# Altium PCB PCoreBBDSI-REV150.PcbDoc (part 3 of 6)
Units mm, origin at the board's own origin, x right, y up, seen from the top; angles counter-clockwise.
Board outline 100 x 72 mm, 6 copper layers (Top Layer, Int1 (GND), Int2 (Sign), Int3 (Sign), Int4 (GND), Bottom Layer), stack 1.538 mm thick; 358 components, 405 nets, 1521 pads, 834 vias.
Unrouted connection lines stored in the file: 10.

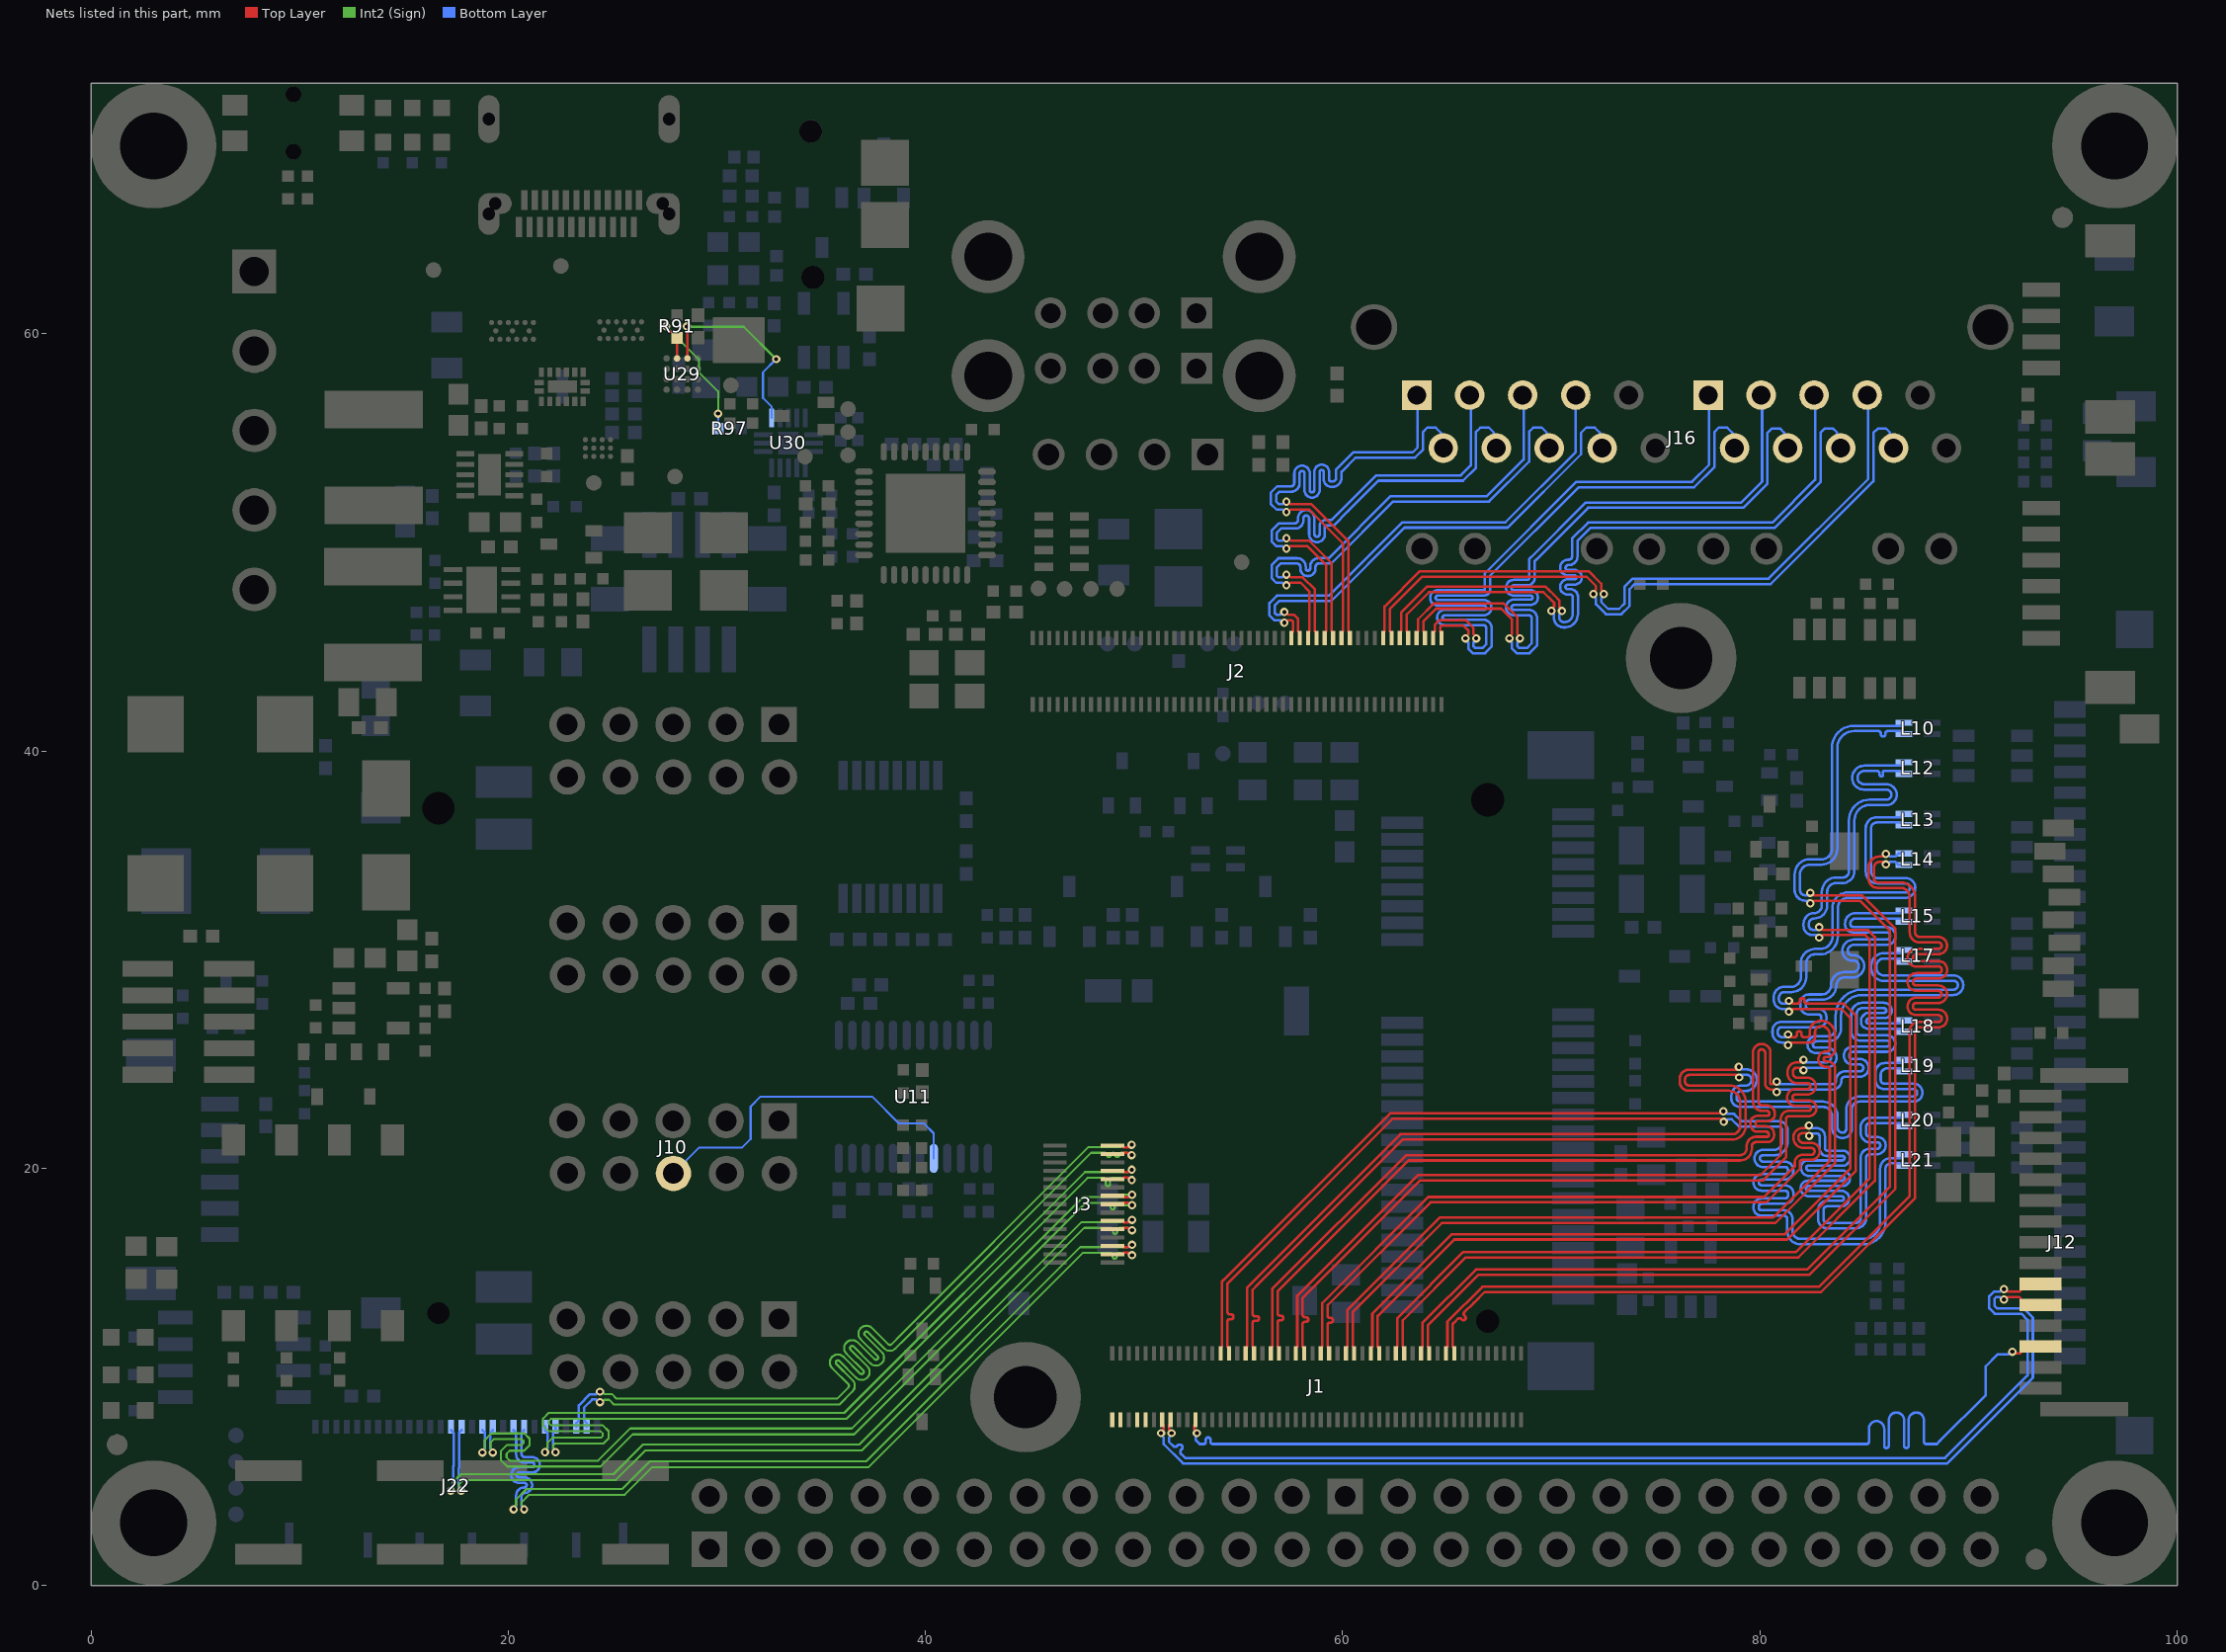
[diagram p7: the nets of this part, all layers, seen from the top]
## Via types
v1: diameter 0.4, hole 0.2, Top Layer to Bottom Layer, tented both sides, 706 vias
v2: diameter 0.5, hole 0.3, Top Layer to Bottom Layer, tented both sides, 102 vias
v3: diameter 0.4, hole 0.2, Top Layer to Bottom Layer, tented bottom, 16 vias
v4: diameter 0.9, hole 0.9, Top Layer to Bottom Layer, tented both sides, 6 vias
v5: diameter 0.5, hole 0.5, Top Layer to Bottom Layer, 2 vias
v6: diameter 3.2, hole 3.2, Top Layer to Bottom Layer, 2 vias

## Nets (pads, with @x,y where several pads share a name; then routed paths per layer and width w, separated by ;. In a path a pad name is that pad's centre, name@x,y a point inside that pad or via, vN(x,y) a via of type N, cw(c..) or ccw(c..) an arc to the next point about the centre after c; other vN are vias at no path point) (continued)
CSI_A_DATA0_P: J1.80 J12.3 | length 52.7
  Top Layer w0.12: J1.80@52.95,7.94 52.95,7.72 52.91,7.68 52.878,7.68 52.878,7.442 53.01,7.31 v1(53.01,7.3) ; v1(92.1,11.2) 92.176,11.2 92.259,11.117 92.471,11.117 92.51,11.156 92.51,11.21 92.75,11.45 J12.3@93.45,11.45
  Bottom Layer w0.12: v1(53.01,7.3) 52.965,7.255 52.965,6.959 53.07,6.853 53.146,6.777 53.33,6.777 ccw(c53.33,6.887) 53.44,6.887 53.44,6.985 cw(c53.55,6.985) 53.66,6.985 53.66,6.887 ccw(c53.77,6.887) 53.77,6.777 54.05,6.777 83.97,6.777 85.113,6.777 ccw(c85.113,6.887) 85.223,6.887 85.223,7.506 cw(c85.59,7.506) 85.59,7.873 cw(c85.59,7.506) 85.957,7.506 85.957,6.696 ccw(c86.067,6.696) 86.067,6.586 ccw(c86.067,6.696) 86.177,6.696 86.177,7.921 cw(c86.544,7.921) 86.544,8.288 cw(c86.544,7.921) 86.911,7.921 86.911,6.696 ccw(c87.021,6.696) 87.021,6.586 ccw(c87.021,6.696) 87.131,6.696 87.131,7.921 cw(c87.498,7.921) 87.498,8.288 cw(c87.498,7.921) 87.865,7.921 87.865,6.887 ccw(c87.975,6.887) 87.975,6.777 88.482,6.777 88.64,6.935 90.831,9.126 90.831,10.508 91.402,11.078 91.903,11.078 92.024,11.2 v1(92.1,11.2)
CSI_A_DATA1_N: J1.88 J12.5 | length 52.9
  Top Layer w0.12: v1(51.29,7.3) 51.307,7.3 51.422,7.415 51.422,7.68 51.39,7.68 51.35,7.72 J1.88@51.35,7.94 ; v1(91.7,13.7) 91.776,13.7 91.897,13.822 92.164,13.822 92.44,13.822 92.51,13.751 92.51,13.69 92.75,13.45 J12.5@93.45,13.45
  Bottom Layer w0.12: v1(51.29,7.3) 51.29,7.224 51.417,7.098 51.417,6.777 52.342,5.852 88.979,5.852 93.082,9.955 93.082,12.833 92.635,13.28 91.36,13.28 91.25,13.39 91.25,13.751 91.32,13.822 91.503,13.822 91.624,13.7 v1(91.7,13.7)
CSI_A_DATA1_P: J1.86 J12.6 | length 52.8
  Top Layer w0.12: J1.86@51.75,7.94 51.75,7.72 51.71,7.68 51.678,7.68 51.678,7.41 51.789,7.3 v1(51.8,7.3) ; v1(91.7,14.2) 91.776,14.2 91.897,14.078 92.27,14.078 92.44,14.078 92.51,14.149 92.51,14.21 92.75,14.45 J12.6@93.45,14.45
  Bottom Layer w0.12: v1(51.8,7.3) 51.8,7.224 51.673,7.098 51.673,7.021 51.673,6.884 51.873,6.684 ccw(c51.969,6.78) 52.064,6.684 52.09,6.71 cw(c52.186,6.615) 52.281,6.71 cw(c52.186,6.615) 52.281,6.519 52.255,6.493 ccw(c52.351,6.398) 52.255,6.302 52.449,6.109 52.528,6.109 88.873,6.109 92.825,10.061 92.825,12.727 92.529,13.023 91.254,13.023 90.993,13.284 90.993,13.858 91.214,14.078 91.503,14.078 91.624,14.2 v1(91.7,14.2)
CSI_A_DATA2_N: J1.94
CSI_A_DATA2_P: J1.92
CSI_A_DATA3_N: J1.100
CSI_A_DATA3_P: J1.98
CSI_B_CLK_N: J3.6 J22.9 | length 41.9
  Top Layer w0.12: J3.6@49.425,16.276 49.496,16.204 49.705,16.204 49.826,16.326 v1(49.897,16.326)
  Int2 (Sign) w0.1: v1(20.262,3.65) 20.262,3.731 20.372,3.842 20.372,4.116 20.882,4.625 25.464,4.625 26.79,5.951 37.158,5.951 47.422,16.216 49.705,16.216 49.816,16.326 v1(49.897,16.326)
  Bottom Layer w0.12: J22.9@20.26,7.46 20.26,7.435 20.382,7.313 20.382,6.933 ; v1(20.262,3.65) 20.262,3.708 20.381,3.827 20.381,4.006 ; 20.38,4.007 cw(c20.511,4.021) 20.38,4.021 20.38,4.305 cw(c20.768,4.305) 20.768,4.694 ccw(c20.768,4.807) 20.768,4.919 20.516,4.919 cw(c20.516,5.294) 20.516,5.669 21.135,5.669 ccw(c21.135,5.782) 21.135,5.894 20.768,5.894 cw(c20.768,6.283) 20.38,6.283 20.38,6.477 20.382,6.479 20.382,6.933
CSI_B_CLK_P: J3.4 J22.8 | length 41.9
  Top Layer w0.12: J3.4@49.425,15.876 49.496,15.948 49.705,15.948 49.826,15.826 v1(49.897,15.826)
  Int2 (Sign) w0.1: v1(20.762,3.65) 20.762,3.731 20.651,3.842 20.651,4 20.997,4.346 25.579,4.346 26.905,5.672 37.273,5.672 47.538,15.936 48.62,15.936 48.87,15.936 cw(c48.87,15.836) 48.97,15.836 48.97,15.757 ccw(c49.07,15.757) 49.17,15.757 49.17,15.836 cw(c49.27,15.836) 49.27,15.936 49.43,15.936 49.705,15.936 49.816,15.826 v1(49.897,15.826)
  Bottom Layer w0.12: 20.639,7.039 20.639,6.479 20.642,6.477 20.642,6.283 ccw(c20.768,6.283) 20.768,6.157 21.135,6.157 cw(c21.135,5.782) 21.135,5.407 20.516,5.407 ccw(c20.516,5.294) 20.516,5.181 20.768,5.181 cw(c20.768,4.807) 20.768,4.432 ccw(c20.768,4.305) 20.642,4.305 20.642,4.021 cw(c20.511,4.021) 20.641,4.007 ; 20.638,7.04 20.638,7.313 20.76,7.435 J22.8@20.76,7.46 ; 20.642,4.006 20.642,3.827 20.762,3.708 v1(20.762,3.65)
CSI_B_DATA0_N: J3.12 J22.15 | length 42
  Top Layer w0.12: J3.12@49.425,17.476 49.496,17.404 49.705,17.404 49.826,17.526 v1(49.9,17.526)
  Int2 (Sign) w0.1: v1(17.252,4.53) v1@17.252,4.602 ; v1@17.252,4.611 v1@17.252,4.602 ; v1@17.343,4.53 v1@17.343,4.693 ; v1@17.343,4.703 v1@17.343,4.693 ; v1(49.9,17.526) 49.819,17.526 49.708,17.416 47.492,17.416 36.828,6.751 26.46,6.751 25.045,5.336 19.509,5.336 17.731,5.336 17.362,4.967 17.362,4.712 v1@17.343,4.693 ; v1@17.252,4.602 v1@17.343,4.693
  Bottom Layer w0.12: J22.15@17.26,7.46 17.26,7.435 17.381,7.313 17.381,5.73 17.373,5.722 17.373,4.727 17.305,4.659 17.305,4.596 v1@17.371,4.53
CSI_B_DATA0_P: J3.10 J22.14 | length 42
  Top Layer w0.12: J3.10@49.425,17.076 49.496,17.148 49.705,17.148 49.826,17.026 v1(49.9,17.026)
  Int2 (Sign) w0.1: v1@17.66,4.53 v1@17.66,4.693 ; v1@17.66,4.703 v1@17.66,4.693 ; v1(17.752,4.53) v1@17.752,4.602 ; v1@17.752,4.611 v1@17.752,4.602 ; v1(49.9,17.026) 49.819,17.026 49.708,17.136 49.45,17.136 49.291,17.136 ccw(c49.291,17.036) 49.191,17.036 49.191,16.949 cw(c49.091,16.949) 48.991,16.949 48.991,17.036 ccw(c48.891,17.036) 48.891,17.136 48.641,17.136 47.608,17.136 36.943,6.472 26.575,6.472 25.16,5.057 17.847,5.057 17.641,4.851 17.641,4.712 v1@17.66,4.693 ; v1@17.66,4.693 v1@17.752,4.602
  Bottom Layer w0.12: v1@17.752,4.488 17.752,4.606 17.63,4.727 17.63,5.616 17.638,5.624 17.638,7.313 17.76,7.435 J22.14@17.76,7.46
CSI_B_DATA1_N: J3.18 J22.12 | length 41.9
  Top Layer w0.12: J3.18@49.425,18.676 49.496,18.604 49.705,18.604 49.826,18.726 v1(49.9,18.726)
  Int2 (Sign) w0.1: v1(18.76,6.37) 18.76,6.451 18.87,6.562 18.87,6.969 19.191,7.289 20.767,7.289 21.02,7.037 21.02,6.72 20.76,6.46 20.068,6.46 19.919,6.311 19.919,6.131 20.073,5.977 24.302,5.977 25.847,7.521 36.468,7.521 47.562,18.616 49.368,18.616 ccw(c49.368,18.671) 49.407,18.631 49.502,18.726 v1(49.9,18.726)
  Bottom Layer w0.12: v1(18.76,6.37) 18.76,6.446 18.882,6.567 18.882,7.313 18.76,7.435 J22.12@18.76,7.46
CSI_B_DATA1_P: J3.16 J22.11 | length 41.9
  Top Layer w0.12: J3.16@49.425,18.276 49.496,18.348 49.705,18.348 49.826,18.226 v1(49.9,18.226)
  Int2 (Sign) w0.1: v1(19.26,6.37) 19.26,6.451 19.15,6.562 19.15,6.853 19.307,7.01 20.652,7.01 20.741,6.921 20.741,6.836 20.644,6.739 19.952,6.739 19.64,6.427 19.64,6.016 19.958,5.698 24.418,5.698 25.962,7.242 36.583,7.242 47.678,18.336 48.523,18.336 48.773,18.336 cw(c48.773,18.236) 48.873,18.236 48.873,18.123 ccw(c48.973,18.123) 49.073,18.123 49.073,18.236 cw(c49.173,18.236) 49.173,18.336 49.368,18.336 cw(c49.368,18.281) 49.407,18.321 49.489,18.239 49.502,18.226 v1(49.9,18.226)
  Bottom Layer w0.12: v1(19.26,6.37) 19.26,6.446 19.138,6.567 19.138,7.313 19.26,7.435 J22.11@19.26,7.46
CSI_B_DATA2_N: J3.24 J22.6 | length 41.8
  Top Layer w0.12: J3.24@49.425,19.876 49.496,19.804 49.705,19.804 49.826,19.926 v1(49.89,19.926)
  Int2 (Sign) w0.1: v1(21.76,6.39) 21.76,6.462 21.87,6.572 21.88,6.572 21.88,6.836 22.123,7.079 24.439,7.079 24.53,7.17 24.53,7.28 24.42,7.39 21.93,7.39 21.67,7.65 21.67,8 21.941,8.271 36.108,8.271 47.652,19.816 48.43,19.816 49.366,19.816 49.698,19.816 49.809,19.926 v1(49.89,19.926)
  Bottom Layer w0.12: v1(21.76,6.39) 21.76,6.447 21.882,6.569 21.882,7.313 21.76,7.435 J22.6@21.76,7.61
CSI_B_DATA2_P: J3.22 J22.5 | length 41.9
  Top Layer w0.12: J3.22@49.425,19.476 49.496,19.548 49.705,19.548 49.826,19.426 v1(49.89,19.426)
  Int2 (Sign) w0.1: v1@22.209,6.512 22.26,6.462 v1(22.26,6.39) ; v1@22.214,6.517 22.168,6.563 22.159,6.563 22.159,6.72 22.239,6.8 24.555,6.8 24.809,7.054 24.809,7.396 24.536,7.669 22.046,7.669 21.949,7.766 21.949,7.885 22.057,7.992 36.223,7.992 47.768,19.536 48.295,19.536 48.545,19.536 cw(c48.545,19.436) 48.645,19.436 48.645,19.243 ccw(c48.745,19.243) 48.845,19.243 48.845,19.436 cw(c48.945,19.436) 48.945,19.536 49.25,19.536 49.698,19.536 49.809,19.426 v1(49.89,19.426)
  Bottom Layer w0.12: v1(22.26,6.39) 22.26,6.447 22.138,6.569 22.138,7.313 22.26,7.435 J22.5@22.26,7.61
CSI_B_DATA3_N: J3.30 J22.3 | length 42
  Top Layer w0.12: J3.30@49.425,21.076 49.496,21.004 49.705,21.004 49.826,21.126 v1(49.887,21.126)
  Int2 (Sign) w0.1: v1(24.4,9.288) 24.481,9.288 24.592,9.178 24.958,9.178 25.188,8.948 35.292,8.948 35.757,8.948 36.303,9.495 ccw(c36.23,9.568) 36.303,9.642 35.529,10.416 cw(c35.799,10.686) 35.528,10.956 ; v1(49.887,21.126) 49.829,21.126 ccw(c49.829,21.071) 49.79,21.11 49.712,21.031 cw(c49.673,21.071) 49.673,21.016 47.824,21.016 38.843,12.035 38.366,11.557 cw(c38.292,11.63) 38.219,11.557 37.441,12.335 ccw(c37.171,12.064) 36.9,12.335 36.899,12.334 ccw(c37.171,12.064) 36.9,11.794 37.701,10.993 cw(c37.628,10.92) 37.701,10.847 cw(c37.628,10.92) 37.555,10.847 36.754,11.647 ccw(c36.483,11.377) 36.213,11.647 36.212,11.647 ccw(c36.483,11.377) 36.213,11.106 37.014,10.306 cw(c36.941,10.232) 37.014,10.159 cw(c36.941,10.232) 36.867,10.159 36.07,10.957 ccw(c35.799,10.686) 35.529,10.957 ; 35.528,10.956 35.529,10.957
  Bottom Layer w0.12: J22.3@23.26,7.61 23.26,7.785 23.382,7.907 23.382,8.635 23.914,9.167 24.203,9.167 24.324,9.288 v1(24.4,9.288)
CSI_B_DATA3_P: J3.28 J22.2 | length 42
  Top Layer w0.12: J3.28@49.425,20.676 49.496,20.748 49.705,20.748 49.826,20.626 v1(49.887,20.626)
  Int2 (Sign) w0.1: v1(24.4,8.788) 24.481,8.788 24.592,8.899 24.842,8.899 25.072,8.669 35.571,8.669 35.757,8.669 35.872,8.669 36.501,9.297 ccw(c36.23,9.568) 36.542,9.79 36.542,9.798 36.501,9.838 35.726,10.613 cw(c35.799,10.686) 35.726,10.76 cw(c35.799,10.686) 35.872,10.76 36.67,9.962 ccw(c36.941,10.232) 37.211,9.962 ccw(c36.941,10.232) 37.211,10.503 36.41,11.304 cw(c36.483,11.377) 36.41,11.45 cw(c36.483,11.377) 36.557,11.45 37.357,10.649 ccw(c37.628,10.92) 37.898,10.648 ; v1(49.887,20.626) 49.829,20.626 cw(c49.829,20.681) 49.79,20.642 49.712,20.721 ccw(c49.673,20.681) 49.673,20.736 49.593,20.736 49.39,20.736 ccw(c49.39,20.636) 49.29,20.636 49.29,20.628 cw(c49.19,20.628) 49.09,20.628 49.09,20.636 ccw(c48.99,20.636) 48.89,20.636 48.89,20.628 cw(c48.79,20.628) 48.69,20.628 48.69,20.636 ccw(c48.59,20.636) 48.59,20.736 48.34,20.736 47.94,20.736 39.041,11.837 38.563,11.36 cw(c38.292,11.63) 38.022,11.36 37.244,12.138 ccw(c37.171,12.064) 37.098,12.138 ccw(c37.171,12.064) 37.098,11.991 37.898,11.19 cw(c37.628,10.92) 37.898,10.649 ; 37.898,10.648 37.898,10.649
  Bottom Layer w0.12: J22.2@23.76,7.61 23.76,7.785 23.638,7.907 23.638,8.528 24.02,8.91 24.203,8.91 24.324,8.788 v1(24.4,8.788)
CTS_B_RS232: J10.6 U11.17 | length 16.8
  Bottom Layer w0.1: J10.6@27.92,19.75 29.16,20.99 31.21,20.99 31.62,21.4 31.62,22.95 32.1,23.43 37.447,23.43 38.737,22.14 39.93,22.14 40.395,21.675 U11.17@40.395,20.47
DSI_A_CLK_N: J1.19 L14.4 | length 56.4
  Top Layer w0.12: J1.19@64.948,11.368 65.022,11.442 65.022,11.952 65.022,12.644 66.696,14.318 82.827,14.318 87.185,18.675 87.185,26.591 cw(c87.6,26.591) 87.6,27.007 88.557,27.007 ccw(c88.557,27.17) 88.72,27.17 ccw(c88.55,27.17) 88.55,27.34 87.483,27.34 cw(c87.483,27.75) 87.073,27.75 cw(c87.5,27.75) 87.5,28.177 88.547,28.177 ccw(c88.547,28.34) 88.71,28.34 ccw(c88.55,28.34) 88.55,28.5 87.493,28.5 cw(c87.493,28.92) 87.073,28.92 cw(c87.5,28.92) 87.5,29.347 88.557,29.347 ccw(c88.557,29.51) 88.72,29.51 ccw(c88.56,29.51) 88.56,29.67 87.493,29.67 cw(c87.493,30.09) 87.073,30.09 cw(c87.49,30.09) 87.49,30.507 88.547,30.507 ccw(c88.547,30.67) 88.71,30.67 ccw(c88.55,30.67) 88.55,30.83 87.653,30.83 cw(c87.653,31.3) 87.183,31.3 87.183,33.007 ccw(c86.75,33.007) 86.75,33.44 85.633,33.44 cw(c85.633,33.86) 85.213,33.86 85.213,34.421 cw(c85.73,34.421) 85.73,34.938 85.918,34.938 ccw(c85.918,35.06) v1(86.04,35.06)
  Bottom Layer w0.12: v1(86.04,35.06) 86.116,35.06 86.237,34.938 86.498,34.938 86.645,35.085 L14.4@86.895,35.085
DSI_A_CLK_P: J1.17 L14.1 | length 56.3
  Top Layer w0.12: J1.17@65.348,11.372 65.278,11.442 65.278,11.845 65.278,12.537 65.324,12.582 65.522,12.78 cw(c65.599,12.703) 65.677,12.78 65.713,12.744 ccw(c65.791,12.822) 65.869,12.744 ccw(c65.791,12.822) 65.869,12.9 65.833,12.936 cw(c65.911,13.014) 65.833,13.091 66.274,13.532 66.802,14.061 82.934,14.061 87.441,18.569 87.441,26.591 cw(c87.6,26.591) 87.6,26.75 88.557,26.75 ccw(c88.557,27.17) 88.977,27.17 ccw(c88.55,27.17) 88.55,27.597 87.483,27.597 cw(c87.483,27.75) 87.33,27.75 cw(c87.5,27.75) 87.5,27.92 88.547,27.92 ccw(c88.547,28.34) 88.967,28.34 ccw(c88.55,28.34) 88.55,28.757 87.493,28.757 cw(c87.493,28.92) 87.33,28.92 cw(c87.5,28.92) 87.5,29.09 88.557,29.09 ccw(c88.557,29.51) 88.977,29.51 ccw(c88.56,29.51) 88.56,29.927 87.493,29.927 cw(c87.493,30.09) 87.33,30.09 cw(c87.49,30.09) 87.49,30.25 88.547,30.25 ccw(c88.547,30.67) 88.967,30.67 ccw(c88.55,30.67) 88.55,31.087 87.653,31.087 cw(c87.653,31.3) 87.44,31.3 87.44,33.007 ccw(c86.75,33.007) 86.75,33.697 85.633,33.697 cw(c85.633,33.86) 85.47,33.86 85.47,34.421 cw(c85.73,34.421) 85.73,34.682 85.918,34.682 cw(c85.918,34.56) v1(86.04,34.56)
  Bottom Layer w0.12: v1(86.04,34.56) 86.116,34.56 86.237,34.682 86.498,34.682 86.645,34.535 L14.1@86.895,34.535
DSI_A_DATA0_N: J1.25 L10.4 | length 56.4
  Top Layer w0.12: J1.25@63.748,11.368 63.822,11.442 63.822,12.574 66.386,15.138 82.257,15.138 86.234,19.116 86.234,27.115 86.234,31.376 84.789,32.822 84.012,32.822 82.607,32.822 82.486,32.7 v1(82.41,32.7)
  Bottom Layer w0.12: v1(82.41,32.7) ccw(c82.288,32.7) 82.288,32.822 82.19,32.822 cw(c82.19,33.348) 81.663,33.348 81.663,34.08 cw(c82.39,34.08) 82.39,34.807 82.947,34.807 ccw(c82.947,35.313) 83.453,35.313 83.453,40.148 ; 83.453,40.15 cw(c84.512,40.15) 84.512,41.208 86.748,41.208 ccw(c86.748,41.355) L10.4@86.895,41.355
DSI_A_DATA0_P: J1.23 L10.1 | length 56.3
  Top Layer w0.12: J1.23@64.148,11.372 64.078,11.442 64.078,12.467 66.492,14.881 82.363,14.881 86.491,19.009 86.491,27.372 86.491,31.482 84.895,33.078 82.607,33.078 82.539,33.146 v1@82.476,33.146
  Bottom Layer w0.12: v1(82.41,33.2) cw(c82.288,33.2) 82.288,33.078 82.19,33.078 cw(c82.19,33.348) 81.92,33.348 81.92,34.08 cw(c82.39,34.08) 82.39,34.55 82.947,34.55 ccw(c82.947,35.313) 83.71,35.313 83.71,40.147 ccw(c83.582,40.148) 83.71,40.149 cw(c84.512,40.15) 84.512,40.952 85.401,40.952 85.681,40.952 cw(c85.681,40.842) 85.791,40.842 85.791,40.801 ccw(c85.901,40.801) 86.011,40.801 86.011,40.842 cw(c86.121,40.842) 86.121,40.952 86.705,40.952 86.748,40.952 cw(c86.748,40.805) L10.1@86.895,40.805
DSI_A_DATA1_N: J1.31 L12.4 | length 56.4
  Top Layer w0.12: J1.31@62.548,11.368 62.622,11.442 62.622,12.037 62.622,12.814 65.787,15.98 81.739,15.98 85.255,19.496 85.255,30.976 85.058,31.172 83.019,31.172 82.916,31.069 82.916,31.05 v1(82.84,31.05)
  Bottom Layer w0.12: v1(82.84,31.05) ccw(c82.718,31.05) 82.718,31.172 82.53,31.172 cw(c82.53,31.609) 82.093,31.609 82.093,31.72 cw(c82.6,31.72) 82.6,32.227 ccw(c82.6,32.597) 82.97,32.597 82.97,33.247 cw(c83.65,33.247) 83.65,33.927 83.957,33.927 ccw(c83.957,34.24) 84.27,34.24 84.27,36.677 cw(c85.26,36.677) 85.26,37.667 86.067,37.667 ccw(c86.067,37.9) 86.3,37.9 ccw(c86.05,37.9) 86.05,38.15 84.983,38.15 cw(c84.983,38.71) 84.423,38.71 cw(c85.01,38.71) 85.01,39.297 86.737,39.297 ccw(c86.737,39.455) L12.4@86.895,39.455
DSI_A_DATA1_P: J1.29 L12.1 | length 56.5
  Top Layer w0.12: J1.29@62.948,11.372 62.878,11.442 62.878,11.931 62.878,12.708 65.894,15.723 81.845,15.723 85.511,19.389 85.511,31.082 85.165,31.429 83.019,31.429 82.897,31.55 v1@82.72,31.55
  Bottom Layer w0.12: v1(82.84,31.55) cw(c82.718,31.55) 82.718,31.429 82.53,31.429 cw(c82.53,31.609) 82.35,31.609 82.35,31.72 cw(c82.6,31.72) 82.6,31.97 ccw(c82.6,32.597) 83.227,32.597 83.227,33.247 cw(c83.65,33.247) 83.65,33.67 83.957,33.67 ccw(c83.957,34.24) 84.527,34.24 84.527,36.677 cw(c85.26,36.677) 85.26,37.41 86.067,37.41 ccw(c86.067,37.9) 86.557,37.9 ccw(c86.05,37.9) 86.05,38.407 84.983,38.407 cw(c84.983,38.71) 84.68,38.71 cw(c85.01,38.71) 85.01,39.04 85.61,39.04 cw(c85.61,38.91) 85.74,38.91 85.74,38.86 ccw(c85.82,38.86) 85.82,38.78 ccw(c85.82,38.86) 85.9,38.86 85.9,38.98 cw(c85.96,38.98) 85.96,39.04 86.76,39.04 cw(c86.76,38.905) L12.1@86.895,38.905
DSI_A_DATA2_N: J1.37 L13.4 | length 56.3
  Top Layer w0.12: J1.37@61.348,11.368 61.422,11.442 61.422,13.024 65.237,16.839 81.197,16.839 84.341,19.983 84.341,27.198 83.907,27.632 81.569,27.632 81.437,27.5 v1(81.39,27.5)
  Bottom Layer w0.12: v1(81.39,27.5) ccw(c81.259,27.5) 81.259,27.632 81.11,27.632 cw(c81.11,28.089) 80.653,28.089 80.653,28.18 cw(c81.17,28.18) 81.17,28.697 81.507,28.697 ccw(c81.507,29.15) 81.96,29.15 81.96,29.827 cw(c82.64,29.827) 82.64,30.507 82.877,30.507 ccw(c82.877,31.11) 83.48,31.11 83.48,32.477 cw(c84.22,32.477) 84.22,33.217 86.957,33.217 ccw(c86.957,33.45) 87.19,33.45 ccw(c86.99,33.45) 86.99,33.65 85.643,33.65 cw(c85.643,34.22) 85.073,34.22 85.073,36.3 cw(c85.6,36.3) 85.6,36.827 86.737,36.827 ccw(c86.737,36.985) L13.4@86.895,36.985
DSI_A_DATA2_P: J1.35 L13.1 | length 56.3
  Top Layer w0.12: J1.35@61.748,11.372 61.678,11.442 61.678,12.917 65.343,16.582 81.303,16.582 84.598,19.877 84.598,27.304 84.014,27.889 82.526,27.889 82.246,27.889 cw(c82.246,27.999) 82.136,27.999 82.136,28.045 ccw(c82.026,28.045) 81.916,28.045 81.916,27.999 cw(c81.806,27.999) 81.806,27.889 81.569,27.889 81.437,28.02 v1(81.39,28.02)
  Bottom Layer w0.12: v1(81.39,28.02) cw(c81.259,28.02) 81.259,27.889 81.11,27.889 cw(c81.11,28.089) 80.91,28.089 80.91,28.18 cw(c81.17,28.18) 81.17,28.44 81.507,28.44 ccw(c81.507,29.15) 82.217,29.15 82.217,29.827 cw(c82.64,29.827) 82.64,30.25 82.877,30.25 ccw(c82.877,31.11) 83.737,31.11 83.737,32.477 cw(c84.22,32.477) 84.22,32.96 86.957,32.96 ccw(c86.957,33.45) 87.447,33.45 ccw(c86.99,33.45) 86.99,33.907 85.643,33.907 cw(c85.643,34.22) 85.33,34.22 85.33,36.3 cw(c85.6,36.3) 85.6,36.57 86.76,36.57 cw(c86.76,36.435) L13.1@86.895,36.435
DSI_A_DATA3_N: J1.43 L15.4 | length 56.3
  Top Layer w0.12: J1.43@60.148,11.368 60.222,11.442 60.222,13.203 64.65,17.631 80.631,17.631 83.35,20.35 83.35,23.91 83.35,24.751 ccw(c83.24,24.751) 83.24,24.861 83.169,24.861 cw(c83.169,25.228) 83.169,25.595 83.24,25.595 ccw(c83.24,25.705) 83.35,25.705 83.35,26.37 83.35,26.39 ccw(c82.93,26.39) 82.93,26.81 ccw(c82.93,26.52) 82.64,26.52 82.64,26.284 cw(c82.383,26.284) 82.383,26.027 81.477,26.027 ccw(c81.477,25.9) v1(81.35,25.9)
  Bottom Layer w0.12: v1(81.35,25.9) ccw(c81.223,25.9) 81.223,26.027 81.047,26.027 cw(c81.047,26.47) 80.603,26.47 80.603,26.59 cw(c81.03,26.59) 81.03,27.017 82.787,27.017 ccw(c82.787,27.16) 82.93,27.16 82.93,27.25 ccw(c82.81,27.25) 82.81,27.37 82.353,27.37 cw(c82.353,27.78) 81.943,27.78 81.943,27.91 cw(c82.36,27.91) 82.36,28.327 82.967,28.327 ccw(c82.967,28.77) 83.41,28.77 cw(c84.037,28.77) 84.037,29.397 84.437,29.397 ccw(c84.437,29.7) 84.74,29.7 ccw(c84.49,29.7) 84.49,29.95 84.423,29.95 cw(c84.423,30.42) 83.953,30.42 cw(c84.49,30.42) 84.49,30.957 86.067,30.957 ccw(c86.067,31.13) 86.24,31.13 ccw(c86.06,31.13) 86.06,31.31 84.46,31.31 cw(c84.46,31.687) 84.083,31.687 84.083,31.73 cw(c84.58,31.73) 84.58,32.227 86.767,32.227 ccw(c86.767,32.355) L15.4@86.895,32.355
DSI_A_DATA3_P: J1.41 L15.1 | length 56.2
  Top Layer w0.12: J1.41@60.548,11.372 60.478,11.442 60.478,13.096 64.756,17.374 80.738,17.374 83.607,20.244 83.607,23.91 83.607,24.751 ccw(c83.24,24.751) 83.24,25.118 83.169,25.118 cw(c83.169,25.228) 83.169,25.338 83.24,25.338 ccw(c83.24,25.705) 83.607,25.705 83.607,26.37 83.607,26.39 ccw(c82.93,26.39) 82.93,27.067 ccw(c82.93,26.52) 82.383,26.52 82.383,26.39 cw(c82.277,26.39) 82.383,26.387 cw(c82.277,26.39) 82.323,26.294 82.277,26.283 82.103,26.283 cw(c82.103,26.393) 81.993,26.393 81.993,26.456 ccw(c81.883,26.456) 81.773,26.456 81.773,26.393 cw(c81.663,26.393) 81.663,26.283 81.477,26.283 cw(c81.477,26.41) v1(81.35,26.41)
  Bottom Layer w0.12: v1(81.35,26.41) cw(c81.223,26.41) 81.223,26.283 81.047,26.283 cw(c81.047,26.47) 80.86,26.47 80.86,26.59 cw(c81.03,26.59) 81.03,26.76 82.787,26.76 ccw(c82.787,27.16) 83.187,27.16 83.187,27.25 ccw(c82.81,27.25) 82.81,27.627 82.353,27.627 cw(c82.353,27.78) 82.2,27.78 82.2,27.91 cw(c82.36,27.91) 82.36,28.07 82.967,28.07 ccw(c82.967,28.77) 83.667,28.77 cw(c84.037,28.77) 84.037,29.14 84.437,29.14 ccw(c84.437,29.7) 84.997,29.7 ccw(c84.49,29.7) 84.49,30.207 84.423,30.207 cw(c84.423,30.42) 84.21,30.42 cw(c84.49,30.42) 84.49,30.7 86.067,30.7 ccw(c86.067,31.13) 86.497,31.13 ccw(c86.06,31.13) 86.06,31.567 84.46,31.567 cw(c84.46,31.687) 84.34,31.687 84.34,31.73 cw(c84.58,31.73) 84.58,31.97 86.73,31.97 cw(c86.73,31.805) L15.1@86.895,31.805
DSI_B_CLK_N: J1.49 L20.4 | length 56.2
  Top Layer w0.12: J1.49@58.948,11.368 59.021,11.442 59.021,12.399 59.022,13.539 64.101,18.619 80.201,18.619 81.669,20.087 81.669,20.259 cw(c82.05,20.259) 82.05,20.64 82.46,20.64 ccw(c82.46,20.8) 82.62,20.8 82.62,20.82 ccw(c82.471,20.82) 82.471,20.969 82.1,20.969 cw(c82.1,21.47) 81.599,21.47 cw(c82.049,21.47) 82.049,21.92 82.22,21.92 ccw(c82.22,22.05) v1(82.35,22.05)
  Bottom Layer w0.12: v1(82.35,22.05) ccw(c82.472,22.05) 82.472,21.928 82.71,21.928 cw(c82.71,21.522) 83.117,21.522 83.117,20.953 ccw(c83.23,20.953) 83.23,20.84 83.967,20.84 cw(c83.967,20.49) 84.317,20.49 cw(c83.94,20.49) 83.94,20.113 82.303,20.113 ccw(c82.303,20.03) 82.22,20.03 ccw(c82.37,20.03) 82.37,19.88 83.957,19.88 cw(c83.957,19.52) 84.317,19.52 cw(c83.94,19.52) 83.94,19.143 82.313,19.143 ccw(c82.313,19.04) 82.21,19.04 ccw(c82.34,19.04) 82.34,18.91 83.917,18.91 cw(c83.917,18.55) 84.277,18.55 cw(c83.9,18.55) 83.9,18.173 83.213,18.173 ccw(c83.213,18.01) 83.05,18.01 83.05,17.55 ccw(c83.22,17.55) 83.22,17.38 84.61,17.38 ccw(c84.61,17.6) 84.83,17.6 84.83,20.507 cw(c85.25,20.507) 85.25,20.927 85.597,20.927 ccw(c85.597,21.1) 85.77,21.1 ccw(c85.63,21.1) 85.63,21.24 85.283,21.24 cw(c85.283,21.69) 84.833,21.69 84.833,21.98 cw(c85.272,21.98) 85.272,22.418 86.748,22.418 86.821,22.418 ccw(c86.821,22.484) 86.885,22.47 ccw(c86.438,22.565) 86.886,22.475 L20.4@86.895,22.565
DSI_B_CLK_P: J1.47 L20.1 | length 56.1
  Top Layer w0.12: J1.47@59.348,11.372 59.278,11.442 59.278,11.867 59.278,11.927 59.278,12.489 cw(c59.388,12.489) 59.388,12.599 59.422,12.599 ccw(c59.422,12.709) 59.422,12.819 59.388,12.819 cw(c59.388,12.929) 59.278,12.929 59.278,12.989 59.278,13.433 64.207,18.362 80.307,18.362 81.918,19.972 81.918,20.252 81.91,20.26 cw(c82.05,20.259) 82.05,20.399 82.46,20.399 ccw(c82.46,20.8) 82.861,20.8 82.861,20.82 ccw(c82.471,20.82) 82.471,21.21 82.1,21.21 cw(c82.1,21.47) 81.84,21.47 cw(c82.049,21.47) 82.049,21.679 82.22,21.679 ccw(c82.22,22.05) 82.237,21.679 cw(c82.231,21.55) v1(82.36,21.55)
  Bottom Layer w0.12: v1(82.36,21.55) cw(c82.482,21.55) 82.482,21.672 82.71,21.672 cw(c82.71,21.522) 82.86,21.522 82.86,20.953 ccw(c83.23,20.953) 83.23,20.583 83.967,20.583 cw(c83.967,20.49) 84.06,20.49 cw(c83.94,20.49) 83.94,20.37 82.303,20.37 ccw(c82.303,20.03) 81.963,20.03 ccw(c82.37,20.03) 82.37,19.623 83.957,19.623 cw(c83.957,19.52) 84.06,19.52 cw(c83.94,19.52) 83.94,19.4 82.313,19.4 ccw(c82.313,19.04) 81.953,19.04 ccw(c82.34,19.04) 82.34,18.653 83.917,18.653 cw(c83.917,18.55) 84.02,18.55 cw(c83.9,18.55) 83.9,18.43 83.213,18.43 ccw(c83.213,18.01) 82.793,18.01 82.793,17.55 ccw(c83.22,17.55) 83.22,17.123 84.61,17.123 ccw(c84.61,17.6) 85.087,17.6 85.087,20.507 cw(c85.25,20.507) 85.25,20.67 85.597,20.67 ccw(c85.597,21.1) 86.027,21.1 ccw(c85.63,21.1) 85.63,21.497 85.283,21.497 cw(c85.283,21.69) 85.09,21.69 85.09,21.98 cw(c85.272,21.98) 85.272,22.162 86.748,22.162 cw(c86.748,22.015) L20.1@86.895,22.015
DSI_B_DATA0_N: J1.55 L17.4 | length 56.5
  Top Layer w0.12: J1.55@57.75,11.12 57.75,11.37 57.822,11.442 57.822,13.885 63.614,19.677 80.047,19.677 80.99,20.62 80.99,22.337 cw(c81.4,22.337) 81.4,22.747 82.327,22.747 ccw(c82.327,22.87) 82.45,22.87 ccw(c82.33,22.87) 82.33,22.99 81.703,22.99 cw(c81.703,23.39) 81.303,23.39 cw(c81.7,23.39) 81.7,23.787 82.277,23.787 ccw(c82.277,23.93) 82.42,23.93 82.42,23.94 ccw(c82.28,23.94) 82.28,24.08 81.793,24.08 cw(c81.793,24.55) 81.323,24.55 81.323,24.62 cw(c81.78,24.62) 81.78,25.077 81.967,25.077 ccw(c81.967,25.2) v1(82.09,25.2)
  Bottom Layer w0.12: v1(82.09,25.2) ccw(c82.212,25.2) 82.212,25.079 83.179,25.079 ccw(c83.179,25.31) 83.41,25.31 ccw(c83.2,25.31) 83.2,25.52 82.683,25.52 cw(c82.683,25.92) 82.283,25.92 cw(c82.7,25.92) 82.7,26.337 83.277,26.337 ccw(c83.277,26.69) 83.63,26.69 83.63,27.297 cw(c84.89,27.297) 84.89,28.557 89.267,28.557 ccw(c89.267,28.78) 89.49,28.78 ccw(c89.29,28.78) 89.29,28.98 85.943,28.98 cw(c85.943,29.59) 85.333,29.59 85.333,29.7 cw(c85.94,29.7) 85.94,30.307 86.747,30.307 ccw(c86.747,30.455) L17.4@86.895,30.455
DSI_B_DATA0_P: J1.53 L17.1 | length 56.5
  Top Layer w0.12: J1.53@58.15,11.12 58.15,11.37 58.078,11.442 58.078,11.808 58.078,12.528 cw(c58.188,12.528) 58.188,12.638 58.241,12.638 ccw(c58.241,12.748) 58.241,12.858 58.188,12.858 cw(c58.188,12.968) 58.078,12.968 58.078,13.18 58.078,13.778 63.72,19.42 80.153,19.42 81.247,20.514 81.247,22.337 cw(c81.4,22.337) 81.4,22.49 82.327,22.49 ccw(c82.327,22.87) 82.707,22.87 ccw(c82.33,22.87) 82.33,23.247 81.703,23.247 cw(c81.703,23.39) 81.56,23.39 cw(c81.7,23.39) 81.7,23.53 82.277,23.53 ccw(c82.277,23.93) 82.677,23.93 82.677,23.94 ccw(c82.28,23.94) 82.28,24.337 81.793,24.337 cw(c81.793,24.55) 81.58,24.55 81.58,24.62 cw(c81.78,24.62) 81.78,24.82 81.97,24.82 cw(c81.97,24.7) v1(82.09,24.7)
  Bottom Layer w0.12: v1(82.09,24.7) cw(c82.212,24.7) 82.212,24.822 83.179,24.822 ccw(c83.179,25.31) 83.667,25.31 ccw(c83.2,25.31) 83.2,25.777 82.683,25.777 cw(c82.683,25.92) 82.54,25.92 cw(c82.7,25.92) 82.7,26.08 83.277,26.08 ccw(c83.277,26.69) 83.887,26.69 83.887,27.297 cw(c84.89,27.297) 84.89,28.3 89.267,28.3 ccw(c89.267,28.78) 89.747,28.78 ccw(c89.29,28.78) 89.29,29.237 85.943,29.237 cw(c85.943,29.59) 85.59,29.59 85.59,29.7 cw(c85.94,29.7) 85.94,30.05 86.75,30.05 cw(c86.75,29.905) L17.1@86.895,29.905
DSI_B_DATA1_N: J1.61 L18.4 | length 56.4
  Top Layer w0.12: J1.61@56.548,11.368 56.621,11.442 56.621,14.204 63.046,20.628 79.061,20.628 ccw(c79.061,20.92) 79.353,20.92 79.353,21.04 cw(c79.82,21.04) 79.82,21.507 80.357,21.507 ccw(c80.357,21.57) 80.42,21.57 80.42,21.63 ccw(c80.3,21.63) 80.3,21.75 79.883,21.75 cw(c79.883,22.007) 79.878,21.75 cw(c79.884,22.073) 79.655,21.845 cw(c79.884,22.073) 79.572,21.987 79.546,22.082 cw(c79.794,22.15) 79.537,22.15 cw(c79.904,22.15) 79.904,22.517 80.367,22.517 ccw(c80.367,22.61) 80.46,22.61 ccw(c80.32,22.61) 80.32,22.75 80.103,22.75 cw(c80.103,23.18) 79.948,22.779 cw(c80.103,23.18) 79.702,23.025 cw(c80.103,23.18) 79.673,23.18 79.673,25.55 cw(c80.08,25.55) 80.08,25.957 cw(c80.08,25.53) 80.507,25.53 80.507,24.073 ccw(c80.55,24.073) 80.55,24.03 80.68,24.03 ccw(c80.68,24.15) v1(80.8,24.15)
  Bottom Layer w0.12: v1(80.8,24.15) ccw(c80.922,24.15) 80.922,24.028 83.478,24.028 ccw(c83.478,24.2) 83.65,24.2 cw(c84.097,24.2) 84.097,24.647 84.807,24.647 ccw(c84.807,24.8) 84.96,24.8 ccw(c84.78,24.8) 84.78,24.98 84.433,24.98 cw(c84.433,25.39) 84.023,25.39 cw(c84.47,25.39) 84.47,25.837 86.097,25.837 ccw(c86.097,25.97) 86.23,25.97 ccw(c86.09,25.97) 86.09,26.11 84.823,26.11 cw(c84.823,26.56) 84.373,26.56 84.373,27.39 cw(c84.91,27.39) 84.91,27.927 85.94,27.927 cw(c85.94,27.55) 86.317,27.55 cw(c85.96,27.55) 85.96,27.193 85.253,27.193 ccw(c85.253,27.04) 85.1,27.04 85.1,27.03 ccw(c85.192,27.03) 85.192,26.938 86.748,26.938 ccw(c86.748,27.085) L18.4@86.895,27.085
DSI_B_DATA1_P: J1.59 L18.1 | length 56.3
  Top Layer w0.12: J1.59@56.948,11.372 56.878,11.442 56.878,12.602 cw(c56.988,12.602) 56.988,12.712 57.045,12.712 ccw(c57.045,12.822) 57.045,12.932 56.988,12.932 cw(c56.988,13.042) 56.878,13.042 56.878,13.372 56.878,14.097 63.152,20.371 79.061,20.371 ccw(c79.061,20.92) 79.61,20.92 79.61,21.04 cw(c79.82,21.04) 79.82,21.25 80.357,21.25 ccw(c80.357,21.57) 80.677,21.57 80.677,21.63 ccw(c80.3,21.63) 80.3,22.007 79.883,22.007 cw(c79.884,22.073) 79.82,22.056 79.794,22.15 cw(c79.904,22.15) 79.904,22.26 80.367,22.26 ccw(c80.367,22.61) 80.717,22.61 ccw(c80.32,22.61) 80.32,23.007 80.103,23.007 cw(c80.103,23.18) 79.93,23.18 79.93,25.55 cw(c80.08,25.55) 80.08,25.7 cw(c80.08,25.53) 80.25,25.53 80.25,24.073 ccw(c80.55,24.073) 80.55,23.773 80.677,23.773 cw(c80.677,23.65) v1(80.8,23.65)
  Bottom Layer w0.12: v1(80.8,23.65) cw(c80.922,23.65) 80.922,23.772 83.478,23.772 ccw(c83.478,24.2) 83.907,24.2 cw(c84.097,24.2) 84.097,24.39 84.807,24.39 ccw(c84.807,24.8) 85.217,24.8 ccw(c84.78,24.8) 84.78,25.237 84.433,25.237 cw(c84.433,25.39) 84.28,25.39 cw(c84.47,25.39) 84.47,25.58 86.097,25.58 ccw(c86.097,25.97) 86.487,25.97 ccw(c86.09,25.97) 86.09,26.367 84.823,26.367 cw(c84.823,26.56) 84.63,26.56 84.63,27.39 cw(c84.91,27.39) 84.91,27.67 85.94,27.67 cw(c85.94,27.55) 86.06,27.55 cw(c85.96,27.55) 85.96,27.45 85.253,27.45 ccw(c85.253,27.04) 84.843,27.04 84.843,27.03 ccw(c85.192,27.03) 85.192,26.682 86.748,26.682 cw(c86.748,26.535) L18.1@86.895,26.535
DSI_B_DATA2_N: J1.67 L19.4 | length 56.2
  Top Layer w0.12: J1.67@55.348,11.368 55.422,11.442 55.422,14.283 62.767,21.628 78.661,21.628 ccw(c78.661,22.027) 79.06,22.027 79.06,23.164 ccw(c78.513,23.164) 78.513,23.711 76.592,23.711 cw(c76.592,24.15) 76.153,24.15 76.153,24.27 cw(c76.61,24.27) 76.61,24.727 78.857,24.727 ccw(c78.857,24.86) v1(78.99,24.86)
  Bottom Layer w0.12: v1(78.99,24.86) ccw(c79.117,24.86) 79.117,24.733 79.364,24.733 cw(c79.364,24.25) 79.847,24.25 79.847,24.23 cw(c79.32,24.23) 79.32,23.703 79.113,23.703 ccw(c79.113,23.48) 78.89,23.48 78.89,23.34 ccw(c79.04,23.34) 79.04,23.19 83.027,23.19 cw(c83.027,22.5) 83.717,22.5 83.717,21.943 ccw(c83.96,21.943) 83.96,21.7 ccw(c83.96,21.88) 84.14,21.88 84.14,22.807 cw(c84.78,22.807) 84.78,23.447 87.367,23.447 ccw(c87.367,23.62) 87.54,23.62 ccw(c87.37,23.62) 87.37,23.79 85.973,23.79 cw(c85.973,24.23) 85.533,24.23 85.533,24.586 cw(c85.985,24.586) 85.985,25.038 86.748,25.038 ccw(c86.748,25.185) L19.4@86.895,25.185
DSI_B_DATA2_P: J1.65 L19.1 | length 56.2
  Top Layer w0.12: J1.65@55.748,11.372 55.678,11.442 55.678,11.856 55.678,12.576 cw(c55.788,12.576) 55.788,12.686 55.876,12.686 ccw(c55.876,12.796) 55.876,12.906 55.788,12.906 cw(c55.788,13.016) 55.678,13.016 55.678,14.176 55.936,14.433 62.873,21.371 78.661,21.371 ccw(c78.661,22.027) 79.317,22.027 79.317,23.164 ccw(c78.513,23.164) 78.513,23.968 76.592,23.968 cw(c76.592,24.15) 76.41,24.15 76.41,24.27 cw(c76.61,24.27) 76.61,24.47 78.88,24.47 cw(c78.88,24.35) v1(79,24.35)
  Bottom Layer w0.12: v1(79,24.35) cw(c79.127,24.35) 79.127,24.476 79.364,24.476 cw(c79.364,24.25) 79.59,24.25 79.59,24.23 cw(c79.32,24.23) 79.32,23.96 79.113,23.96 ccw(c79.113,23.48) 78.633,23.48 78.633,23.34 ccw(c79.04,23.34) 79.04,22.933 83.027,22.933 cw(c83.027,22.5) 83.46,22.5 83.46,21.943 ccw(c83.96,21.943) 83.96,21.443 ccw(c83.96,21.88) 84.397,21.88 84.397,22.807 cw(c84.78,22.807) 84.78,23.19 87.367,23.19 ccw(c87.367,23.62) 87.797,23.62 ccw(c87.37,23.62) 87.37,24.047 85.973,24.047 cw(c85.973,24.23) 85.79,24.23 85.79,24.48 cw(c86.092,24.48) 86.092,24.782 86.748,24.782 cw(c86.748,24.635) L19.1@86.895,24.635
DSI_B_DATA3_N: J1.73 L21.4 | length 56.2
  Top Layer w0.12: J1.73@54.15,11.12 54.15,11.37 54.221,11.442 54.221,12.2 54.222,14.574 54.291,14.643 62.277,22.629 78.073,22.629 78.174,22.73 v1(78.25,22.73)
  Bottom Layer w0.12: v1(78.25,22.73) 78.326,22.73 78.452,22.603 78.756,22.603 79.102,22.258 80.878,22.258 cw(c80.878,21.815) 81.321,21.815 81.321,21.25 cw(c80.694,21.25) 80.694,20.623 80.153,20.623 ccw(c80.153,20.47) 80,20.47 ccw(c80.16,20.47) 80.16,20.31 81.207,20.31 cw(c81.207,19.92) 81.597,19.92 81.597,19.86 cw(c81.19,19.86) 81.19,19.453 80.09,19.453 ccw(c80.09,19.31) 79.947,19.31 ccw(c80.077,19.31) 80.077,19.18 81.207,19.18 cw(c81.207,18.78) 81.607,18.78 81.607,18.7 cw(c81.2,18.7) 81.2,18.293 80.09,18.293 ccw(c80.09,18.15) 79.947,18.15 79.947,18.1 ccw(c80.067,18.1) 80.067,17.98 81.147,17.98 cw(c81.147,17.56) 81.567,17.56 81.567,16.983 ccw(c81.94,16.983) 81.94,16.61 84.97,16.61 ccw(c84.97,17.4) 85.76,17.4 85.76,19.967 cw(c86.28,19.967) 86.28,20.487 86.717,20.487 ccw(c86.717,20.665) L21.4@86.895,20.665
DSI_B_DATA3_P: J1.71 L21.1 | length 56.1
  Top Layer w0.12: J1.71@54.55,11.12 54.55,11.37 54.478,11.442 54.478,11.936 54.478,12.656 cw(c54.588,12.656) 54.588,12.766 54.656,12.766 ccw(c54.656,12.876) 54.656,12.986 54.588,12.986 cw(c54.588,13.096) 54.478,13.096 54.478,13.361 54.478,13.421 54.478,14.467 54.548,14.537 62.383,22.372 78.08,22.372 78.231,22.22 v1(78.26,22.22)
  Bottom Layer w0.12: v1(78.26,22.22) 78.336,22.22 78.462,22.346 78.65,22.346 78.995,22.001 80.878,22.001 cw(c80.878,21.815) 81.064,21.815 81.064,21.25 cw(c80.694,21.25) 80.694,20.88 80.153,20.88 ccw(c80.153,20.47) 79.743,20.47 ccw(c80.16,20.47) 80.16,20.053 81.207,20.053 cw(c81.207,19.92) 81.34,19.92 81.34,19.86 cw(c81.19,19.86) 81.19,19.71 80.09,19.71 ccw(c80.09,19.31) 79.69,19.31 ccw(c80.077,19.31) 80.077,18.923 81.207,18.923 cw(c81.207,18.78) 81.35,18.78 81.35,18.7 cw(c81.2,18.7) 81.2,18.55 80.09,18.55 ccw(c80.09,18.15) 79.69,18.15 79.69,18.1 ccw(c80.067,18.1) 80.067,17.723 81.147,17.723 cw(c81.147,17.56) 81.31,17.56 81.31,16.983 ccw(c81.94,16.983) 81.94,16.353 84.97,16.353 ccw(c84.97,17.4) 86.017,17.4 86.017,19.967 cw(c86.28,19.967) 86.28,20.23 86.78,20.23 cw(c86.78,20.115) L21.1@86.895,20.115
EN_SRC: R91.2 R97.2 U29.B4 | length 7.9
  Top Layer w0.1: v1(27.56,60.35) 27.56,60.33 R91.2@28.09,59.8 U29.B4@28.09,58.82
  Int2 (Sign) w0.1: v1(27.56,60.35) 29.14,58.77 29.14,58.15 30.06,57.23 30.06,56.4 v1(30.06,56.17)
  Bottom Layer w0.1: R97.2@30.06,55.45 v1(30.06,56.17) ; v1(30.06,56.17) 30.06,56.27 v1(30.06,56.17)
ETH_A_D1_N: J2.3 J16.L1 | length 32.9
  Top Layer w0.12: J2.3@64.338,45.658 64.412,45.732 64.412,46.046 64.632,46.267 65.893,46.267 66.273,45.886 66.273,45.602 66.4,45.476 v1(66.4,45.4)
  Bottom Layer w0.12: 64.794,47.707 64.56,47.707 ccw(c64.56,47.34) 64.193,47.34 ccw(c64.553,47.34) 64.553,46.98 66.76,46.98 cw(c66.76,46.87) 66.87,46.87 cw(c66.757,46.87) 66.757,46.757 64.89,46.757 ccw(c64.89,46.39) 64.523,46.39 ccw(c64.873,46.39) 64.873,46.04 66.73,46.04 cw(c66.73,45.89) 66.88,45.89 66.88,45.11 66.717,44.947 66.344,44.947 66.273,45.017 66.273,45.198 66.4,45.324 v1(66.4,45.4) ; 64.9,47.707 66.767,47.707 ccw(c66.767,47.75) 66.81,47.75 66.81,48.503 71.209,52.903 76.743,52.903 77.565,53.725 77.565,56.995 J16.L1@77.52,57.04
ETH_A_D1_P: J2.1 J16.L2 | length 33.1
  Top Layer w0.12: J2.1@64.738,45.662 64.668,45.732 64.668,45.94 64.739,46.01 65.786,46.01 66.016,45.78 66.016,45.602 65.89,45.476 v1(65.89,45.4)
  Bottom Layer w0.12: v1(65.89,45.4) 65.89,45.324 66.016,45.198 66.016,44.911 66.237,44.69 66.823,44.69 67.137,45.004 67.137,45.89 ccw(c66.73,45.89) 66.73,46.297 64.873,46.297 cw(c64.873,46.39) 64.78,46.39 cw(c64.89,46.39) 64.89,46.5 66.757,46.5 ccw(c66.757,46.87) 67.127,46.87 ccw(c66.76,46.87) 66.76,47.237 64.553,47.237 cw(c64.553,47.34) 64.45,47.34 cw(c64.56,47.34) 64.56,47.45 66.767,47.45 ccw(c66.767,47.75) 67.067,47.75 67.067,48.397 71.316,52.646 76.849,52.646 77.822,53.619 77.822,55.292 78.03,55.5 78.43,55.5 78.667,55.263 78.667,54.643 J16.L2@78.79,54.52
ETH_A_D2_N: J2.7 J16.L3 | length 33.3
  Top Layer w0.12: J2.7@63.538,45.658 63.612,45.732 63.612,46.313 64.377,47.078 67.703,47.078 68.373,46.408 68.373,45.602 68.5,45.476 v1(68.5,45.4)
  Bottom Layer w0.12: v1(68.5,45.4) 68.5,45.324 68.373,45.198 68.373,45.017 68.444,44.947 68.847,44.947 69.06,45.16 69.06,46.36 ccw(c68.92,46.36) 68.92,46.5 68.213,46.5 cw(c68.213,46.88) 67.833,46.88 cw(c68.21,46.88) 68.21,47.257 69.007,47.257 ccw(c69.007,47.35) 69.1,47.35 ccw(c69,47.35) 69,47.45 68.193,47.45 cw(c68.193,47.82) 67.823,47.82 cw(c68.2,47.82) 68.2,48.197 68.837,48.197 ccw(c68.837,48.31) 68.95,48.31 68.95,49.209 69.021,49.28 ; 69.035,49.294 71.653,51.912 79.102,51.912 80.105,52.915 80.105,56.995 J16.L3@80.06,57.04
ETH_A_D2_P: J2.5 J16.L4 | length 33.2
  Top Layer w0.12: J2.5@63.938,45.662 63.868,45.732 63.868,46.207 64.483,46.821 67.597,46.821 68.117,46.302 68.117,45.602 67.99,45.476 v1(67.99,45.4)
  Bottom Layer w0.12: v1(67.99,45.4) 67.99,45.324 68.117,45.198 68.117,44.911 68.337,44.69 68.953,44.69 69.317,45.054 69.317,46.36 ccw(c68.92,46.36) 68.92,46.757 68.213,46.757 cw(c68.213,46.88) 68.09,46.88 cw(c68.21,46.88) 68.21,47 69.007,47 ccw(c69.007,47.35) 69.357,47.35 ccw(c69,47.35) 69,47.707 68.193,47.707 cw(c68.193,47.82) 68.08,47.82 cw(c68.2,47.82) 68.2,47.94 68.837,47.94 ccw(c68.837,48.31) 69.207,48.31 69.207,49.102 69.278,49.174 71.76,51.655 79.209,51.655 80.362,52.809 80.362,55.242 80.583,55.463 80.957,55.463 81.157,55.263 81.157,54.693 J16.L4@81.33,54.52
ETH_A_D3_N: J2.11 J16.L5 | length 33.7
  Top Layer w0.12: J2.11@62.738,45.658 62.811,45.732 62.811,46.65 64.034,47.872 69.727,47.872 69.878,47.722 70.123,47.477 70.393,47.206 70.393,46.902 70.51,46.786 v1(70.51,46.71)
  Bottom Layer w0.12: v1(70.51,46.71) 70.51,46.658 70.383,46.531 70.383,46.391 ccw(c70.595,46.391) 70.595,46.18 70.64,46.18 ccw(c70.64,46.56) 71.02,46.56 71.02,47.39 ccw(c70.91,47.39) 70.91,47.5 70.783,47.5 cw(c70.783,47.86) 70.423,47.86 cw(c70.79,47.86) 70.79,48.227 71.11,48.227 ccw(c71.11,48.32) 71.203,48.32 ccw(c71.103,48.32) 71.103,48.42 70.783,48.42 cw(c70.783,48.78) 70.423,48.78 cw(c70.81,48.78) 70.81,49.167 70.84,49.167 ccw(c70.84,49.321) 70.995,49.321 70.995,50.178 71.761,50.945 80.595,50.945 82.645,52.995 82.645,56.995 J16.L5@82.6,57.04
ETH_A_D3_P: J2.9 J16.L6 | length 33.6
  Top Layer w0.12: J2.9@63.138,45.662 63.068,45.732 63.068,46.544 64.14,47.615 69.621,47.615 70.016,47.22 70.136,47.1 70.136,46.922 70.01,46.796 v1(70.01,46.72)
  Bottom Layer w0.12: v1(70.01,46.72) 70.01,46.658 70.126,46.541 70.126,46.391 ccw(c70.595,46.391) 70.595,45.923 70.64,45.923 ccw(c70.64,46.56) 71.277,46.56 71.277,47.39 ccw(c70.91,47.39) 70.91,47.757 70.783,47.757 cw(c70.783,47.86) 70.68,47.86 cw(c70.79,47.86) 70.79,47.97 71.11,47.97 ccw(c71.11,48.32) 71.46,48.32 ccw(c71.103,48.32) 71.103,48.677 70.783,48.677 cw(c70.783,48.78) 70.68,48.78 cw(c70.81,48.78) 70.81,48.91 70.84,48.91 ccw(c70.84,49.321) 71.251,49.321 71.251,50.072 71.867,50.688 80.701,50.688 82.902,52.889 82.902,55.242 83.123,55.463 83.497,55.463 83.697,55.263 83.697,54.693 J16.L6@83.87,54.52
ETH_A_D4_N: J2.15 J16.L7 | length 33.6
  Top Layer w0.12: J2.15@61.938,45.658 62.012,45.732 62.012,46.92 63.704,48.612 71.793,48.612 72.398,48.007 72.398,47.717 72.52,47.596 v1(72.52,47.52)
  Bottom Layer w0.12: v1(72.52,47.52) 72.52,47.444 72.398,47.323 72.398,47.133 72.721,46.81 73.251,46.81 73.5,47.059 73.5,47.863 73.899,48.262 80.414,48.262 85.185,53.034 85.185,56.995 J16.L7@85.14,57.04
ETH_A_D4_P: J2.13 J16.L8 | length 33.6
  Top Layer w0.12: J2.13@62.338,45.662 62.268,45.732 62.268,46.814 63.81,48.355 71.686,48.355 72.141,47.9 72.141,47.717 72.02,47.596 v1(72.02,47.52)
  Bottom Layer w0.12: v1(72.02,47.52) 72.02,47.444 72.141,47.323 72.141,47.026 72.615,46.553 73.357,46.553 73.757,46.953 73.757,47.757 74.005,48.005 80.52,48.005 85.442,52.928 85.442,55.242 85.663,55.463 86.037,55.463 86.237,55.263 86.237,54.693 J16.L8@86.41,54.52
ETH_B_D1_N: J2.25 J16.R1 | length 23.4
  Top Layer w0.12: v1(57.3,51.45) 57.376,51.45 57.497,51.572 58.397,51.572 60.012,49.957 60.012,45.732 J2.25@59.938,45.658
  Bottom Layer w0.12: v1(57.3,51.45) 57.243,51.45 57.121,51.572 56.834,51.572 56.553,51.852 56.553,52.376 56.864,52.687 57.527,52.687 ccw(c57.527,52.84) 57.68,52.84 57.68,53.307 cw(c58.05,53.307) 58.05,53.677 cw(c58.05,53.3) 58.427,53.3 58.427,52.503 ccw(c58.53,52.503) 58.53,52.4 ccw(c58.53,52.51) 58.64,52.51 58.64,53.377 cw(c58.99,53.377) 58.99,53.727 cw(c58.99,53.37) 59.347,53.37 59.347,53.023 ccw(c59.45,53.023) 59.45,52.92 59.51,52.92 ccw(c59.51,53.1) 59.69,53.1 59.69,53.496 60.506,54.313 60.829,54.313 63.353,54.313 63.595,54.555 63.595,56.995 J16.R1@63.55,57.04
ETH_B_D1_P: J2.23 J16.R2 | length 23.4
  Top Layer w0.12: v1(57.3,51.95) 57.376,51.95 57.497,51.829 58.503,51.829 60.268,50.063 60.268,45.732 J2.23@60.338,45.662
  Bottom Layer w0.12: v1(57.3,51.95) 57.243,51.95 57.121,51.829 56.94,51.829 56.81,51.959 56.81,52.27 56.97,52.43 57.527,52.43 ccw(c57.527,52.84) 57.937,52.84 57.937,53.307 cw(c58.05,53.307) 58.05,53.42 cw(c58.05,53.3) 58.17,53.3 58.17,52.503 ccw(c58.53,52.503) 58.53,52.143 ccw(c58.53,52.51) 58.897,52.51 58.897,53.377 cw(c58.99,53.377) 58.99,53.47 cw(c58.99,53.37) 59.09,53.37 59.09,53.023 ccw(c59.45,53.023) 59.45,52.663 59.51,52.663 ccw(c59.51,53.1) 59.947,53.1 59.947,53.39 60.613,54.056 63.459,54.056 63.852,54.449 63.852,55.292 64.06,55.5 64.46,55.5 64.697,55.263 64.697,54.643 J16.R2@64.82,54.52
ETH_B_D2_N: J2.29 J16.R3 | length 23.2
  Top Layer w0.12: v1(57.3,49.7) 57.376,49.7 57.497,49.821 58.287,49.821 59.211,48.897 59.211,46.613 59.212,45.732 J2.29@59.138,45.658
  Bottom Layer w0.12: v1(57.3,49.7) 57.224,49.7 57.103,49.821 56.814,49.821 56.593,50.042 56.593,50.568 56.941,50.917 57.717,50.917 ccw(c57.717,51.06) 57.86,51.06 57.86,51.157 cw(c58.25,51.157) 58.25,51.547 cw(c58.25,51.15) 58.647,51.15 58.647,50.393 ccw(c58.77,50.393) 58.77,50.27 ccw(c58.77,50.39) 58.89,50.39 58.89,50.767 cw(c59.19,50.767) 59.19,51.067 59.462,51.067 60.005,51.61 61.608,53.212 65.66,53.212 66.135,53.688 66.135,56.995 J16.R3@66.09,57.04
ETH_B_D2_P: J2.27 J16.R4 | length 23.3
  Top Layer w0.12: v1(57.3,50.2) 57.376,50.2 57.497,50.078 58.393,50.078 59.468,49.003 59.468,46.719 59.468,45.732 J2.27@59.538,45.662
  Bottom Layer w0.12: v1(57.3,50.2) 57.224,50.2 57.103,50.078 56.92,50.078 56.85,50.149 56.85,50.462 57.048,50.66 57.717,50.66 ccw(c57.717,51.06) 58.117,51.06 58.117,51.157 cw(c58.25,51.157) 58.25,51.29 cw(c58.25,51.15) 58.39,51.15 58.39,50.393 ccw(c58.77,50.393) 58.77,50.013 ccw(c58.77,50.39) 59.147,50.39 59.147,50.767 cw(c59.19,50.767) 59.19,50.81 59.569,50.81 60.262,51.503 61.714,52.955 65.766,52.955 66.392,53.581 66.392,55.292 66.6,55.5 67,55.5 67.237,55.263 67.237,54.643 J16.R4@67.36,54.52
ETH_B_D3_N: J2.33 J16.R5 | length 22.8
  Top Layer w0.12: v1(57.3,47.94) 57.376,47.94 57.502,48.067 57.982,48.067 58.412,47.637 58.412,45.732 J2.33@58.338,45.658
  Bottom Layer w0.12: v1(57.3,47.94) 57.224,47.94 57.098,48.067 56.814,48.067 56.593,48.287 56.593,48.916 56.914,49.237 57.82,49.237 cw(c57.82,48.83) 58.227,48.83 58.227,48.743 ccw(c58.33,48.743) 58.33,48.64 ccw(c58.33,48.75) 58.44,48.75 58.44,48.83 cw(c58.852,48.83) 58.852,49.242 59.338,49.242 62.308,52.212 66.913,52.212 68.675,53.974 68.675,56.995 J16.R5@68.63,57.04
ETH_B_D3_P: J2.31 J16.R6 | length 22.9
  Top Layer w0.12: v1(57.3,48.45) 57.376,48.45 57.502,48.323 58.088,48.323 58.668,47.743 58.668,45.732 J2.31@58.738,45.662
  Bottom Layer w0.12: v1(57.3,48.45) 57.224,48.45 57.098,48.323 56.92,48.323 56.85,48.394 56.85,48.81 57.02,48.98 57.82,48.98 cw(c57.82,48.83) 57.97,48.83 57.97,48.743 ccw(c58.33,48.743) 58.33,48.383 ccw(c58.33,48.75) 58.697,48.75 58.697,48.83 cw(c58.852,48.83) 58.852,48.985 59.444,48.985 62.414,51.955 67.02,51.955 68.932,53.868 68.932,55.292 69.14,55.5 69.54,55.5 69.777,55.263 69.777,54.643 J16.R6@69.9,54.52
ETH_B_D4_N: J2.37 J16.R7 | length 23.1
  Top Layer w0.12: v1(57.2,46.15) 57.252,46.15 57.379,46.277 57.543,46.277 57.612,46.209 57.612,45.732 57.54,45.66 J2.37@57.54,45.41
  Bottom Layer w0.12: v1(57.2,46.15) 57.124,46.15 56.998,46.277 56.714,46.277 56.493,46.497 56.493,47.086 56.643,47.237 56.698,47.292 56.849,47.442 59.338,47.442 62.858,50.962 67.802,50.962 71.17,54.33 J16.R7@71.17,57.04
ETH_B_D4_P: J2.35 J16.R8 | length 23.2
  Top Layer w0.12: v1(57.2,46.66) 57.252,46.66 57.379,46.534 57.65,46.534 57.868,46.315 57.868,45.732 57.94,45.66 J2.35@57.94,45.41
  Bottom Layer w0.12: v1@57.2,46.65 57.114,46.65 56.998,46.534 56.82,46.534 56.75,46.604 56.75,46.98 56.955,47.185 59.444,47.185 62.964,50.705 67.909,50.705 71.427,54.224 71.427,55.247 71.68,55.5 72.08,55.5 72.317,55.263 72.317,54.643 J16.R8@72.44,54.52
FRS_EN1: U29.C4 U30.1 | length 9.7
  Top Layer w0.1: v1(28.566,60.35) 28.59,60.35 U29.C4@28.59,58.82
  Int2 (Sign) w0.1: v1(28.566,60.35) 28.586,60.33 31.29,60.33 v1(32.84,58.78)
  Bottom Layer w0.1: U30.1@32.63,55.96 32.63,56.5 32.21,56.92 32.21,58.15 v1(32.84,58.78)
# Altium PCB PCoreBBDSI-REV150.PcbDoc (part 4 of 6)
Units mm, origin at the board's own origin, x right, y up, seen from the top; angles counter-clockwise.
Board outline 100 x 72 mm, 6 copper layers (Top Layer, Int1 (GND), Int2 (Sign), Int3 (Sign), Int4 (GND), Bottom Layer), stack 1.538 mm thick; 358 components, 405 nets, 1521 pads, 834 vias.
Unrouted connection lines stored in the file: 10.

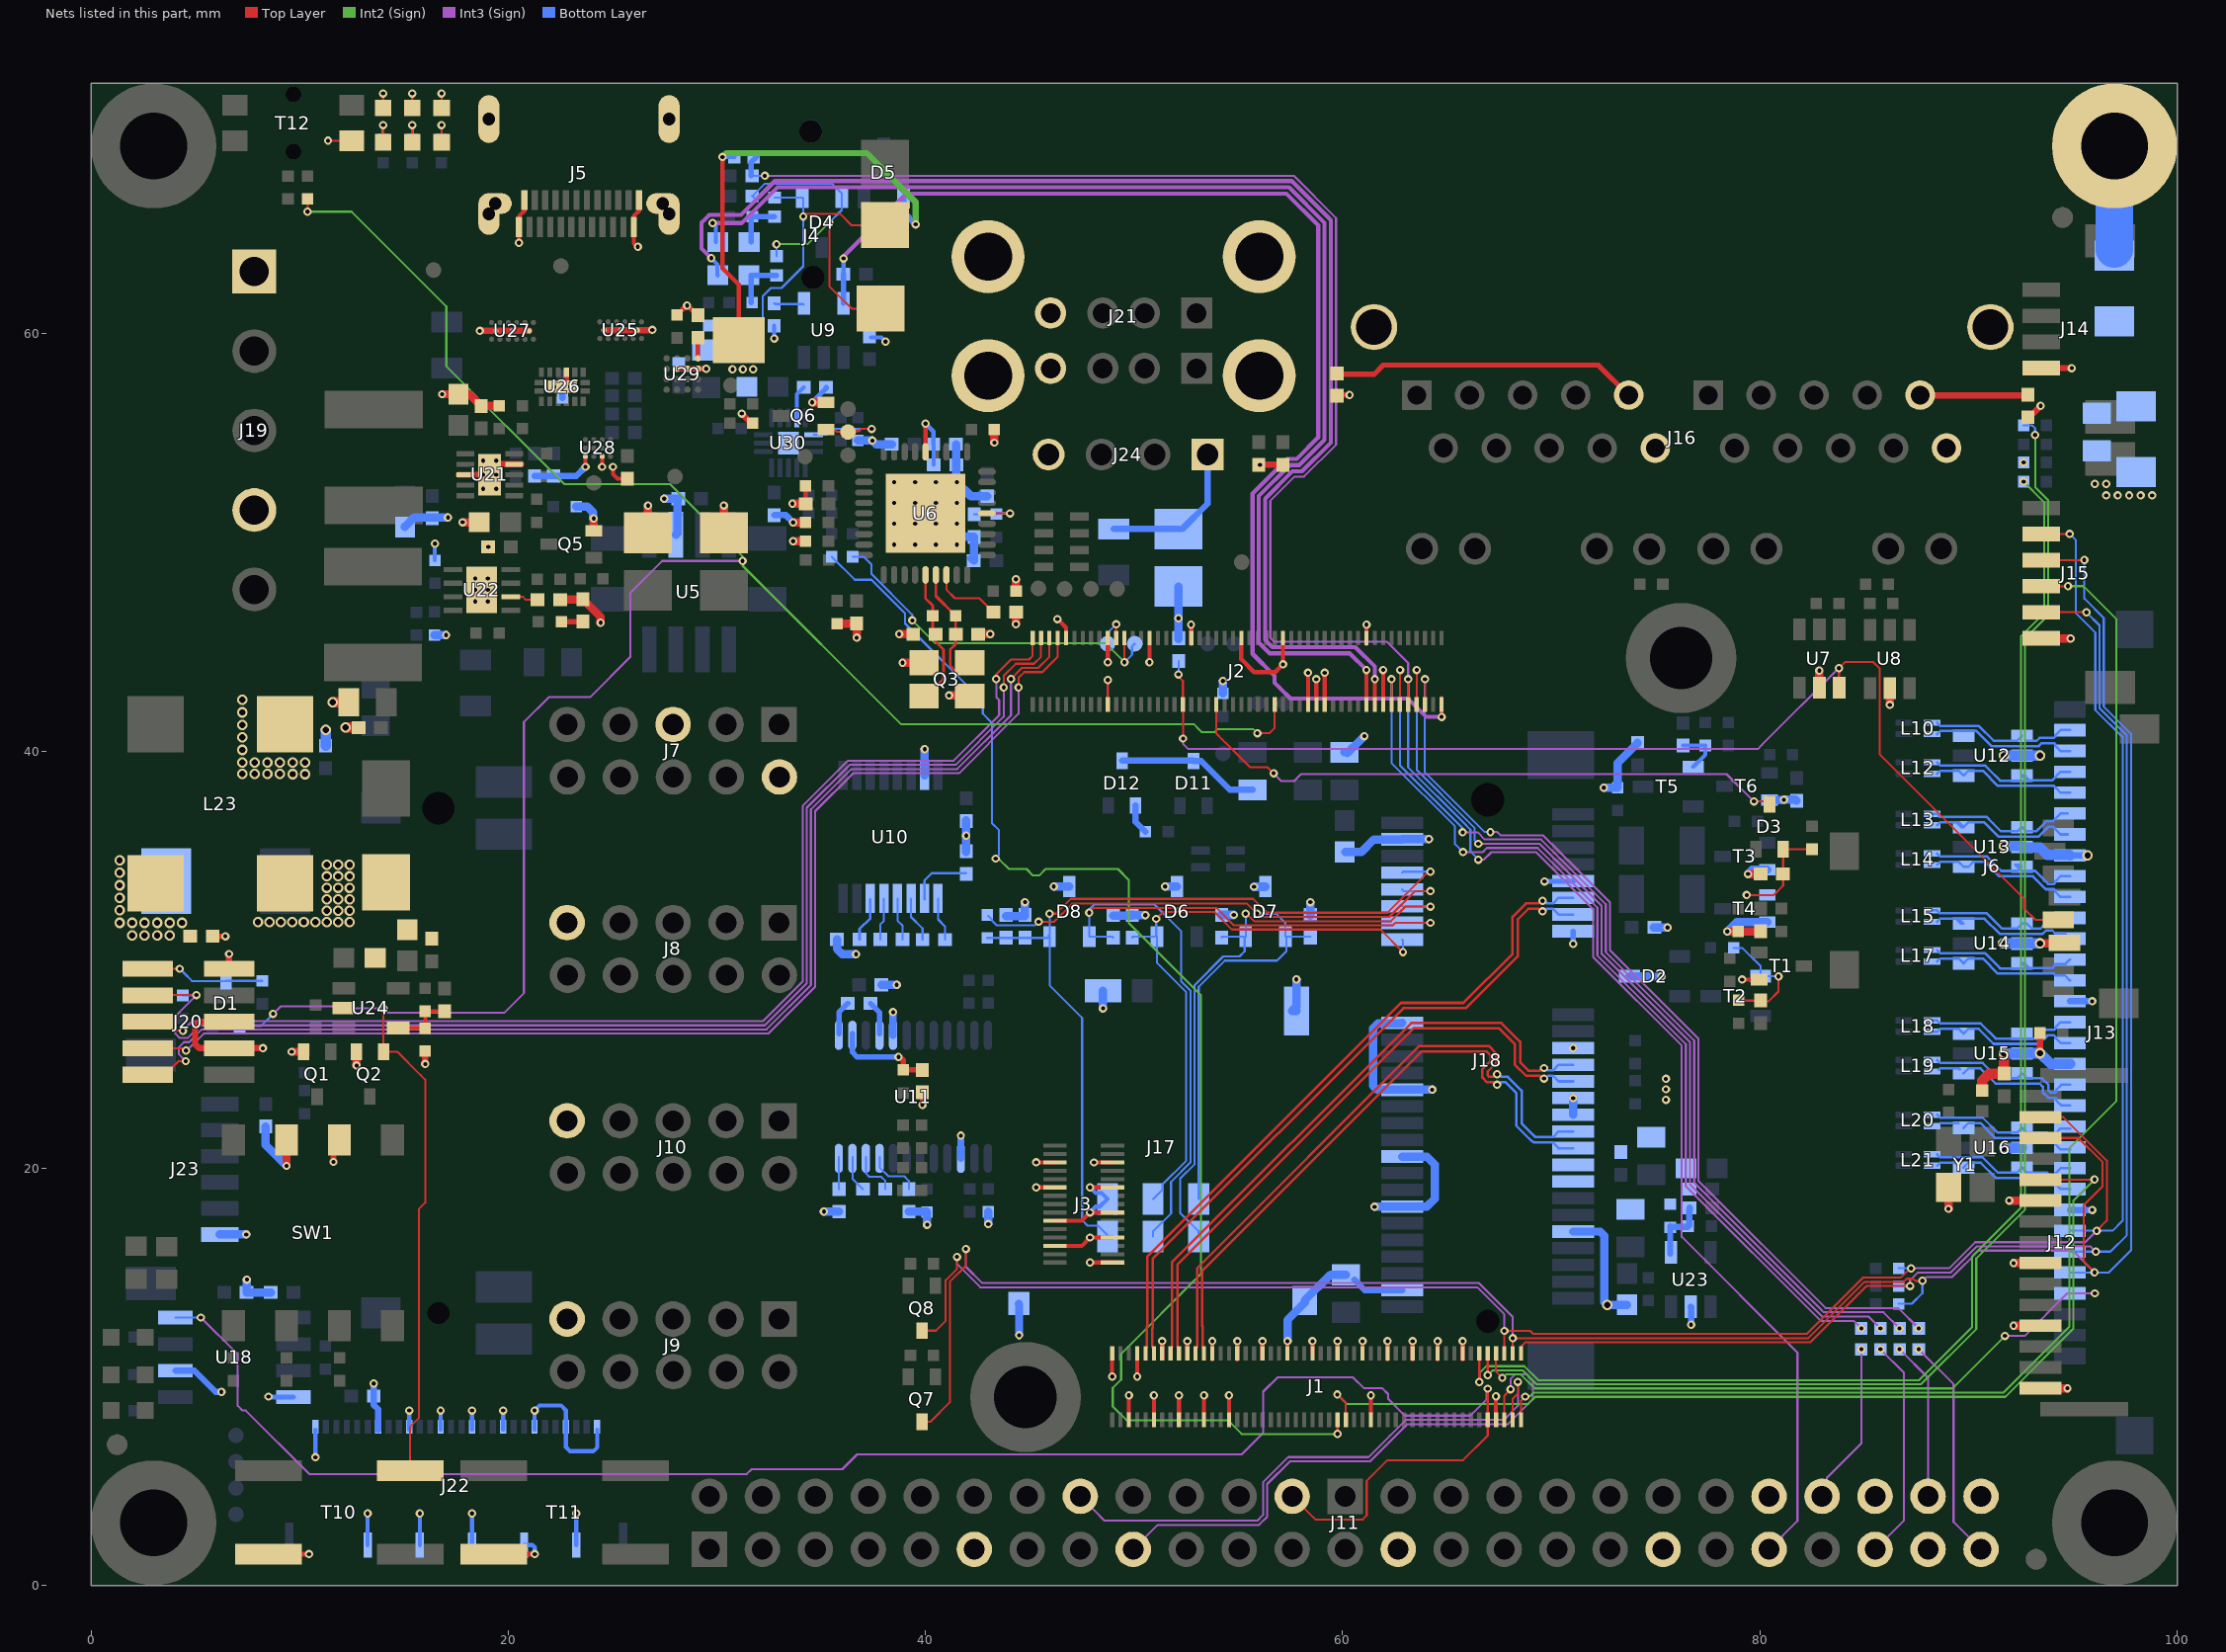
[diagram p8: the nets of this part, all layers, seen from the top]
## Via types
v1: diameter 0.4, hole 0.2, Top Layer to Bottom Layer, tented both sides, 706 vias
v2: diameter 0.5, hole 0.3, Top Layer to Bottom Layer, tented both sides, 102 vias
v3: diameter 0.4, hole 0.2, Top Layer to Bottom Layer, tented bottom, 16 vias
v4: diameter 0.9, hole 0.9, Top Layer to Bottom Layer, tented both sides, 6 vias
v5: diameter 0.5, hole 0.5, Top Layer to Bottom Layer, 2 vias
v6: diameter 3.2, hole 3.2, Top Layer to Bottom Layer, 2 vias

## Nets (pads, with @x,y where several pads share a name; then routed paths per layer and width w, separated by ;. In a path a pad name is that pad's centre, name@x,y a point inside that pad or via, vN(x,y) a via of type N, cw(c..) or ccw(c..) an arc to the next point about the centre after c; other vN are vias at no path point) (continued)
GND: C2.2 C3.1 C4.2 C5.2 C6.1 C7.1 C8.2 C9.1 C10.1 C11.1 C12.1 C13.1 C14.1 C15.1 C16.1 C17.1 C18.1 C19.1 C20.1 C22.1 C23.1 C25.1 C31.1 C32.1 C34.2 C35.2 C37.2 C39.2 C41.2 C42.2 C43.2 C45.1 C46.1 C47.1 C49.1 C50.2 C53.1 C54.1 C55.1 C56.1 C57.1 C58.1 C59.1 C60.1 C61.1 C62.1 C63.1 C64.1 C65.1 C66.1 C68.1 C69.2 C70.1 C71.1 C72.2 C75.1 C76.1 C77.1 C78.1 C79.1 C80.1 C81.1 C82.1 C83.1 C84.1 C86.1 C87.1 C88.1 C90.1 C91.1 C92.1 C97.1 C98.1 C99.1 C100.1 C101.1 C102.2 C103.1 C104.1 C105.1 C106.1 D2.3 D6.3 D7.3 D8.3 D13.1 D14.1 D15.1 J1.8 J1.15 J1.21 J1.27 J1.33 J1.38 J1.39 J1.45 J1.51 J1.57 J1.63 J1.69 J1.72 J1.75 J1.78 J1.81 J1.84 J1.87 J1.90 J1.93 J1.96 J1.99 J2.16 J2.19 J2.30 J2.32 J2.34 J2.39 J2.49 J2.61 J2.71 J2.81 J2.82 J2.91 J3.2 J3.5 J3.8 J3.11 J3.14 J3.19 J3.20 J3.25 J3.26 J5.A1 J5.A12 J5.B1 J5.B12 J6.6 J7.2 J7.5 J8.9 J9.9 J10.9 J11.11 J11.27 J11.37 J11.42 J11.46 J11.47 J11.50 J12.1 J12.4 J12.7 J12.10 J13.7 J13.14 J13.17 J13.24 J14.4 J15.6 J16.L10 J16.R10 J17.C5 J17.HD1 J17.HD2DSW1 J17.HD3 J17.HD4 J18.4 J18.9 J18.15 J18.18 J18.21 J18.26 J18.27 J18.29 J18.34 J18.35 J18.37 J18.40 J18.43 J18.50 J20.3 J20.5 J20.9 J21.A4 J21.B4 J22.1 J22.4 J22.7 J22.10 J22.13 J22.16 J22.19 J22.22 J22.28 J22.29 J22.30 J22.31 J22.32 J22.33 J23.6 J24.4 L23.3 Q1.2 Q2.2 Q3.2 Q3.4 Q5.2 Q6.2 R1.2 R13.1 R14.1 R15.1 R16.1 R17.1 R18.1 R19.1 R22.2 R25.1 R32.1 R36.1 R38.1 R49.1 R60.1 R67.1 R74.1 R77.1 R85.1 R88.1 R90.1 R91.1 R94.2 R96.1 R101.1 SW1.6 SW1.7 T1.2 T3.2 T4.2 T6.2 T10.3 T11.3 T12.3 U5.6 U6.37 U7.2 U8.2 U10.15 U11.5 U11.15 U12.2 U13.2 U14.2 U15.2 U16.2 U18.2 U18.8 U21.3 U21.9 U21.11 U22.9 U23.2 U24.2 U25.B1 U25.B2 U25.B3 U26.11 U26.17 U27.B1 U27.B2 U27.B3 U28.B3 U28.D3 U29.B3 U29.C3 U29.D3 U30.17 Y1.2 | length 264.1
  Top Layer w0.1: v1(11.36,69.25) T12.3@12.5,69.25 ; D15.1@14,70.75 D15.1@14,70.825 v1@14,71.45 ; D13.1@15.4,70.75 D13.1@15.4,70.825 v1@15.4,71.45 ; D14.1@16.8,70.75 D14.1@16.8,70.825 v1@16.8,71.45 ; J2.82@48.738,42.519 v1@48.738,43.398
  Top Layer w0.2: v1(20.51,64.36) 20.52,64.37 J5.A12@20.52,65.115 20.52,65.64 20.77,65.89 J5.B1@20.77,66.415 ; v1@23.7,53.732 U28.D3@23.7,54.12 ; v1@24.5,53.726 U28.B3@24.5,54.12 ; v1(25.02,53.62) 25.02,53.27 25.24,53.05 C101.1@25.71,53.05 ; v1(26.21,64.17) 26.184,64.17 26.02,64.334 J5.A1@26.02,65.115 26.02,65.64 26.27,65.89 J5.B12@26.27,66.415 ; R17.1@34.25,50.05 R17.1@34.3,50.05 ; R15.1@34.25,52.7 34.26,52.69 C13.1@34.26,51.85 ; R18.1@35.76,46.1 R18.1@35.77,46.11 ; v1(45.31,19.08) 45.314,19.076 J3.19@46.209,19.076 ; v1(45.31,20.28) 45.314,20.276 J3.25@46.209,20.276 ; J3.5@46.209,16.276 47.49,16.276 v1(47.89,16.676) J3.8@48.959,16.676 ; J3.11@46.209,17.476 47.486,17.476 v1(47.89,17.88) 47.894,17.876 J3.14@48.959,17.876 ; v1(46.33,46.32) 46.74,45.91 J2.91@46.74,45.41 ; v1(47.89,19.076) J3.20@48.959,19.076 ; v1@48.074,15.476 J3.2@48.959,15.476 ; v1(48.074,20.276) J3.26@48.959,20.276 ; v1@48.738,43.398 v1(48.74,43.4) ; v1(48.74,44.25) J2.81@48.74,45.19 ; J1.99@48.948,10.839 48.948,9.962 48.95,9.964 v1(48.95,10.01) ; J1.96@49.748,8.229 49.748,9.108 v1(49.75,9.11) ; J1.93@50.148,10.839 50.148,9.962 50.15,9.964 v1(50.15,10.01) ; J2.71@50.738,45.129 50.738,44.252 v1(50.74,44.25) ; J1.90@50.948,8.229 50.948,9.108 v1(50.95,9.11) ; J1.87@51.35,10.9 J1.87@51.35,11.12 v1@51.35,11.71 ; J1.84@52.148,8.229 52.148,9.108 v1(52.15,9.11) ; J1.81@52.55,10.9 J1.81@52.55,11.12 v1(52.55,11.71) ; J2.61@52.738,45.129 v1@52.738,46.05 ; J1.78@53.348,8.229 53.35,8.231 v1(53.35,9.11) ; J1.75@53.748,10.839 53.748,11.712 v1(53.75,11.71) ; J1.72@54.548,8.229 54.55,8.231 v1(54.55,9.11) ; J1.69@54.948,10.839 54.948,11.712 v1(54.95,11.71) ; J2.49@55.138,45.129 55.138,44.392 55.75,43.78 56.768,43.78 56.96,43.972 v1(57.138,44.15) J2.39@57.138,45.129 ; J1.63@56.15,10.9 J1.63@56.15,11.12 v1(56.15,11.71) ; J1.57@57.35,10.9 J1.57@57.35,11.12 v1(57.35,11.71) ; J2.34@58.338,42.519 58.338,42.791 ; 58.34,42.791 v1(58.34,43.75) ; J1.51@58.55,11.12 v1(58.55,11.71) ; J2.32@58.738,42.519 v1(58.738,43.44) ; J2.30@59.138,42.519 v1(59.138,43.75) ; J1.45@59.75,10.9 J1.45@59.75,11.12 v1(59.75,11.71) ; J1.39@60.95,10.9 v1(60.95,11.71) ; J2.19@61.138,45.129 61.138,46.048 v1(61.14,46.05) ; J1.38@61.348,8.229 61.348,9.108 v1(61.35,9.11) ; v1(61.938,43.88) 61.938,43.608 61.94,43.606 61.94,43.274 61.938,43.272 61.938,42.971 61.94,42.97 61.94,42.791 J2.16@61.94,42.23 ; J1.33@62.148,10.839 62.148,11.712 v1(62.15,11.71) ; J1.27@63.348,10.839 63.348,11.712 v1(63.35,11.71) ; J1.21@64.548,10.839 64.548,11.712 v1(64.55,11.71) ; J1.15@65.748,10.839 65.748,11.712 v1(65.75,11.71) ; J1.8@67.348,8.229 v1(67.348,9.063) v1@67.348,9.1 ; v1(79.15,29.04) T1.2@79.955,29.04
  Top Layer w0.25: U26.11@22.79,58.16 22.79,57.66 22.98,57.47 v1(22.98,57.46) ; U29.B3@28.09,58.32 U29.C3@28.59,58.32 U29.D3@29.09,58.32 v1(29.49,58.32)
  Top Layer w0.254: C70.1@5.83,31.12 5.84,31.11 v1@6.44,31.11 ; T10.3@8.5,1.5 v1(10.45,1.5) ; T11.3@19.3,1.5 v1(21.27,1.5) ; R91.1@28.09,60.9 28.545,61.355 v1(28.57,61.355) ; v1@28.57,61.35 28.6,61.35 29.06,60.89 C102.2@29.09,60.89 ; v1(39.85,23.04) C41.2@39.85,23.63 ; Q3.4@42.121,42.634 Q3.4@42.125,42.63 ; C54.1@59.73,57.06 v1(60.33,57.06)
  Top Layer w0.3: R25.1@93.42,26.48 93.425,26.475 93.425,25.515 v2(93.43,25.51)
  Top Layer w0.305: J20.5@6.62,27.02 5.17,27.02 4.99,26.84 4.99,25.95 5.19,25.75 J20.3@6.62,25.75 v1(8.24,25.75) ; J20.9@6.62,29.56 v1(6.62,30.27) ; v1(11.62,20.3) 11.62,21.06 SW1.6@11.91,21.35 ; v1(16.02,24.99) R88.1@16.02,25.61 ; U21.3@17.615,53.24 U21.3@17.94,53.24 v1(18.8,53.24) U21.11@19.11,53.24 19.61,53.74 U21.9@20.28,53.74 U21.9@20.605,53.74 ; v1(18.632,60.137) U27.B1@19.402,60.137 U27.B2@20.202,60.137 U27.B3@21.002,60.137 ; U25.B1@24.59,60.17 U25.B2@25.39,60.17 U25.B3@26.19,60.17 26.9,60.17 v1(26.91,60.18) ; v1(31.19,56.17) 31.645,55.715 R90.1@31.72,55.715 ; v1(56.032,53.72) C7.1@57.13,53.72 ; U7.2@82.85,43.03 U7.2@82.865,43.045 ; C53.1@92.85,56 92.85,56.02 93.008,56.177 93.098,56.177 v1(93.46,56.54) ; J14.4@93.59,58.355 94.945,58.355 v1(94.95,58.35) ; v1@94.885,45.395 v1(94.89,45.39)
  Top Layer w0.35: C83.1@12.36,42.33 C83.1@12.59,42.33
  Top Layer w0.4: v1(9.37,20.11) SW1.7@9.37,21.35 ; v1(9.62,25.58) 10.06,25.58 10.19,25.45 Q1.2@10.19,25.575 ; Q2.2@12.72,25.46 Q2.2@12.72,25.585 12.72,24.98 12.73,24.97 v1(12.73,24.92) ; v1(16.83,57.1) C75.1@17.614,57.1 18.144,57.1 C76.1@18.704,56.54 R67.1@19.574,56.54 ; v1(17.81,50.96) C79.1@18.61,50.96 ; C81.1@22.48,47.24 22.5,47.26 23.55,47.26 C84.1@23.57,47.28 ; C84.1@23.57,47.26 23.68,47.15 23.7,47.15 24.43,46.42 v1(24.43,46.15) ; Q5.2@24.095,50.56 v1@24.095,51.115 ; C5.2@26.7,50.455 v1(26.7,51.76) ; C4.2@30.33,50.455 v1(30.33,51.77) ; v1(33.62,51.85) C13.1@34.26,51.85 ; v1(33.66,50.05) R17.1@34.25,50.05 ; v1(33.66,50.95) R16.1@34.25,50.95 ; v1(34.57,56.71) Q6.2@35.225,56.71 ; R18.1@35.77,46.11 C10.1@36.7,46.11 v1(36.7,45.43) ; v1(38.74,45.6) C18.1@39.41,45.6 ; v1(38.901,44.234) Q3.2@39.921,44.234 ; v1(41.13,42.66) 42.095,42.66 Q3.4@42.121,42.634 ; C17.1@42.55,45.58 C17.1@42.53,45.6 v1(43.1,45.6) ; v1(43.3,54.78) R14.1@43.3,55.41 ; C16.1@44.266,46.576 C16.1@44.34,46.65 ; v1@44.34,46.11 C16.1@44.34,46.65 ; v1(44.34,48.23) 44.34,47.68 R13.1@44.35,47.67 ; C16.1@44.35,46.64 C16.1@44.34,46.65 ; v1(78.44,31.35) R19.1@78.96,31.35 80.02,31.35 C19.1@80.03,31.36 ; v1(79.43,34.1) C25.1@80.03,34.1 ; U7.2@82.85,43.03 v1(82.85,43.85) ; v1(86.231,42.209) U8.2@86.23,43.01 ; v1(89.04,18.05) 89.05,18.06 Y1.2@89.05,19.07 ; v1(91.95,18.45) J12.10@93.45,18.45 ; v1(92.16,12.45) J12.4@93.45,12.45 ; v1(92.16,15.45) J12.7@93.45,15.45 ; v2@93.43,30.78 94.58,30.78 J6.6@94.6,30.8 ; J12.1@93.45,9.45 v1(94.74,9.45) ; J15.6@93.59,45.395 v1@94.885,45.395
  Top Layer w0.406: U6.37@40,51.39 U6.37@40,51.4
  Top Layer w0.5: v2(11.59,42.33) C83.1@12.36,42.33 ; v2(12.2,41.12) C82.1@12.82,41.12 ; C68.1@90.65,23.72 90.65,24.2 90.98,24.53 C46.1@91.7,24.53 91.69,24.54 v2(91.69,25.5)
  Int3 (Sign) w0.1: v1(61.35,9.11) v1@61.45,9.01
  Bottom Layer w0.2: v1(10.76,6.14) J22.28@10.76,7.46 ; v1@13.25,3.45 13.26,3.44 J22.33@13.26,1.935 ; J22.19@15.26,7.46 J22.19@15.26,7.61 v1(15.26,8.385) ; J22.32@15.76,1.935 v1@15.76,3.44 ; R74.1@16.48,49.14 16.48,49.93 v1(16.49,49.94) ; J22.16@16.76,7.46 J22.16@16.76,7.61 v1(16.76,8.385) ; J22.31@18.26,1.935 v1@18.26,3.44 ; J22.13@18.26,7.46 J22.13@18.26,7.61 v1(18.26,8.385) ; J22.10@19.76,7.46 v1(19.76,8.385) ; J22.30@20.76,1.935 21.155,1.935 21.27,1.82 v1(21.27,1.5) ; J22.7@21.26,7.46 v1@21.26,8.33 ; v1(21.26,8.385) 21.495,8.62 22.53,8.62 22.76,8.39 J22.4@22.76,7.61 22.76,6.63 22.96,6.43 24.07,6.43 24.26,6.62 J22.1@24.26,7.46 ; J22.29@23.26,1.935 v1@23.26,3.44 ; v1(32.75,59.77) C32.1@32.75,60.38 ; C31.1@37.4,59.82 37.88,59.82 v1(38.08,59.62) ; v1(47.89,17.88) 48.164,18.154 48.354,18.154 J17.C5@48.72,18.52 48.438,18.802 48.164,18.802 v1(47.89,19.076) ; v1@57.113,44.125 v1(57.138,44.15) ; C64.1@60.225,39.805 60.51,40.09 60.51,40.185 C64.1@60.51,40.31
  Bottom Layer w0.25: v1(34.57,56.71) 35.24,57.38 C103.1@35.24,57.43
  Bottom Layer w0.254: v1(8.51,9.052) 8.537,9.025 U18.8@9.695,9.025 ; v1(69.676,33.746) 69.683,33.753 71.043,33.753 J18.9@71.05,33.76 ; v1(71.05,30.75) J18.15@71.05,31.36
  Bottom Layer w0.3: v1(13.55,9.68) C106.1@13.55,9.07 13.55,8.65 13.76,8.44 J22.22@13.76,7.61 J22.22@13.76,7.46
  Bottom Layer w0.305: U18.2@4.045,10.295 4.955,10.295 5.97,9.28 v1(6.25,9.28) ; C98.1@21.26,53.18 C97.1@22.17,53.18 23.26,53.18 v1(23.7,53.62) ; v1(22.2,57.46) 22.48,57.46 22.59,57.35 R96.1@22.59,56.92 ; C105.1@32.75,51.3 33.31,51.3 v1(33.66,50.95) ; C63.1@60.552,14.66 61.052,14.16 J18.50@62.85,14.16 ; U23.2@76.68,13.36 76.7,13.34 v1(76.7,12.5) ; J13.24@94.86,18 v1(95.93,18) ; J13.14@94.86,28 v1(95.93,28) ; J13.7@94.86,35 v2(95.71,35)
  Bottom Layer w0.35: U11.5@38.445,26.37 v1(38.445,27.48) ; U11.15@41.695,20.47 v1(41.695,21.56)
  Bottom Layer w0.4: J23.6@6.17,16.825 7.435,16.825 v1(7.44,16.82) ; v1(7.47,14.66) 7.46,14.65 C50.2@7.46,14.04 C49.1@8.62,14.04 ; C47.1@8.37,22 8.37,21.11 v1(9.37,20.11) ; C77.1@15.05,50.73 15.05,50.755 15.485,51.19 v1(17.11,51.19) ; R77.1@16.47,45.56 v1(17.02,45.56) ; R60.1@23.26,51.71 23.79,51.71 24.07,51.43 24.07,51.165 v1(24.095,51.14) ; v1(27.47,52.09) C3.1@28.15,52.09 28.15,52.04 28.118,52.008 28.118,51.333 U5.6@28.15,51.3 ; U5.6@28.035,50.36 28.118,50.443 U5.6@28.118,51.3 ; v1(35.13,17.92) C42.2@35.86,17.92 ; C37.2@35.76,30.97 35.76,30.51 36.01,30.26 v1(36.67,30.26) ; R94.2@36.75,54.88 v1(37.45,54.88) 37.63,54.7 C12.1@38.39,54.7 ; C39.2@37.89,28.79 v1(38.62,28.79) ; C43.2@39.2,17.92 40.06,17.92 R38.1@40.08,17.9 v1(40.08,17.29) ; U10.15@39.955,38.83 39.96,38.835 v1(39.96,40.09) ; C14.1@41.46,54.7 41.465,54.695 C15.1@41.465,53.729 ; C15.1@41.473,53.721 41.465,53.713 41.465,52.925 v3(41.5,52.89) 42.18,52.21 C11.1@42.96,52.21 ; v3(41.5,50.89) 41.5,50.65 41.89,50.26 C8.2@42.33,50.26 42.33,49.13 C9.1@42.32,49.12 C9.1@42.21,49.23 ; C35.2@41.95,35.15 C35.2@41.95,35.19 v1(41.95,35.94) C34.2@41.95,36.64 C34.2@41.95,36.68 ; v1(43.01,17.32) R36.1@43.01,17.91 ; J17.HD4@44.48,13.5 44.49,13.49 v1(44.49,11.99) ; C69.2@52.13,47.885 v1(52.13,46.36) C20.1@52.13,45.4 52.13,45.375 C20.1@52.137,45.367 ; R22.2@54.26,42.76 v1(54.26,43.35) ; v1(57.35,11.71) 57.35,12.72 58.18,13.55 J17.HD1@58.18,13.66 59.41,14.89 C63.1@60.16,14.89 ; C64.1@60.09,39.94 60.265,39.94 60.51,40.185 60.565,40.24 v1@61.035,40.71 ; C65.1@60.12,35.16 60.9,35.16 61.5,35.76 J18.4@62.85,35.76 62.86,35.77 v1(64.13,35.77) ; v1(61.53,18.15) 61.536,18.156 62.847,18.156 J18.40@62.85,18.16 64.04,18.16 64.41,18.53 64.41,20.18 64.034,20.556 62.854,20.556 J18.34@62.85,20.56 ; J18.18@62.85,26.96 62.84,26.95 61.7,26.95 61.45,26.7 61.45,23.95 61.64,23.76 J18.26@62.85,23.76 v1(64.29,23.76) ; J18.43@71.05,16.96 72.34,16.96 72.55,16.75 72.55,13.58 v2(72.68,13.45) C88.1@73.63,13.45 ; J18.29@71.05,22.56 v1(71.05,23.36) ; v1(72.52,38.24) R49.1@73.17,38.24 73.17,39.414 74.016,40.26 74.02,40.26 74.13,40.37 C23.1@74.13,40.39 ; D2.3@73.75,29.2 v1(75.28,29.2) ; C45.1@74.9,31.54 C45.1@74.94,31.54 v1(75.57,31.54) ; v1(78.44,31.35) 78.88,31.79 T4.2@80.355,31.79 ; v1(79.43,34.1) 79.63,34.3 T3.2@80.355,34.3 ; T6.2@80.455,37.65 81.14,37.65 v1(81.15,37.66) 81.71,37.66 C22.1@81.76,37.61
  Bottom Layer w0.406: C60.1@43.86,32.09 44.77,32.09 C59.1@44.77,32.13 v1(44.77,32.75) ; v1(46.15,33.5) D8.3@46.9,33.5 ; v1(48.51,27.66) J17.HD3@48.51,28.51 ; C56.1@49,32.1 49.92,32.1 C55.1@49.92,32.14 49.93,32.13 v1(50.54,32.13) ; v1(51.49,33.5) D6.3@52.05,33.5 ; C57.1@54.2,32.1 C57.1@54.2,32.14 v1(54.78,32.14) ; v1(55.75,33.49) 56.29,33.49 D7.3@56.3,33.5 ; J17.HD2DSW1@57.78,27.535 57.569,27.535 57.78,27.746 v1(57.78,29.05) ; C58.1@58.45,32.1 C58.1@58.45,32.14 v1(58.45,32.75)
  Bottom Layer w0.5: C71.1@11.25,40.25 v2(11.25,41.002) ; v2(91.658,30.77) U14.2@92.56,30.77 v2(93.43,30.77) ; v2(91.69,20.98) U16.2@92.56,20.98 ; v2(91.69,25.5) U15.2@92.56,25.5 92.57,25.51 v2(93.43,25.51) 93.94,25 J13.17@94.86,25 ; v2(91.69,35.452) 91.692,35.45 92.51,35.45 U13.2@92.56,35.4 92.583,35.377 93.423,35.377 93.775,35.025 94.835,35.025 J13.7@94.86,35 ; v2(91.69,39.77) U12.2@92.56,39.77 92.563,39.773 v2(93.433,39.773)
  other v1: 13.26,3.45 15.76,3.45 18.26,3.45 23.26,3.45 51.35,11.71 47.89,15.476 75.49,23.28 75.49,23.78 75.49,24.28 71.05,25.76 6.44,31.12 61.04,40.71 52.73,46.05 44.34,46.08 18.42,47.17 19.02,47.17 18.42,47.72 19.02,47.72 18.42,48.27 19.02,48.27 19.04,49.78 96.6,52.25 97.15,52.25 97.7,52.25 98.25,52.25 98.8,52.25 18.8,52.56 19.42,52.56 96.05,52.8 96.6,52.8 19.42,53.24 24.5,53.62 92.64,53.83 18.8,53.92 19.42,53.92 33.43,54.76 30.75,58.3 31.25,58.3 31.74,58.3 14,71.52 15.4,71.52 16.8,71.52
  other v2: 8,31.79 8.55,31.79 9.099,31.79 9.649,31.79 10.199,31.79 10.75,31.79 11.3,31.79 11.85,31.79 12.4,31.79 11.3,32.34 11.85,32.34 12.4,32.34 11.3,32.89 11.85,32.89 12.4,32.89 11.3,33.44 11.85,33.44 12.4,33.44 11.3,33.99 11.85,33.99 12.4,33.99 11.3,34.54 11.85,34.54 12.4,34.54
  other v3: 38.5,49.89 39.5,49.89 40.5,49.89 41.5,49.89 38.5,50.89 39.5,50.89 40.5,50.89 38.5,51.89 39.5,51.89 40.5,51.89 41.5,51.89 38.5,52.89 39.5,52.89 40.5,52.89
GND_SHIELD: C1.1 C2.1 J5.SH1 J5.SH2 J5.SH3 J5.SH4 J16.L15 J16.R15 J21.9 J21.10 J21.11 J21.12 R1.1
GNDIN: J19.1 J19.4 L23.4
  other v2: 9.665,38.89 10.265,38.89 7.25,38.9 7.85,38.9 8.45,38.9 9.05,38.9 7.25,39.45 7.85,39.45 8.45,39.45 9.05,39.45 9.665,39.44 10.265,39.44 7.25,40.05 7.25,40.65 7.25,41.25 7.25,41.85 7.25,42.45
GPIO_J1_44: J1.44 J12.11 | length 48.5
  Top Layer w0.1: v1(59.74,9.15) 60.15,8.74 60.15,8.501 60.15,8.231 J1.44@60.15,7.94 ; J12.11@93.45,19.45 96.03,19.45 v1(96.04,19.46)
  Int2 (Sign) w0.1: v1(59.74,9.15) 60.19,8.7 68.895,8.7 69.235,9.04 91.763,9.04 95.027,12.305 95.027,18.447 v1(96.04,19.46)
GPIO_J1_46: J1.46 R103.2 | length 65.8
  Top Layer w0.1: v1(59.75,7.26) J1.46@59.75,7.94
  Int2 (Sign) w0.1: v1(43.36,34.84) 43.417,34.783 43.557,34.783 44,34.34 44.845,34.34 45.155,34.03 45.445,34.03 45.755,34.34 49.224,34.34 49.75,33.814 49.75,31.752 53.2,28.301 53.2,14.924 49.38,11.104 49.38,9.866 48.977,9.463 48.977,8.58 49.637,7.92 54.49,7.92 55.15,7.26 v1(59.75,7.26)
  Bottom Layer w0.1: R103.2@35.51,49.31 36.61,48.21 37.408,48.21 39.02,46.598 39.02,46.11 42.75,42.38 42.75,41.785 43.19,41.345 43.19,36.541 43.51,36.221 43.51,35.012 43.36,34.862 v1(43.36,34.84)
I2C_B_SCL: J1.3 J12.13 J13.27 J15.3 Q7.3 R8.2 | length 119.9
  Top Layer w0.1: Q7.3@39.83,7.845 40.235,7.845 41.17,8.78 41.17,14.55 41.934,15.314 v1(41.934,16.13) ; J1.3@68.15,11.12 68.15,11.73 68.27,11.85 82.317,11.85 85.017,14.55 86.89,14.55 87.04,14.7 87.345,14.7 87.445,14.6 v1(87.79,14.6) ; J12.13@93.45,21.45 95.26,21.45 96.43,20.28 96.43,19.14 95.53,18.24 95.53,15.52 v1(96.04,15.01) ; J15.3@93.595,49.15 v1(95.55,49.15)
  Int3 (Sign) w0.1: v1(41.934,16.13) 41.934,15.276 42.72,14.49 66.537,14.49 68.15,12.877 v1(68.15,11.85) ; v1(87.79,14.6) 87.98,14.79 89.223,14.79 90.483,16.05 95,16.05 v1(96.04,15.01)
  Bottom Layer w0.1: R8.2@86.65,13.5 87.28,13.5 87.79,14.01 v1(87.79,14.6) ; J13.27@94.86,15 96.73,15 97.79,16.06 97.79,40.82 96.48,42.13 96.48,46.37 95.55,47.3 v1(95.55,49.15)
I2C_B_SDA: J1.5 J12.14 J13.25 J15.2 Q8.3 R9.2 | length 111
  Top Layer w0.1: Q8.3@39.83,12.215 40.505,12.215 40.97,12.68 40.97,14.633 41.51,15.173 v1(41.51,15.75) ; J1.5@67.75,10.841 v1(67.75,12.2) 68.005,12.2 68.295,12.2 68.99,12.2 69.14,12.05 82.234,12.05 84.934,14.75 86.75,14.75 87.2,15.2 v1(87.25,15.2) ; J12.14@93.45,22.45 94.543,22.45 96.63,20.363 96.63,17.49 v1(96.14,17) ; J15.2@93.59,50.395 93.595,50.4 v1(94.85,50.4)
  Int3 (Sign) w0.1: v1(41.51,15.75) 41.51,15.41 42.63,14.29 66.454,14.29 67.75,12.994 v1(67.75,12.2) ; v1(87.25,15.2) 89.067,15.2 90.317,16.45 95.59,16.45 v1(96.14,17)
  Bottom Layer w0.1: R9.2@86.65,15.2 v1(87.25,15.2) ; v1(94.85,50.4) 95.15,50.1 95.15,46.6 96.08,45.67 96.08,41.964 97.39,40.654 97.39,17.49 96.9,17 J13.25@94.86,17
I2S_B_RXC: J2.79 TP28.1 | length 1.8
  Top Layer w0.1: J2.79@49.14,45.41 v1(49.14,46.07)
  Bottom Layer w0.1: TP28.1@48.73,45.14 48.738,45.148 48.738,45.668 v1(49.14,46.07)
I2S_B_RXFS: J2.77 R102.2 TP27.1 | length 17.8
  Top Layer w0.1: v1@49.54,44.24 v1(49.54,44.25) J2.77@49.54,45.41
  Int2 (Sign) w0.1: v1(39.37,46.26) 40.46,45.17 48.62,45.17 v1(49.54,44.25)
  Bottom Layer w0.1: R102.2@36.51,49.31 37.05,49.31 37.41,48.95 37.41,48.491 39.37,46.531 v1(39.37,46.26) ; v1(49.54,44.25) 49.902,44.612 49.902,45.012 TP27.1@50.03,45.14
I\2\C\_\B\_\I\R\Q\: J1.1 J13.26 J15.5 R5.2 | length 66.7
  Top Layer w0.1: J1.1@68.55,10.841 68.55,11.45 68.75,11.65 82.4,11.65 85.1,14.35 v1(87.2,14.35) ; J15.5@93.595,46.65 v1(95.65,46.65)
  Int3 (Sign) w0.1: v1(87.2,14.35) 87.2,14.626 87.574,15 89.15,15 90.4,16.25 95.848,16.25 96.098,16 v1(96.1,16)
  Bottom Layer w0.1: R5.2@86.65,14.35 v1(87.2,14.35) ; J13.26@94.86,16 v1(96.1,16) 96.8,16 97.59,16.79 97.59,40.737 96.28,42.047 96.28,46.02 v1(95.65,46.65)
ILIM_5V_VBUS: Q6.1 TP8.1 U30.6 | length 5.2
  Top Layer w0.1: Q6.1@35.225,55.41 35.633,55.41 35.74,55.303 36.277,55.303 TP8.1@36.29,55.29 36.338,55.338 36.818,55.338 36.92,55.44 v1(37.42,55.44)
  Bottom Layer w0.1: U30.6@34.63,55.16 35.23,55.16 35.52,55.45 37.41,55.45 v1(37.42,55.44)
JTAG_TCK: J2.93 J20.4 | length 58
  Top Layer w0.1: J20.4@2.72,25.75 4.368,25.75 4.478,25.64 v1(4.55,25.64) ; v1(44.46,43.05) 44.46,43.51 44.73,43.78 45.6,43.78 46.338,44.518 46.338,44.849 J2.93@46.338,45.129
  Int3 (Sign) w0.1: v1(4.55,25.64) 4.59,25.64 5.4,26.45 32.463,26.45 34.71,28.697 34.71,37.111 36.531,38.932 41.606,38.932 44.46,41.786 v1(44.46,43.05)
JTAG_TDI: J2.97 J20.8 R7.1 | length 61.1
  Top Layer w0.1: J20.8@2.72,28.29 2.73,28.3 v1(5.05,28.3) ; v1(43.75,43.05) 43.75,43.305 43.75,43.6 44.33,44.18 44.53,44.18 ; 44.53,44.18 45.2,44.18 45.538,44.518 45.538,44.849 J2.97@45.538,45.129
  Int3 (Sign) w0.1: v1(5.05,28.3) 4.05,27.3 4.05,26.445 4.255,26.24 4.624,26.24 5.234,26.85 32.297,26.85 34.31,28.863 34.31,37.277 36.365,39.332 41.44,39.332 43.75,41.642 v1(43.75,43.05)
  Bottom Layer w0.1: R7.1@4.4,28.28 5.03,28.28 v1(5.05,28.3)
JTAG_TDO: J2.99 J20.6 | length 56.9
  Top Layer w0.1: J20.6@2.72,27.02 3.05,26.69 3.89,26.69 3.99,26.59 v1(4.4,26.59) ; v1@43.39,43.44 43.39,43.67 44.1,44.38 44.481,44.38 44.96,44.38 45.138,44.558 45.138,44.849 J2.99@45.138,45.129
  Int3 (Sign) w0.1: v1(4.4,26.59) 4.86,27.05 32.214,27.05 34.11,28.945 34.11,37.36 36.282,39.532 41.357,39.532 43.53,41.705 43.53,42.443 43.4,42.573 43.4,43.45 v1@43.39,43.44
  other v1: 43.39,43.45
JTAG_TMS: J2.95 J20.2 | length 58.9
  Top Layer w0.1: J20.2@2.72,24.48 3.54,24.48 4.19,25.13 v1(4.54,25.13) ; v1(44.1,43.45) 44.58,43.93 44.63,43.98 45.4,43.98 45.938,44.518 45.938,44.849 J2.95@45.938,45.129
  Int3 (Sign) w0.1: v1(4.54,25.13) 4.2,25.47 4.2,25.785 4.455,26.04 4.707,26.04 5.317,26.65 32.38,26.65 34.51,28.78 34.51,37.194 36.448,39.132 41.523,39.132 44.1,41.709 v1(44.1,43.45)
LACLK_N: J13.8 L14.3 U13.3 | length 8.2
  Bottom Layer w0.12: L14.3@88.495,35.085 88.642,34.938 88.947,34.938 88.949,34.94 90.883,34.94 91.576,34.247 92.357,34.247 U13.3@92.56,34.45 ; J13.8@94.86,34 94.41,34 94.17,33.76 94.17,33.699 94.1,33.629 93.811,33.629 93.192,34.247 92.538,34.247 92.448,34.338 U13.3@92.335,34.45 ; U13.3@92.335,34.45 U13.3@92.56,34.45 ; U13.3@92.335,34.45 92.25,34.535 92.475,34.535 U13.3@92.56,34.45
LACLK_P: J13.9 L14.2 U13.4 | length 7.3
  Bottom Layer w0.12: L14.2@88.495,34.535 88.642,34.682 89.053,34.682 89.055,34.683 89.527,34.683 U13.4@89.76,34.45 89.999,34.45 90.225,34.676 90.784,34.676 91.47,33.99 93.086,33.99 93.704,33.372 94.1,33.372 94.17,33.301 94.17,33.24 94.41,33 J13.9@94.86,33
LADATA0_N: J13.1 L10.3 U12.1 | length 6.8
  Bottom Layer w0.12: L10.3@88.495,41.355 88.642,41.208 90.485,41.208 91.206,40.487 92.327,40.487 U12.1@92.56,40.72 ; U12.1@92.793,40.487 93.265,40.487 93.407,40.629 94.1,40.629 94.17,40.699 94.17,40.76 94.41,41 J13.1@94.86,41
LADATA0_P: J13.2 L10.2 U12.6 | length 7
  Bottom Layer w0.12: L10.2@88.495,40.805 88.642,40.952 89.76,40.952 90.378,40.952 91.1,40.23 93.371,40.23 93.513,40.372 94.1,40.372 94.17,40.301 94.17,40.24 94.41,40 J13.2@94.86,40
LADATA1_N: J13.3 L12.3 U12.3 | length 7.7
  Bottom Layer w0.12: L12.3@88.495,39.455 88.585,39.365 88.64,39.31 90.788,39.31 90.939,39.159 91.518,38.58 92.79,38.58 92.912,38.58 92.672,38.82 U12.3@92.56,38.82 U12.3@92.79,38.59 ; U12.3@92.912,38.59 94,38.59 94.41,39 J13.3@94.86,39
LADATA1_P: J13.4 L12.2 U12.4 | length 7.1
  Bottom Layer w0.12: L12.2@88.495,38.905 88.643,39.053 89.527,39.053 U12.4@89.76,38.82 89.993,39.053 90.682,39.053 91.412,38.323 94.087,38.323 94.17,38.24 94.41,38 J13.4@94.86,38
LADATA2_N: J13.5 L13.3 U13.1 | length 7.4
  Bottom Layer w0.12: L13.3@88.245,36.985 88.495,36.985 88.585,36.895 88.585,36.886 88.624,36.847 90.855,36.847 91.171,36.532 91.555,36.147 92.357,36.147 U13.1@92.56,36.35 92.763,36.147 93.247,36.147 93.339,36.239 93.652,36.552 93.727,36.627 94.037,36.627 94.41,37 J13.5@94.76,37
LADATA2_P: J13.6 L13.2 U13.6 | length 7.6
  Bottom Layer w0.12: L13.2@88.495,36.435 88.643,36.583 U13.6@89.411,36.583 ; U13.6@89.527,36.583 U13.6@89.76,36.35 ; U13.6@89.527,36.59 89.411,36.59 89.651,36.35 U13.6@89.76,36.35 ; J13.6@94.76,36 94.41,36 94.04,36.37 93.833,36.37 93.353,35.89 92.657,35.89 91.449,35.89 90.749,36.59 90,36.59 U13.6@89.76,36.35
LADATA3_N: J13.10 L15.3 U14.1 | length 7.3
  Bottom Layer w0.12: L15.3@88.245,32.355 88.495,32.355 88.585,32.265 88.585,32.256 88.624,32.217 90.876,32.217 91.606,31.487 92.327,31.487 U14.1@92.56,31.72 92.796,31.72 93.025,31.491 93.095,31.491 ; 93.095,31.49 93.45,31.49 93.61,31.65 94.06,31.65 94.31,31.9 J13.10@94.86,31.9
LADATA3_P: J13.11 L15.2 U14.6 | length 7.7
  Bottom Layer w0.12: L15.2@88.495,31.805 88.643,31.953 U14.6@89.411,31.953 ; U14.6@89.527,31.953 U14.6@89.76,31.72 89.651,31.72 89.411,31.96 89.527,31.96 90.769,31.96 91.499,31.23 93.553,31.23 93.716,31.393 94.017,31.393 94.17,31.24 94.62,31.24 J13.11@94.86,31
LBCLK_N: J13.20 L20.3 U16.1 | length 7.2
  Bottom Layer w0.12: L20.3@88.495,22.565 88.642,22.418 88.947,22.418 88.949,22.42 90.68,22.42 91.4,21.7 92.33,21.7 U16.1@92.56,21.93 92.79,21.7 93.75,21.7 93.921,21.529 94.1,21.529 94.17,21.599 94.17,21.66 94.41,21.9 J13.20@94.86,21.9
LBCLK_P: J13.21 L20.2 U16.6 | length 6.6
  Bottom Layer w0.12: L20.2@88.642,22.162 89.053,22.162 ; 89.055,22.163 U16.6@89.527,22.163 ; U16.6@89.76,21.93 89.993,22.163 90.574,22.163 91.294,21.443 93.644,21.443 93.815,21.272 94.1,21.272 94.17,21.201 94.17,21.14 94.41,20.9 J13.21@94.86,20.9
LBDATA0_N: J13.12 L17.3 U14.3 | length 7.7
  Bottom Layer w0.12: L17.3@88.495,30.455 88.64,30.31 90.788,30.31 91.518,29.58 U14.3@92.79,29.58 ; U14.3@92.912,29.58 92.672,29.82 U14.3@92.56,29.82 92.79,29.59 92.912,29.59 94,29.59 94.17,29.76 94.203,29.793 94.653,29.793 J13.12@94.86,30
LBDATA0_P: J13.13 L17.2 U14.4 | length 7.1
  Bottom Layer w0.12: L17.2@88.495,29.905 88.643,30.053 89.527,30.053 U14.4@89.76,29.82 89.993,30.053 90.682,30.053 91.412,29.323 94.077,29.323 94.16,29.24 94.62,29.24 J13.13@94.86,29
LBDATA1_N: J13.15 L18.3 U15.1 | length 7.3
  Bottom Layer w0.12: L18.3@88.245,27.085 88.495,27.085 88.642,26.938 90.585,26.938 91.306,26.217 93.265,26.217 93.677,26.629 94.1,26.629 94.17,26.699 94.17,26.76 94.41,27 J13.15@94.86,27
LBDATA1_P: J13.16 L18.2 U15.6 | length 7.5
  Bottom Layer w0.12: L18.2@88.245,26.535 88.495,26.535 88.642,26.682 89.531,26.682 U15.6@89.626,26.586 ; U15.6@89.625,26.585 U15.6@89.76,26.45 89.992,26.682 90.478,26.682 91.2,25.96 93.371,25.96 93.783,26.372 94.1,26.372 94.17,26.301 94.17,26.24 94.41,26 J13.16@94.86,26
LBDATA2_N: J13.18 L19.3 U15.3 | length 7.6
  Bottom Layer w0.12: L19.3@88.495,25.185 88.642,25.038 88.947,25.038 88.949,25.04 90.68,25.04 91.41,24.31 92.32,24.31 U15.3@92.56,24.55 92.8,24.31 92.886,24.31 93.52,24.31 93.822,24.008 93.822,23.742 93.935,23.629 94.17,23.629 94.208,23.667 94.208,23.76 94.448,24 J13.18@94.86,24
LBDATA2_P: J13.19 L19.2 U15.4 | length 7.2
  Bottom Layer w0.12: L19.2@88.574,24.714 88.642,24.782 89.052,24.782 89.053,24.78 89.355,24.78 89.53,24.78 U15.4@89.58,24.73 ; U15.4@89.76,24.55 89.993,24.783 90.574,24.783 91.304,24.053 91.537,24.053 92.78,24.053 93.414,24.053 93.565,23.902 93.565,23.635 93.828,23.372 94.17,23.372 94.208,23.333 94.208,23.24 94.448,23 J13.19@94.86,23
LBDATA3_N: J13.22 L21.3 U16.3 | length 7.2
  Bottom Layer w0.12: L21.3@88.495,20.665 88.642,20.518 88.947,20.518 88.949,20.52 90.68,20.52 91.41,19.79 92.056,19.79 92.32,19.79 U16.3@92.56,20.03 92.8,19.79 93.206,19.79 93.76,19.79 93.921,19.629 94.1,19.629 94.17,19.699 94.17,19.76 94.41,20 J13.22@94.86,20
LBDATA3_P: J13.23 L21.2 U16.4 | length 6.8
  Bottom Layer w0.12: L21.2@88.495,20.115 88.642,20.262 89.053,20.262 89.055,20.263 U16.4@89.527,20.263 ; U16.4@89.76,20.03 89.993,20.263 90.574,20.263 91.304,19.533 91.537,19.533 93.654,19.533 93.815,19.372 94.1,19.372 94.17,19.301 94.17,19.24 94.41,19 J13.23@94.86,19
MPCIE_CLK_N: J1.91 J18.11 | length 33.1
  Top Layer w0.12: J1.91@50.548,11.368 50.622,11.442 50.622,12.429 50.627,12.435 50.627,15.755 62.798,27.925 65.789,27.925 68.141,30.277 68.141,32.045 68.292,32.195 68.634,32.538 68.785,32.688 69.383,32.688 69.504,32.81 v1(69.58,32.81)
  Bottom Layer w0.12: v1(69.58,32.81) 69.656,32.81 69.777,32.688 70.079,32.688 70.35,32.96 J18.11@71.05,32.96
MPCIE_CLK_P: J1.89 J18.13 | length 32.7
  Top Layer w0.12: J1.89@50.948,11.372 50.878,11.442 50.878,12.323 50.884,12.329 50.884,15.648 62.904,27.668 65.895,27.668 68.398,30.171 68.398,31.938 68.891,32.431 69.383,32.431 69.504,32.31 v1(69.58,32.31)
  Bottom Layer w0.12: v1(69.58,32.31) 69.656,32.31 69.777,32.431 70.079,32.431 70.35,32.16 J18.13@71.05,32.16
MPCIE_CRX_N: J1.85 J18.23 | length 29.9
  Top Layer w0.12: J1.85@51.748,11.368 51.822,11.442 51.822,12.323 51.817,12.327 51.817,15.485 63.288,26.955 67.607,26.955 68.506,26.057 68.506,25.076 68.903,24.678 69.453,24.678 69.574,24.8 v1(69.65,24.8)
  Bottom Layer w0.12: v1(69.65,24.8) 69.726,24.8 69.837,24.688 70.079,24.688 70.35,24.96 J18.23@71.05,24.96
MPCIE_CRX_P: J1.83 J18.25 | length 29.4
  Top Layer w0.12: J1.83@52.148,11.372 52.078,11.442 52.078,12.429 52.074,12.433 52.074,15.378 63.394,26.698 67.501,26.698 68.249,25.95 68.249,24.97 68.797,24.421 69.453,24.421 69.574,24.3 v1(69.65,24.3)
  Bottom Layer w0.12: v1(69.65,24.3) 69.726,24.3 69.857,24.431 70.079,24.431 70.35,24.16 J18.25@71.05,24.16
MPCIE_CTX_N: J1.79 J18.31 | length 30.4
  Top Layer w0.12: J1.79@52.948,11.368 53.022,11.442 53.022,12.323 53.016,12.329 53.016,15.196 63.674,25.854 67.001,25.854 67.36,25.495 67.36,25.049 66.95,24.638 66.95,24.449 67.02,24.379 67.203,24.379 67.324,24.5 v1(67.4,24.5)
  Bottom Layer w0.12: v1(67.4,24.5) 67.476,24.5 67.597,24.379 67.917,24.379 68.578,23.717 68.578,22.148 69.143,21.583 69.218,21.508 ccw(c69.265,21.554) 69.265,21.488 70.079,21.488 70.35,21.76 J18.31@71.05,21.76
MPCIE_CTX_P: J1.77 J18.33 | length 30
  Top Layer w0.12: J1.77@53.348,11.372 53.278,11.442 53.278,12.429 53.273,12.435 53.273,15.089 63.781,25.597 66.894,25.597 67.103,25.389 67.103,25.155 66.693,24.745 66.693,24.342 66.913,24.122 67.203,24.122 67.324,24 v1(67.4,24)
  Bottom Layer w0.12: v1(67.4,24) 67.476,24 67.597,24.122 67.811,24.122 68.321,23.611 68.321,22.041 68.961,21.401 69.037,21.326 ccw(c69.265,21.554) 69.265,21.231 70.079,21.231 70.35,20.96 J18.33@71.05,20.96
NetC1_2: C1.2 U4.1 | length 4.9
  Bottom Layer w1.778: C1.2@96.99,64.06 96.99,68.99 U4.1@97,69
NetC8_1: C8.1 R11.2 U6.5 | length 3
  Top Layer w0.1: U6.5@42.95,51.39 43.84,51.39 ; v1(44.05,51.39) 43.84,51.39 ; 43.84,51.39 43.78,51.39 43.84,51.39
  Bottom Layer w0.1: C8.1@42.33,51.34 43.14,51.34 43.39,51.34 43.44,51.39 v1(44.05,51.39)
NetC14_2: C14.2 C15.2 U6.14 | length 3.4
  Top Layer w0.2: U6.14@40,54.39 v1(40,55.69)
  Bottom Layer w0.2: v1(40,55.69) 40.38,55.31 C14.2@40.38,54.7 40.393,54.687 C15.2@40.393,53.721
NetC16_2: C16.2 U6.34 | length 3.4
  Top Layer w0.1: U6.34@41,48.39 41,47.73 41.41,47.32 42.59,47.32 C16.2@43.26,46.65
NetC17_2: C17.2 Q3.1 R12.1 U6.33 | length 6.1
  Top Layer w0.127: U6.33@40.5,48.44 40.5,47.426 R12.1@41.444,46.482 41.45,46.476 C17.2@41.45,45.6 41.45,45.13 41.18,44.86 41.18,44.09 41.421,43.849 41.806,44.234 Q3.1@42.121,44.234
NetC18_2: C18.2 Q3.3 R12.2 U6.32 | length 6.6
  Top Layer w0.127: Q3.3@39.921,42.634 40.034,42.634 40.87,43.47 40.87,44.85 40.48,45.24 40.48,45.59 C18.2@40.49,45.6 40.344,45.746 R12.2@40.344,46.482 40.344,46.976 40,47.32 U6.32@40,48.44
NetC20_2: C20.2 J2.64 J6.5 U7.3 | length 56.9
  Top Layer w0.1: v1(52.13,43.67) 52.13,43.587 52.121,43.579 52.34,43.36 52.34,42.791 52.34,42.521 J2.64@52.338,42.519 ; J2.64@52.34,42.23 52.35,42.24 52.35,42.507 v1(52.348,40.594) v1(52.348,40.594) ; U7.3@83.8,43.03 83.79,43.04 v1(83.79,43.97) 84.08,44.26 85.435,44.26 85.75,43.945 85.75,39.833 92.67,32.913 92.67,32.44 93.21,31.9 J6.5@94.3,31.9
  Top Layer w0.161: J2.64@52.338,42.519 J2.64@52.35,42.507
  Int3 (Sign) w0.1: v1(52.348,40.594) 52.348,40.342 52.6,40.09 56.734,40.09 ; 56.734,40.091 79.899,40.091 80.099,40.291 83.778,43.97 v1(83.79,43.97)
  Bottom Layer w0.1: v1@52.12,43.67 52.13,43.68 C20.2@52.13,44.32
NetC21_1: C21.1 R26.1 R28.2 T2.1 | length 5.8
  Top Layer w0.1: R26.1@79.02,28.03 80.01,28.03 80.04,28 80.42,28 80.89,28.47 v1(80.89,29.19)
  Bottom Layer w0.1: R28.2@78.74,30.56 79.15,30.56 79.69,30.02 79.7,30.02 80.04,29.68 T2.1@80.04,29.2 80.88,29.2 v1(80.89,29.19)
NetC24_1: C24.1 D4.2 J4.2 L5.1 | length 16.6
  Top Layer w0.1: v1(35.39,65.33) 35.39,62.27 36.46,61.2 J4.2@37.85,61.2
  Int2 (Sign) w0.1: v1(32.86,64.29) 34.35,64.29 v1(35.39,65.33)
  Bottom Layer w0.1: L5.1@32.86,63.715 v1(32.86,64.29) ; v1(35.39,65.33) 35.99,65.93 35.99,66.73 35.54,67.18 32.29,67.18 C24.1@31.71,66.6 ; C24.1@31.69,66.6 C24.1@31.71,66.6 ; C24.1@31.69,66.6 31.95,66.34 31.97,66.34 C24.1@31.71,66.6 ; C24.1@31.69,66.6 C24.1@31.71,66.6
NetC25_2: C25.2 D3.2 R29.1 T4.1 | length 6
  Top Layer w0.1: v1(79.37,33.09) 80.66,33.09 81.113,33.543 81.113,34.1 C25.2@81.11,34.1 D3.2@81.11,35.12 ; D3.2@81.11,35.295 82.495,35.295 R29.1@82.5,35.29 82.5,35.3 R29.1@82.45,35.35
  Bottom Layer w0.1: v1(79.37,33.09) T4.1@80.355,33.09
NetC26_1: C26.1 J2.18 | length 63.9
  Top Layer w0.2: J2.18@61.54,42.23 v1(61.54,43.44)
  Int3 (Sign) w0.2: v1(29.73,63.62) 29.26,64.09 29.26,65.326 29.634,65.7 31.16,65.7 32.78,67.32 44.604,67.32 57.556,67.32 59.43,65.446 59.43,54.784 58.046,53.4 57.586,53.4 56.28,52.094 56.28,45.324 56.624,44.98 60.604,44.98 61.538,44.046 61.538,43.442 v1(61.54,43.44)
  Bottom Layer w0.2: v1(29.73,63.62) 30.019,63.331 30.019,62.82 C26.1@30.04,62.8
NetC26_2: C26.2 L5.2 R30.1 | length 2.5
  Bottom Layer w0.254: R30.1@31.64,61.49 31.64,62.8 32.855,62.8 L5.2@32.86,62.805
NetC27_1: C27.1 J2.20 | length 60.6
  Top Layer w0.2: v1@61.138,43.74 61.138,42.541 61.14,42.539 J2.20@61.14,42.23
  Int3 (Sign) w0.2: v1(29.8,65.3) 31.184,65.3 32.904,67.02 44.728,67.02 57.432,67.02 59.13,65.322 59.13,54.908 57.922,53.7 57.462,53.7 55.98,52.218 55.98,45.2 56.5,44.68 60.338,44.68 v1(61.138,43.88)
  Bottom Layer w0.2: v1(29.8,65.3) 29.95,65.15 C27.1@29.95,64.4
NetC27_2: C27.2 L6.2 R31.2 | length 2.3
  Bottom Layer w0.254: C27.2@31.65,64.4 31.65,65.62 32.763,65.62 32.768,65.615 L6.2@32.77,65.615
NetC28_2: C28.2 D4.1 J4.3 L6.1 | length 13.1
  Top Layer w0.1: v1(34.14,65.62) 34.27,65.75 35.9,65.75 36.45,65.2 J4.3@38.05,65.2
  Bottom Layer w0.1: C28.2@31.64,60.48 32.03,60.48 32.2,60.65 32.2,61.8 32.59,62.19 33.1,62.19 34.14,63.23 v1(34.14,65.62) 34.14,66.48 D4.1@34.09,66.53 34.085,66.525 L6.1@32.77,66.525
NetC29_2: C29.2 J2.10 J11.41 L7.2 | length 112.5
  Top Layer w0.1: J2.10@63.13,42.511 63.138,42.519 63.14,42.517 v1(63.14,43.44)
  Int3 (Sign) w0.1: v1(32.3,67.57) 57.66,67.57 59.68,65.55 59.68,54.68 58.15,53.15 57.69,53.15 56.53,51.99 56.53,45.428 56.728,45.23 62.13,45.23 63.14,44.22 v1(63.14,43.44) ; v1(66.5,34.79) 66.77,34.79 67.13,35.15 69.267,35.15 72.01,32.407 72.01,30.11 76.25,25.87 76.25,16.747 76.25,16.708 81.8,11.158 81.8,3.09 J11.41@80.44,1.73
  Bottom Layer w0.1: C29.2@31.65,67.57 v1(32.3,67.57) ; v1(63.14,43.44) 63.14,39.216 63.138,39.214 65.8,36.552 ; 65.8,36.551 66.12,36.231 66.12,35.295 66.12,35.18 66.5,34.8 v1(66.5,34.79)
  Bottom Layer w0.254: C29.2@31.65,67.57 31.65,68.22 31.827,68.397 L7.2@31.9,68.47
NetC30_2: C30.2 J2.2 U9.5 | length 60.4
  Top Layer w0.2: J2.2@64.738,42.519 64.74,42.517 v1(64.74,41.63)
  Int3 (Sign) w0.2: v1(36.07,63.61) 36.07,63.71 38.93,66.57 38.954,66.57 39.104,66.72 57.304,66.72 58.83,65.194 58.83,64.95 58.83,55.032 57.798,54 57.338,54 55.68,52.342 55.68,44.654 56.738,43.596 56.738,43.274 56.972,43.04 57.503,42.51 63.124,42.51 64.004,41.63 v1(64.74,41.63)
  Bottom Layer w0.1: C30.2@36.06,62.85 C30.2@36.07,62.85
  Bottom Layer w0.2: C30.2@36.07,62.85 v1(36.07,63.61)
  Bottom Layer w0.254: C30.2@36.07,62.85 36.07,62.61 36.07,61.48 36.075,61.475 U9.5@36.075,61.46
NetC32_2: C32.2 U9.4 | length 1.5
  Bottom Layer w0.1: C32.2@32.75,61.46 32.79,61.42 34.13,61.42 U9.4@34.17,61.38
NetC33_1: C33.1 U10.3 | length 2.2
  Bottom Layer w0.1: U10.3@39.305,32.93 39.305,32.045 39.86,31.49 C33.1@39.86,30.96
NetC33_2: C33.2 U10.1 | length 2.1
  Bottom Layer w0.1: U10.1@40.605,32.93 40.605,31.925 40.94,31.59 C33.2@40.94,30.96
NetC35_1: C35.1 U10.2 | length 3.1
  Bottom Layer w0.1: U10.2@39.955,32.88 39.955,33.795 40.3,34.14 41.94,34.14 C35.1@41.95,34.15
NetC36_1: C36.1 U10.5 | length 2
  Bottom Layer w0.1: C36.1@37.83,30.97 37.83,31.68 38.005,31.855 U10.5@38.005,32.93
NetC36_2: C36.2 U10.4 | length 2.1
  Bottom Layer w0.1: U10.4@38.655,32.93 38.655,31.875 38.91,31.62 C36.2@38.91,30.97
NetC37_1: C37.1 U10.6 | length 2.1
  Bottom Layer w0.127: C37.1@36.84,30.97 36.84,31.47 37.355,31.985 U10.6@37.355,32.88
NetC38_1: C38.1 U11.4 | length 1.6
  Bottom Layer w0.254: C38.1@37.36,27.9 37.805,27.455 U11.4@37.805,26.44
NetC38_2: C38.2 U11.1 | length 1.6
  Bottom Layer w0.254: U11.1@35.855,26.44 35.855,27.475 C38.2@36.28,27.9
NetC40_1: C40.1 U11.22 | length 2.3
  Bottom Layer w0.1: U11.22@37.155,20.54 37.155,19.745 37.31,19.59 37.87,19.59 38.08,19.38 C40.1@38.08,19
NetC40_2: C40.2 U11.23 | length 1.7
  Bottom Layer w0.1: U11.23@36.505,20.54 36.505,19.495 C40.2@37,19
NetC41_1: C41.1 R33.2 U11.2 | length 4.8
  Top Layer w0.254: v1(38.71,25.33) 38.78,25.33 38.94,25.17 R33.2@38.94,24.71 C41.1@39.85,24.71
  Bottom Layer w0.254: U11.2@36.505,26.44 36.505,25.555 36.73,25.33 v1(38.71,25.33)
NetC42_1: C42.1 U11.24 | length 1.5
  Bottom Layer w0.1: U11.24@35.855,20.54 35.855,19.005 C42.1@35.86,19
NetC43_1: C43.1 U11.21 | length 2.6
  Bottom Layer w0.1: U11.21@37.805,20.54 37.805,20.025 38.22,19.61 38.98,19.61 39.2,19.39 C43.1@39.2,19
NetC44_1: C44.1 R47.2 T5.1 | length 2.3
  Bottom Layer w0.2: C44.1@76.32,40.26 R47.2@77.38,40.26 77.38,39.82 T5.1@76.8,39.24
NetC48_1: C48.1 J11.44 | length 7.8
  Int3 (Sign) w0.1: J11.44@82.98,4.27 83.208,4.498 83.208,5.148 84.86,6.8 v1(84.86,11.32)
NetC48_2: C48.2 J2.14 | length 44.7
  Top Layer w0.1: J2.14@62.338,42.519 J2.14@62.34,42.517 ; v1(62.34,43.44) J2.14@62.34,42.517 ; J2.14@62.34,42.517 62.35,42.507 J2.14@62.34,42.517
  Int3 (Sign) w0.1: v1(65.77,35.15) 66.71,35.15 66.91,35.35 69.35,35.35 72.21,32.49 72.21,30.193 76.45,25.953 76.45,19.141 82.911,12.68 84.5,12.68 v1(84.86,12.32)
  Bottom Layer w0.1: v1(62.34,43.44) 62.34,39.43 65.38,36.39 65.38,35.54 v1(65.77,35.15)
NetC51_1: C51.1 J2.8 | length 45.2
  Top Layer w0.1: J2.8@63.538,42.519 63.55,42.531 63.55,43.44 v1(63.55,43.88)
  Int3 (Sign) w0.1: v1(66.5,35.55) 69.433,35.55 72.41,32.573 72.41,30.276 76.65,26.036 76.65,19.224 82.984,12.89 85.207,12.89 v1(85.777,12.32)
  Bottom Layer w0.1: v1(63.55,43.88) 63.55,43.44 63.55,39.085 66,36.635 66.32,36.314 66.32,35.73 v1(66.5,35.55)
NetC51_2: C51.2 J11.45 | length 10.6
  Int3 (Sign) w0.1: J11.45@85.52,1.73 86.91,3.12 86.91,10.187 v1(85.777,11.32)
NetC52_1: C52.1 J11.48 | length 7.6
  Int3 (Sign) w0.1: v1(86.693,11.32) 88.06,9.953 J11.48@88.06,4.27
NetC52_2: C52.2 J2.12 | length 46.5
  Top Layer w0.1: J2.12@62.738,42.519 62.75,42.531 v1(62.75,43.88)
  Int3 (Sign) w0.1: v1(65.75,36.1) 66.47,36.1 66.81,35.76 69.506,35.76 72.61,32.656 72.61,30.359 76.85,26.119 76.85,19.307 82.937,13.22 83.061,13.096 85.918,13.096 v1(86.693,12.32)
  Bottom Layer w0.1: v1(62.75,43.88) 62.75,39.31 65.75,36.31 v1(65.75,36.1)
NetC53_2: C53.2 J16.L9 | length 5.2
  Top Layer w0.305: J16.L9@87.68,57.04 C53.2@92.85,57.04
NetC54_2: C54.2 J16.R9 | length 14.8
  Top Layer w0.254: C54.2@59.73,58.06 61.51,58.06 61.95,58.5 72.25,58.5 J16.R9@73.71,57.04
NetC55_2: C55.2 D6.2 J17.C6 J18.16 | length 29.3
  Top Layer w0.1: v1(51.06,31.95) 51.39,32.28 53.85,32.28 54.69,31.44 61.81,31.44 v1(62.89,30.36)
  Bottom Layer w0.1: C55.2@49.92,31.06 49.92,31.1 D6.2@51.05,31.1 ; J17.C6@50.91,18.52 51.36,18.97 51.36,19.22 52.5,20.36 52.5,28.437 51.1,29.837 D6.2@51.1,31.1 51.09,31.11 51.06,31.11 v1(51.06,31.95) ; J18.16@62.85,30.96 62.89,30.92 v1(62.89,30.36)
NetC56_2: C56.2 D8.1 J17.C2 J18.14 | length 41.3
  Top Layer w0.1: v1(47.85,32.25) 48.08,32.48 50.685,32.48 ; 50.685,32.48 53.945,32.48 54.785,31.64 62.403,31.64 62.523,31.76 v1(64.2,31.76)
  Bottom Layer w0.1: C56.2@49,31.06 48.96,31.1 D8.1@47.85,31.1 v1(47.85,32.25) 47.85,32.4 48.09,32.64 50.977,32.64 52.25,31.367 52.25,28.97 52.7,28.52 52.7,20.277 51.77,19.347 51.77,17.83 50.91,16.97 J17.C2@50.91,16.72 ; J18.14@62.85,31.76 v1(64.2,31.76)
NetC57_2: C57.2 D7.2 J17.C3 J18.12 | length 29.4
  Top Layer w0.1: v1@55.35,32.175 55.42,32.175 55.755,31.84 62.31,31.84 63.01,32.54 v1(64.2,32.54)
  Bottom Layer w0.1: J17.C3@53.1,16.72 53.1,16.97 52.65,17.42 52.633,17.42 52.243,17.81 52.202,17.852 52.202,19.496 52.9,20.194 52.9,28.78 54.27,30.15 55.05,30.15 55.3,30.4 55.3,31.1 54.2,31.1 C57.2@54.2,31.06 ; D7.2@55.35,31.1 v1(55.35,32.2) ; J18.12@62.85,32.56 62.87,32.54 v1(64.2,32.54)
NetC58_2: C58.2 D7.1 J17.C7 J18.10 R54.2 | length 43.1
  Top Layer w0.1: v1(45.42,31.81) 46.16,31.81 47.03,32.68 50.768,32.68 55.41,32.68 v1(55.89,32.2) 55.934,32.2 56.089,32.045 62.228,32.045 63.463,33.28 v1(64.2,33.28)
  Bottom Layer w0.1: R54.2@43.01,32.09 43.185,31.915 43.185,31.865 43.4,31.65 45.26,31.65 v1(45.42,31.81) ; J17.C7@53.1,18.52 53.1,28.697 54.353,29.95 56.85,29.95 57.3,30.4 57.3,31.1 C58.2@58.45,31.1 ; v1(55.89,32.2) 56.81,32.2 57.25,31.76 D7.1@57.25,31.1 ; J18.10@62.85,33.36 62.93,33.28 v1(64.2,33.28)
NetC59_2: C59.2 C60.2 D8.2 J17.C1 J18.8 R54.1 | length 41
  Top Layer w0.1: v1(45.95,32.2) 46.26,32.2 46.97,32.91 55.71,32.91 56.375,32.245 62.145,32.245 64.06,34.16 64.15,34.16 v1(64.2,34.21)
  Bottom Layer w0.1: R54.1@42.96,31.04 43.86,31.04 44.77,31.04 45.89,31.04 D8.2@45.95,31.1 ; v1(45.95,32.2) 45.95,31.2 45.9,31.15 D8.2@45.95,31.1 ; J17.C1@48.72,16.72 48.72,16.798 48.27,17.248 47.772,17.248 47.51,17.51 47.51,23.279 47.51,27.2 45.95,28.76 D8.2@45.95,31.1 ; J18.8@62.85,34.16 62.9,34.21 v1(64.2,34.21)
NetC67_1: C67.1 J2.6 | length 45.4
  Top Layer w0.1: 63.94,42.791 63.95,42.801 v1@63.95,43.44 ; J2.6@63.95,42.507 63.95,42.791
  Int3 (Sign) w0.1: v1(67.08,36.11) 67.41,36.11 67.56,35.96 69.589,35.96 72.81,32.739 72.81,30.442 77.05,26.202 77.05,19.39 83.144,13.296 86.634,13.296 v1(87.61,12.32)
  Bottom Layer w0.1: v1(63.94,43.44) 63.94,38.978 66.2,36.718 66.807,36.11 v1(67.08,36.11)
NetC67_2: C67.2 J11.49 | length 10.8
  Int3 (Sign) w0.1: v1(87.61,11.32) 89.28,9.65 89.28,3.05 J11.49@90.6,1.73
NetC69_1: C69.1 F3.2 J24.1 | length 7.4
  Bottom Layer w0.3: F3.2@49.03,50.64 52.125,50.64 C69.1@52.13,50.635 52.305,50.635 53.52,51.85 J24.1@53.52,54.21
NetC70_2: C70.2 D9.2 L23.2
  other v2: 1.97,31.16 2.57,31.16 3.17,31.16 3.77,31.16 1.37,31.76 1.97,31.76 2.57,31.76 3.17,31.76 3.77,31.76 4.37,31.76 1.37,32.36 1.37,32.96 1.37,33.56 1.37,34.16 1.37,34.76
NetC81_2: C81.2 U22.2 | length 1.3
  Top Layer w0.1: U22.2@20.12,47.39 20.125,47.385 20.5,47.385 20.705,47.385 20.85,47.24 C81.2@21.4,47.24
NetC84_2: C84.2 R75.1 | length 1
  Top Layer w0.254: R75.1@22.54,46.2 C84.2@23.57,46.2
NetC85_1: C85.1 R84.1 R85.2 U23.4 | length 3.1
  Bottom Layer w0.305: U23.4@75.7,15.9 75.7,17.22 75.725,17.195 76.545,17.195 76.615,17.265 76.615,17.983 76.63,17.998 C85.1@76.63,18.1
NetC89_1: C89.1 R87.1 R88.2 U24.4 | length 3
  Top Layer w0.2: U24.4@14.72,26.72 16.01,26.72 R88.2@16.02,26.71 R87.1@16.02,27.52 16.94,27.52 C89.1@16.95,27.53
NetC102_1: C102.1 U29.D4 | length 1
  Top Layer w0.2: U29.D4@29.09,58.82 C102.1@29.09,59.81
NetC103_2: C103.2 U30.4 | length 1.6
  Bottom Layer w0.2: U30.4@33.83,55.96 33.83,57.1 C103.2@34.16,57.43
NetD1_1: D1.1 J2.42 Q2.1 R69.2 T10.2 | length 127.7
  Top Layer w0.1: v1(10.38,65.85) R69.2@10.38,66.46 ; v1(14.03,27.66) 14.02,27.65 14.02,26.358 Q2.1@14.02,25.585 14.675,25.585 15.8,24.46 16.02,24.24 16.02,18.345 15.71,18.035 15.71,8.02 15.3,7.61 T10.2@15.3,5.5 ; v1(55.91,40.85) 56.485,40.85 56.555,40.92 56.56,40.92 56.738,41.098 J2.42@56.738,42.519
  Int2 (Sign) w0.1: v1@10.27,65.85 12.487,65.85 17.03,61.307 17.03,59.415 17.03,59.125 17.03,58.444 22.684,52.79 27.762,52.79 31.214,49.338 31.214,49.126 v1(31.23,49.11) 31.23,48.881 38.821,41.29 52.86,41.29 53.15,41 53.241,40.909 53.862,40.909 53.993,41.04 55.72,41.04 v1(55.91,40.85)
  Int3 (Sign) w0.1: v1(8.73,27.4) 9.09,27.76 11.854,27.76 11.954,27.66 v1(14.03,27.66) 14.23,27.46 19.82,27.46 20.75,28.39 20.75,41.387 21.943,42.58 23.917,42.58 25.85,44.513 25.85,47.58 27.38,49.11 v1(31.23,49.11)
  Bottom Layer w0.1: D1.1@7.12,26.825 8.155,26.825 v1(8.73,27.4)
NetD1_3: D1.3 J20.10 R6.1 | length 5.7
  Top Layer w0.1: J20.10@2.72,29.56 v1(4.25,29.56)
  Bottom Layer w0.1: v1(4.25,29.56) 4.466,29.344 4.835,28.975 D1.3@6.47,28.975 6.475,28.98 R6.1@8.21,28.98
NetD3_3: D3.3 J2.56 | length 29.8
  Top Layer w0.1: J2.56@53.938,42.519 53.938,40.84 54.24,40.538 54.445,40.333 55.555,39.222 56.398,39.222 v1(56.69,38.93) ; v1(79.713,37.583) 80.447,37.583 D3.3@80.46,37.57
  Int3 (Sign) w0.1: v1(56.69,38.93) 57.06,38.56 57.667,38.56 57.997,38.89 78.4,38.89 79.707,37.583 v1(79.713,37.583)
NetD5_1: D5.1 J4.1 L7.1 | length 22.6
  Top Layer w0.2: v1(30.27,68.47) 30.27,63.14 31.05,62.36 J4.1@31.05,59.7
  Int2 (Sign) w0.3: v1(30.27,68.47) 30.46,68.66 37.18,68.66 39.53,66.31 v1(39.53,65.24)
  Bottom Layer w0.2: v1(30.27,68.47) L7.1@30.845,68.47
  Bottom Layer w0.3: D5.1@38.95,66.51 38.95,65.82 v1(39.53,65.24)
NetD11_3: D11.3 D12.3 R76.1 | length 6.8
  Bottom Layer w0.305: D12.3@49.42,39.535 52.83,39.535 D11.3@52.85,39.515 53.215,39.515 54.59,38.14 R76.1@55.69,38.14
NetD12_1: D12.1 R78.1 | length 1.4
  Bottom Layer w0.305: D12.1@50.07,37.385 50.07,36.6 R78.1@50.54,36.13
NetD13_2: D13.2 R80.1 | length 1.5
  Top Layer w0.1: D13.2@15.4,69.25 v1(15.4,70)
  Bottom Layer w0.1: R80.1@15.4,69.25 v1(15.4,70)
NetD14_2: D14.2 R81.1 | length 1.5
  Top Layer w0.1: D14.2@16.8,69.25 v1(16.8,70)
  Bottom Layer w0.1: R81.1@16.8,69.25 v1(16.8,70)
NetD15_2: D15.2 R82.1 | length 1.5
  Top Layer w0.1: D15.2@14,69.25 v1(14,70)
  Bottom Layer w0.1: R82.1@14,69.25 v1(14,70)
NetJ1_2: J1.2 J15.4 | length 67.5
  Top Layer w0.1: J1.2@68.55,8.19 68.55,8.501 68.55,8.85 v1(68.75,9.05) ; J15.4@93.49,47.895 94.765,47.895 v1(94.77,47.9)
  Int2 (Sign) w0.1: v1(68.75,9.05) 68.766,9.066 68.978,9.066 69.152,9.24 91.68,9.24 94.827,12.387 94.827,20.957 97.09,23.22 97.09,46.32 95.51,47.9 v1(94.77,47.9)
NetJ1_4: J1.4 J11.16 | length 27.4
  Top Layer w0.1: J1.4@68.15,8.231 68.15,8.501 68.15,8.945 68.401,9.196 68.401,9.756 v1(68.399,9.758)
  Int3 (Sign) w0.1: J11.16@47.42,4.27 48.07,3.62 48.58,3.11 55.917,3.11 56.18,3.373 56.18,4.94 57.39,6.15 61.239,6.15 62.26,7.171 63.019,7.93 67.72,7.93 68.399,8.609 v1(68.399,9.758)
NetJ1_6: J1.6 J11.17 | length 27
  Top Layer w0.1: J1.6@67.748,8.229 67.748,9.098 68.046,9.396 v1(68.046,9.404)
  Int3 (Sign) w0.1: J11.17@49.96,1.73 51.13,2.9 55.99,2.9 56.38,3.29 56.38,4.857 57.473,5.95 61.321,5.95 63.101,7.73 67.925,7.73 68.895,8.7 69.11,8.915 69.11,9.81 68.812,10.108 68.254,10.108 68.046,9.899 v1(68.046,9.404)
NetJ1_7: J1.7 J13.28 | length 32.9
  Top Layer w0.1: J1.7@67.348,10.839 67.348,10.252 v1(67.65,9.95)
  Int2 (Sign) w0.1: v1(67.65,9.95) 67.656,9.95 67.814,10.108 68.544,10.108 69.212,9.44 89.23,9.44 v1(91.75,11.96)
  Int3 (Sign) w0.1: v1(91.75,11.96) 92.69,11.96 94.73,14 v1(96.06,14)
  Bottom Layer w0.1: J13.28@94.86,14 v1(96.06,14)
NetJ1_9: J1.9 R68.1 | length 71.2
  Top Layer w0.1: J1.9@66.948,10.839 66.95,10.837 66.95,10.04 v1(66.95,10.08)
  Int2 (Sign) w0.1: v1@66.95,10.071 67.187,10.308 68.627,10.308 69.295,9.64 87.72,9.64 90.37,12.29 90.37,15.674 92.71,18.014 92.71,42.268 92.71,45.4 93.82,46.51 93.82,52.013 93.2,52.633 93.2,55.14 v1(93.19,55.15)
  Bottom Layer w0.1: R68.1@92.64,55.61 93.05,55.61 93.19,55.47 v1(93.19,55.15)
NetJ1_10: J1.10 J11.24 U18.4 | length 86.9
  Top Layer w0.1: J11.24@57.58,4.27 58.69,3.16 60.96,3.16 61.15,3.35 61.15,5.01 62.14,6 65.77,6 66.95,7.18 J1.10@66.95,7.94 v1@66.95,9.42
  Int3 (Sign) w0.1: v1(5.26,12.84) 7.03,11.07 7.03,8.611 7.26,8.38 7.42,8.38 10.46,5.34 31.433,5.34 31.663,5.57 36.013,5.57 36.723,6.28 40.74,6.28 55.155,6.28 56.19,7.315 56.19,9.285 56.883,9.978 60.494,9.978 61.012,9.46 61.495,9.46 61.89,9.46 62.18,9.17 62.18,8.936 62.976,8.14 66.122,8.14 66.9,8.918 66.9,9.22 66.901,9.221 66.901,9.381 v1(66.95,9.43)
  Bottom Layer w0.1: U18.4@4.045,12.835 4.05,12.84 v1(5.26,12.84)
NetJ1_11: J1.11 R104.1 | length 69
  Top Layer w0.1: J1.11@66.548,10.839 66.55,10.837 66.55,9.72 v1(66.55,9.75)
  Int2 (Sign) w0.1: v1(66.55,9.75) 66.55,10.175 66.883,10.508 68.71,10.508 69.378,9.84 87.637,9.84 90.17,12.373 90.17,15.757 92.51,18.097 92.51,42.185 ; 92.51,42.185 92.51,45.483 93.62,46.593 93.62,51.93 v1(92.64,52.91)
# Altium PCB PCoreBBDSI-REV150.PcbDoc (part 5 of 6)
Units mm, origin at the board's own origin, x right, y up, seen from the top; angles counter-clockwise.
Board outline 100 x 72 mm, 6 copper layers (Top Layer, Int1 (GND), Int2 (Sign), Int3 (Sign), Int4 (GND), Bottom Layer), stack 1.538 mm thick; 358 components, 405 nets, 1521 pads, 834 vias.
Unrouted connection lines stored in the file: 10.

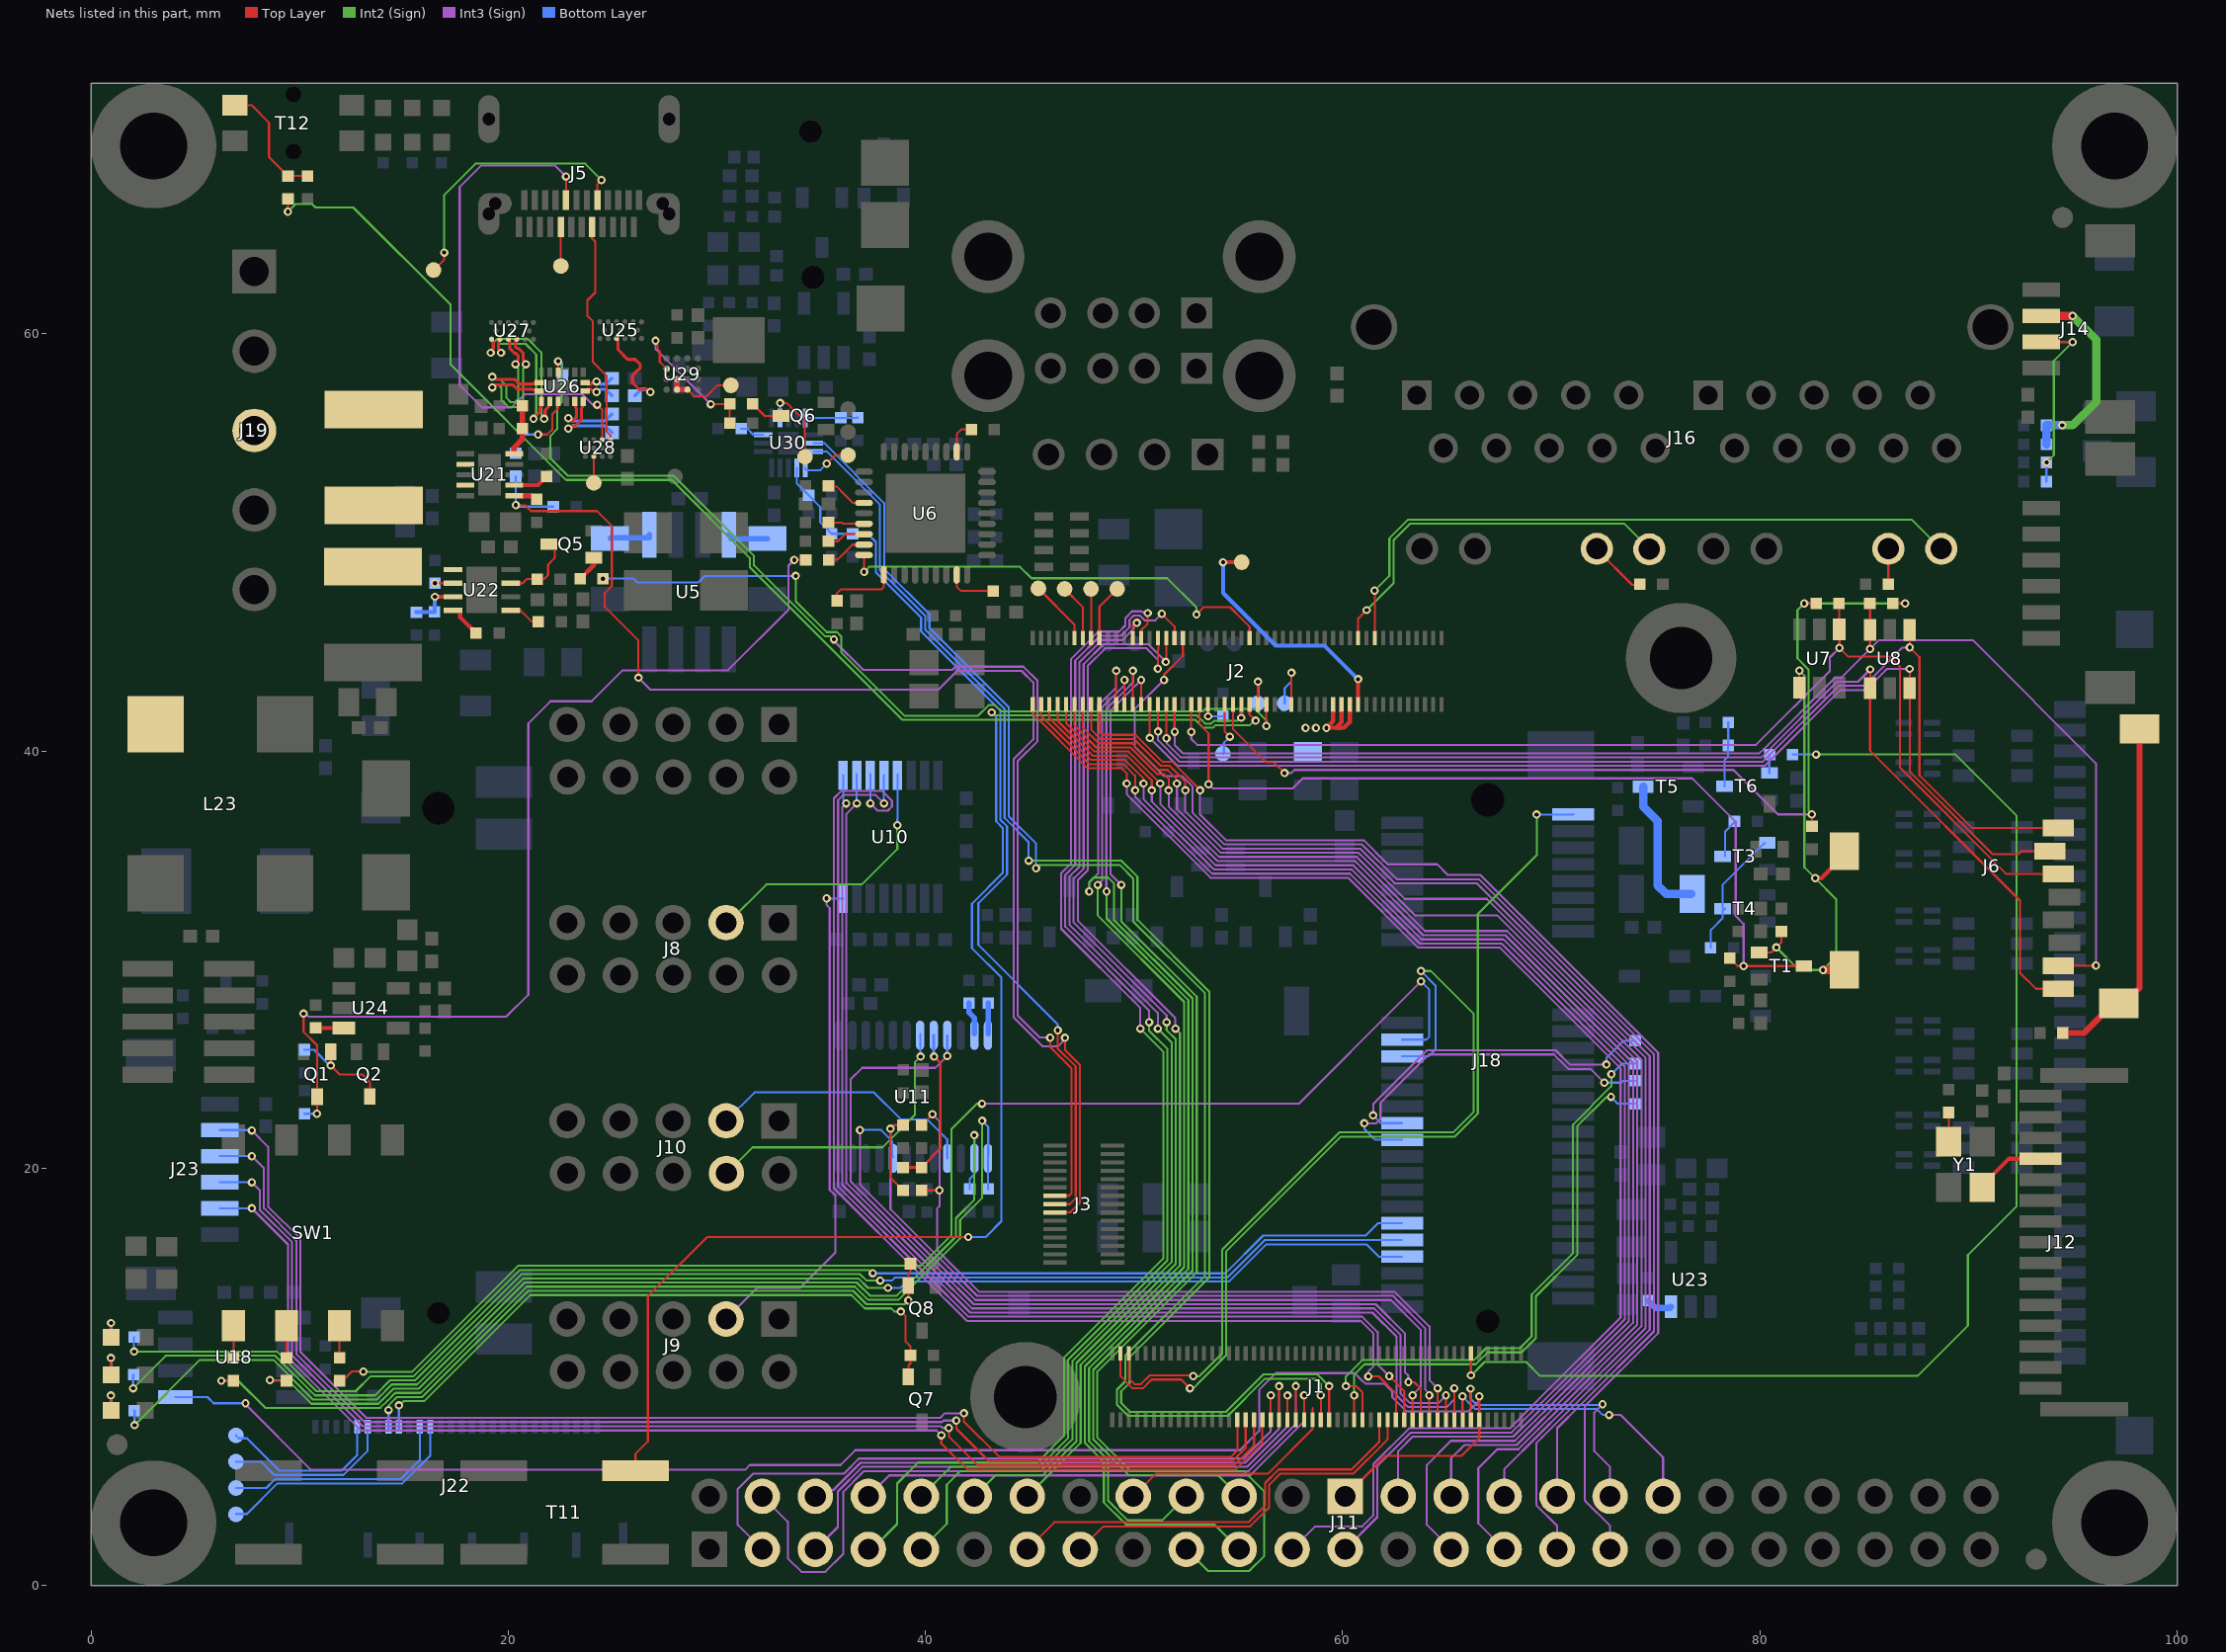
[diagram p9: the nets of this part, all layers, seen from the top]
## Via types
v1: diameter 0.4, hole 0.2, Top Layer to Bottom Layer, tented both sides, 706 vias
v2: diameter 0.5, hole 0.3, Top Layer to Bottom Layer, tented both sides, 102 vias
v3: diameter 0.4, hole 0.2, Top Layer to Bottom Layer, tented bottom, 16 vias
v4: diameter 0.9, hole 0.9, Top Layer to Bottom Layer, tented both sides, 6 vias
v5: diameter 0.5, hole 0.5, Top Layer to Bottom Layer, 2 vias
v6: diameter 3.2, hole 3.2, Top Layer to Bottom Layer, 2 vias

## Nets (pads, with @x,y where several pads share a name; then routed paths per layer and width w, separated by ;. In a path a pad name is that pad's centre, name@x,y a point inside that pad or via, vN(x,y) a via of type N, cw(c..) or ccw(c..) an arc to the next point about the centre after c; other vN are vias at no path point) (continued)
NetJ1_12: J1.12 J11.26 U18.1 | length 78
  Top Layer w0.1: J11.26@60.12,4.27 62.062,6.211 65.699,6.211 66.55,7.063 J1.12@66.55,7.94 v1(66.55,9.063) v1@66.55,9.1
  Int2 (Sign) w0.1: v1@66.55,9.1 v1@66.56,9.09
  Int3 (Sign) w0.1: v1(7.405,8.73) 7.405,8.678 10.543,5.54 31.35,5.54 31.58,5.77 35.93,5.77 36.64,6.48 55.072,6.48 55.99,7.398 55.99,9.368 56.8,10.178 60.577,10.178 60.88,9.875 61.095,9.66 61.578,9.66 62,9.66 62.38,9.28 62.38,9.019 63.05,8.349 66.029,8.349 66.518,8.838 66.518,9.031 v1(66.55,9.063)
  Bottom Layer w0.1: U18.1@4.045,9.025 5.585,9.025 5.88,8.73 v1(7.405,8.73)
NetJ1_13: J1.13 R48.1 | length 63.5
  Top Layer w0.127: J1.13@66.148,10.839 66.15,10.837 v1(66.15,10.07)
  Int2 (Sign) w0.1: v1(66.15,10.07) 66.162,10.07 66.8,10.708 68.793,10.708 69.461,10.04 87.554,10.04 89.97,12.456 89.97,15.84 92.31,18.18 92.31,33.71 92.31,36.89 89.37,39.83 v1(82.69,39.83)
  Bottom Layer w0.1: R48.1@81.57,39.83 v1(82.69,39.83)
NetJ1_14: J1.14 J11.36 | length 13.4
  Top Layer w0.1: v1(66.13,9.43) 66.14,9.42 66.14,8.17 J1.14@66.15,8.16
  Int3 (Sign) w0.1: v1(72.458,8.68) 72.06,8.282 72.06,6.43 72.82,5.67 J11.36@72.82,4.27 J11.36@72.62,4.47
  Bottom Layer w0.1: v1(66.13,9.43) 66.13,8.956 66.436,8.65 72.428,8.65 v1(72.458,8.68)
NetJ1_16: J1.16 J11.38 | length 13.6
  Top Layer w0.1: v1(65.74,9.063) 65.745,9.058 65.745,8.165 J1.16@65.75,8.16
  Int3 (Sign) w0.1: v1(72.77,8.17) 73.33,8.17 75.36,6.14 J11.38@75.36,4.27
  Bottom Layer w0.1: v1(65.74,9.063) 66.253,8.55 66.353,8.45 72.193,8.45 72.473,8.17 v1@72.768,8.17
NetJ1_18: J1.18 U10.9 | length 57.2
  Top Layer w0.1: J1.18@65.348,8.229 65.35,8.231 v1(65.35,9.45)
  Int3 (Sign) w0.1: 36.01,37.24 36.01,33.241 36.01,32.619 36.01,19.212 40.31,14.913 42.143,13.08 61.42,13.08 62.58,11.92 62.58,9.102 63.132,8.55 64.98,8.55 65.35,8.92 v1(65.35,9.45) ; 36.01,37.24 36.01,37.3 v1(36.2,37.49)
  Bottom Layer w0.1: U10.9@36.055,38.83 36.055,38.42 36.055,37.462 36.172,37.462 v1(36.2,37.49)
NetJ1_20: J1.20 U10.10 | length 55.6
  Top Layer w0.1: J1.20@64.948,8.229 64.95,8.231 v1(64.95,9.11)
  Int3 (Sign) w0.1: v1(36.71,37.49) 36.21,36.99 36.21,33.324 36.21,32.536 36.21,19.295 40.51,14.996 42.225,13.28 61.457,13.28 61.503,13.28 62.78,12.003 62.78,11.957 62.78,11.858 62.78,9.185 63.215,8.75 64.6,8.75 64.95,9.1 v1(64.95,9.11)
  Bottom Layer w0.1: U10.10@36.705,38.88 36.705,37.635 36.71,37.63 v1(36.71,37.49)
NetJ1_22: J1.22 R39.1 R41.1 | length 37.8
  Top Layer w0.1: R41.1@39.815,18.936 v1(40.67,18.936) ; R39.1@39.815,22.064 39.815,22.075 v1(40.33,22.59) ; J1.22@64.548,8.229 64.55,8.231 v1(64.55,9.45)
  Int3 (Sign) w0.1: v1(40.33,22.59) 40.67,22.25 v1(40.67,18.936) 40.67,18.175 40.55,18.055 40.55,16.087 42.557,14.08 62.48,14.08 64.16,12.4 64.16,9.84 v1(64.55,9.45)
NetJ1_24: J1.24 R40.1 R42.1 | length 39.9
  Top Layer w0.1: R40.1@38.925,18.936 38.32,19.541 v1(38.32,21.89) 38.494,22.064 R42.1@38.925,22.064 ; J1.24@64.148,8.229 64.15,8.231 v1(64.15,9.11)
  Int3 (Sign) w0.1: v1(38.32,21.89) 38.32,18.034 41.11,15.244 42.474,13.88 62.397,13.88 63.95,12.327 63.95,9.391 64.15,9.191 v1(64.15,9.11)
NetJ1_26: J1.26 U11.9 | length 44.9
  Top Layer w0.1: v1(63.15,9.75) 63.162,9.738 63.433,9.738 63.75,9.421 J1.26@63.75,8.231
  Int3 (Sign) w0.1: v1(41.04,25.38) 40.469,24.809 36.964,24.809 36.41,24.255 36.41,19.378 40.71,15.079 42.308,13.48 61.54,13.48 61.586,13.48 62.98,12.086 62.98,12.04 62.98,10.224 63.15,10.055 v1(63.15,9.75)
  Bottom Layer w0.1: v1(41.04,25.38) 41.045,25.385 U11.9@41.045,26.37
NetJ1_28: J1.28 U11.20 | length 39.1
  Top Layer w0.1: J1.28@63.348,8.229 63.35,8.231 v1(63.35,9.11)
  Int3 (Sign) w0.1: v1(36.86,21.83) 36.855,21.825 36.855,19.216 40.91,15.161 42.391,13.68 62.314,13.68 63.75,12.244 63.75,9.54 63.35,9.14 v1(63.35,9.11)
  Bottom Layer w0.1: v1(36.86,21.83) 37.87,21.83 38.41,21.29 38.41,20.585 U11.20@38.455,20.54
NetJ1_30: J1.30 U10.12 | length 55.6
  Top Layer w0.1: v1(62.23,10.03) 62.95,9.31 62.95,8.501 J1.30@62.95,8.16
  Int3 (Sign) w0.1: v1(38.01,37.49) 37.61,37.89 36.054,37.89 35.81,37.645 35.81,37.323 35.81,33.158 35.81,32.702 35.81,19.129 40.109,14.83 42.06,12.88 60.941,12.88 61.674,12.147 61.674,10.586 61.93,10.33 v1(62.23,10.03)
  Bottom Layer w0.1: U10.12@38.005,38.83 U10.12@38.005,38.83 38.006,37.684 38.01,37.68 v1(38.01,37.49)
NetJ1_32: J1.32 U10.11 | length 58.3
  Top Layer w0.1: v1(61.23,10.02) 61.73,10.02 62.55,9.2 J1.32@62.55,8.16
  Int3 (Sign) w0.1: v1(37.36,37.49) 37.71,37.14 37.865,37.14 38.155,37.14 38.19,37.14 38.39,37.34 38.39,37.61 37.91,38.09 35.971,38.09 35.61,37.728 35.61,33.075 35.61,32.785 35.61,19.046 39.909,14.747 41.977,12.68 60.858,12.68 61.474,12.064 61.474,10.514 61.23,10.27 v1(61.23,10.02)
  Bottom Layer w0.1: U10.11@37.355,38.88 37.355,37.635 37.36,37.63 v1(37.36,37.49)
NetJ1_34: J1.34 J11.15 | length 18.5
  Top Layer w0.1: J11.15@47.42,1.73 48.52,2.83 55.563,2.83 56.48,3.747 56.48,4.827 57.013,5.36 60.513,5.36 61.95,6.797 62.15,6.997 J1.34@62.15,7.94 ; J1.34@62.148,8.229 J1.34@62.15,8.231
NetJ1_36: J1.36 J11.13 | length 20.7
  Top Layer w0.1: J11.13@44.88,1.73 46.18,3.03 55.48,3.03 56.28,3.83 56.28,4.91 56.93,5.56 60.43,5.56 61.75,6.88 J1.36@61.75,7.94 ; J1.36@61.748,8.229 J1.36@61.75,8.231
NetJ1_40: J1.40 R55.2 | length 27.9
  Top Layer w0.1: v1(60.15,9.55) 60.65,9.55 60.95,9.25 J1.40@60.95,8.231 ; J1.40@60.948,8.229 J1.40@60.95,8.231 ; J1.40@60.95,7.94 J1.40@60.95,8.231
  Int2 (Sign) w0.1: v1(60.15,9.55) 60.15,10.01 60.94,10.8 66.296,10.8 66.866,11.37 68.493,11.37 69.06,11.938 69.06,13.943 71.04,15.923 71.04,22.095 72.855,23.91 72.887,23.942 72.887,23.952 72.89,23.955 72.89,24.245 72.88,24.255 v1(72.88,24.5)
  Bottom Layer w0.1: v1(72.88,24.5) 73.39,25.01 R55.2@74.02,25.01
NetJ1_42: J1.42 R56.2 | length 25.8
  Top Layer w0.1: J1.42@60.548,8.229 60.55,8.231 v1(60.55,9.11)
  Int2 (Sign) w0.1: v1(60.55,9.11) 60.55,10.11 61.04,10.6 66.379,10.6 66.949,11.17 68.413,11.17 68.575,11.17 69.26,11.855 69.26,13.86 71.24,15.84 71.24,22.012 72.632,23.404 72.844,23.404 v1(72.86,23.42)
  Bottom Layer w0.1: v1(72.86,23.42) 73.19,23.09 R56.2@74.02,23.09
NetJ1_48: J1.48 U30.8 | length 70.6
  Top Layer w0.1: J1.48@59.35,8.231 59.348,8.229 59.348,9.548 v1(59.35,9.55)
  Int2 (Sign) w0.1: v1(44.95,34.74) 49.39,34.74 50.16,33.97 50.16,31.908 53.6,28.467 53.6,14.759 49.78,10.938 49.78,9.7 49.377,9.297 49.377,8.746 49.803,8.32 54.4,8.32 56.19,10.11 58.79,10.11 v1(59.35,9.55)
  Bottom Layer w0.1: U30.8@34.63,54.36 35.264,54.36 37.82,51.804 37.82,51.52 37.82,50.973 37.82,48.647 39.99,46.477 39.99,45.818 43.79,42.018 43.79,36.79 44.934,35.646 44.934,34.756 v1(44.95,34.74)
NetJ1_50: J1.50 U30.7 | length 70.8
  Top Layer w0.1: J1.50@58.948,8.229 58.95,8.231 v1(58.95,9.11)
  Int2 (Sign) w0.1: v1(45.3,34.38) 45.302,34.38 45.462,34.54 49.307,34.54 49.96,33.887 49.96,31.825 53.4,28.384 53.4,14.841 49.58,11.021 49.58,9.783 49.177,9.38 49.177,8.663 49.72,8.12 54.483,8.12 56.273,9.91 58.707,9.91 58.95,9.667 v1(58.95,9.11)
  Bottom Layer w0.1: U30.7@34.63,54.76 35.147,54.76 38.02,51.886 38.02,48.73 40.19,46.56 40.19,45.901 43.99,42.101 43.99,36.873 45.3,35.563 v1(45.3,34.38)
NetJ1_52: J1.52 J11.18 | length 10.9
  Top Layer w0.1: J11.18@49.96,4.27 51.04,5.35 56.41,5.35 58.55,7.49 58.55,7.628 J1.52@58.55,7.94 ; J1.52@58.548,7.94 58.548,8.501
NetJ1_54: J1.54 J11.8 | length 24.8
  Top Layer w0.1: J1.54@58.148,8.229 58.148,8.75 ; v1@58.148,9.048 58.148,8.75 ; v1(58.15,9.11) 58.15,8.752 58.148,8.75
  Int3 (Sign) w0.1: J11.8@37.26,4.27 38.262,5.272 39.05,5.272 ; 39.05,5.272 55.562,5.272 58.15,7.86 v1(58.15,9.11)
  Bottom Layer w0.1: J11.8@37.25,4.28 J11.8@37.26,4.27
NetJ1_56: J1.56 J11.4 | length 35.9
  Top Layer w0.1: J1.56@57.748,8.229 57.748,9.548 v1(57.75,9.55)
  Int3 (Sign) w0.1: J11.4@32.18,4.27 33.4,3.05 33.4,1.3 34.05,0.65 35.2,0.65 36.05,1.5 36.05,4.474 37.056,5.48 40.409,5.48 55.487,5.48 57.75,7.743 v1(57.75,9.55)
NetJ1_58: J1.58 J11.5 | length 28.4
  Top Layer w0.1: J1.58@57.348,8.229 57.348,9.098 v1(57.35,9.1)
  Int3 (Sign) w0.1: J11.5@34.72,1.73 34.73,1.73 35.8,2.8 35.8,4.507 36.973,5.68 40.492,5.68 55.404,5.68 57.35,7.626 v1(57.35,9.1)
NetJ1_60: J1.60 J11.6 | length 26.9
  Top Layer w0.1: J1.60@56.948,8.229 56.95,8.231 v1(56.95,9.55)
  Int3 (Sign) w0.1: J11.6@34.72,4.27 35.026,4.576 35.586,4.576 36.89,5.88 40.575,5.88 55.321,5.88 56.95,7.509 v1(56.95,9.55)
NetJ1_62: J1.62 J11.3 | length 36.8
  Top Layer w0.1: 56.548,8.752 56.548,8.229 56.55,8.231 v1(56.55,9.11) ; 56.55,8.752 v1(56.55,9.11) ; 56.55,8.752 v1(56.55,9.11) ; 56.55,8.752 v1(56.55,9.11) ; 56.55,8.752 v1(56.55,9.11) ; 56.55,8.752 v1(56.55,9.11) ; 56.55,8.752 v1(56.55,9.11) ; 56.55,8.752 v1(56.55,9.11) ; 56.55,8.752 v1(56.55,9.11) ; 56.55,8.752 v1(56.55,9.11) ; 56.55,8.752 v1(56.55,9.11)
  Int3 (Sign) w0.1: J11.3@32.18,1.73 32.17,1.73 31,2.9 31,4.62 31.74,5.36 36.087,5.36 36.807,6.08 40.657,6.08 55.238,6.08 56.55,7.392 v1(56.55,9.11)
NetJ1_64: J1.64 J23.5 | length 60.3
  Top Layer w0.1: v1(40.76,7.2) 40.76,6.8 42.01,5.55 54.877,5.55 56.148,6.821 J1.64@56.148,8.229
  Int3 (Sign) w0.1: v1(7.71,18.075) 9.44,16.345 9.44,10.936 10.05,10.326 10.05,10.323 12.943,7.43 40.53,7.43 v1(40.76,7.2)
  Bottom Layer w0.1: J23.5@6.17,18.075 7.47,18.075
NetJ1_66: J1.66 J23.4 | length 60.9
  Top Layer w0.1: v1(41.12,7.55) 41.12,7.15 42.52,5.75 54.794,5.75 55.748,6.704 J1.66@55.748,8.229
  Int3 (Sign) w0.1: v1(7.71,19.325) 8.09,18.945 8.09,17.994 9.64,16.444 9.64,11.019 13.029,7.63 40.74,7.63 40.82,7.55 v1(41.12,7.55)
  Bottom Layer w0.1: J23.4@6.17,19.325 7.47,19.325
NetJ1_68: J1.68 J23.3 | length 61.5
  Top Layer w0.1: v1(41.48,7.9) 41.48,7.515 43.045,5.95 54.711,5.95 55.348,6.587 J1.68@55.348,8.229
  Int3 (Sign) w0.1: v1(7.71,20.575) 8.29,19.995 8.29,18.077 9.84,16.527 9.84,11.102 13.112,7.83 40.793,7.83 40.863,7.9 v1(41.48,7.9)
  Bottom Layer w0.1: J23.3@6.17,20.575 7.47,20.575
NetJ1_70: J1.70 J23.2 | length 62.4
  Top Layer w0.1: v1(41.84,8.25) 41.84,7.862 43.552,6.15 54.628,6.15 54.948,6.47 J1.70@54.948,8.229
  Int3 (Sign) w0.1: v1(7.71,21.81) 8.49,21.03 8.49,18.16 10.04,16.61 10.04,11.185 13.195,8.03 40.71,8.03 40.93,8.25 v1(41.84,8.25)
  Bottom Layer w0.1: J23.2@6.17,21.825 7.695,21.825 v1(7.71,21.81)
NetJ1_95: J1.95 J18.22 | length 40.1
  Top Layer w0.1: J1.95@49.75,11.12 49.75,9.915 50.015,9.65 50.335,9.65 50.755,10.07 52.83,10.07 52.84,10.08 52.84,10.032 v1(52.838,10.03)
  Int2 (Sign) w0.1: v1(52.838,10.03) 53.13,10.03 54.22,11.12 54.22,16.1 59.835,21.715 65.295,21.715 66.28,22.7 66.28,27.39 64.22,29.45 v1(63.75,29.45)
  Bottom Layer w0.1: J18.22@62.85,25.36 64.11,25.36 64.45,25.7 64.45,28.749 v1(63.75,29.45)
NetJ1_97: J1.97 J18.1 | length 44.4
  Top Layer w0.1: J1.97@49.35,11.12 49.35,10.032 49.932,9.45 50.418,9.45 50.838,9.87 52.26,9.87 v1(52.68,9.45)
  Int2 (Sign) w0.1: v1(52.68,9.45) 52.833,9.45 53.213,9.83 54.42,11.037 54.42,16.017 59.918,21.515 65.378,21.515 66.48,22.617 66.48,32.186 69.3,35.006 v1(69.3,36.95)
  Bottom Layer w0.1: v1(69.3,36.95) 71.04,36.95 J18.1@71.05,36.96
NetJ2_17: J2.17 J16.L14 | length 32.8
  Top Layer w0.1: v1(61.53,47.69) 61.538,47.682 J2.17@61.538,45.129
  Int2 (Sign) w0.1: v1(61.53,47.69) 61.53,47.68 62.24,48.39 62.24,50.193 63.137,51.09 87.275,51.09 J16.L14@88.695,49.67
NetJ2_21: J2.21 J16.R14 | length 18.8
  Top Layer w0.1: J2.21@60.738,45.129 60.738,46.338 v1(61.15,46.75)
  Int2 (Sign) w0.1: v1(61.15,46.75) 62.44,48.04 62.44,50.11 63.22,50.89 73.505,50.89 J16.R14@74.725,49.67
NetJ2_22: J2.22 TP1.1 | length 11.5
  Top Layer w0.2: v1(54.265,49.045) 54.27,49.05 TP1.1@55.16,49.05 ; J2.22@60.738,42.519 v1(60.738,43.44)
  Bottom Layer w0.2: v1(54.265,49.045) 54.27,49.04 54.27,47.57 56.79,45.05 59.128,45.05 v1(60.738,43.44)
NetJ2_24: J2.24 J2.26 J2.28 R2.1 | length 5.3
  Top Layer w0.2: J2.28@59.54,42.45 59.54,41.42 v1(59.22,41.1) 59.23,41.11 59.67,41.11 ; J2.26@59.94,42.45 59.94,41.38 59.66,41.1 59.914,41.1 59.924,41.11 60.06,41.11 60.34,41.39 J2.24@60.34,42.45
  other v1: 58.22,41.1 58.72,41.1
NetJ2_38: J2.38 TP29.1 | length 3.1
  Top Layer w0.1: J2.38@57.54,42.23 v1@57.54,43.76
  Bottom Layer w0.1: TP29.1@57.22,42.29 57.22,43.01 57.54,43.33 v1@57.54,43.76
  other v1: 57.54,43.75
NetJ2_44: J2.44 R79.1 | length 38.2
  Top Layer w0.1: R79.1@24.54,48.25 v1(24.54,48.26) ; J2.44@56.338,42.519 56.338,41.2 v1(56.34,41.2)
  Int2 (Sign) w0.1: v1(33.782,48.387) 33.782,47.178 35.26,45.7 35.755,45.7 35.96,45.495 35.96,44.72 38.99,41.69 42.525,41.69 43.035,42.2 43.34,42.2 43.64,41.9 53.297,41.9 53.406,42.01 55.8,42.01 56.11,41.7 56.34,41.47 v1(56.34,41.2)
  Bottom Layer w0.1: v1(24.54,48.26) 25.825,48.26 26,48.26 26.19,48.07 29.1,48.07 29.417,48.387 v1(33.782,48.387)
NetJ2_46: J2.46 TP23.1 | length 2.1
  Top Layer w0.1: J2.46@55.94,42.23 v1(55.94,43.32)
  Bottom Layer w0.1: TP23.1@55.92,42.29 55.94,42.31 v1(55.94,43.32)
NetJ2_47: J2.47 U6.27 | length 21.9
  Top Layer w0.1: U6.27@37,49.39 37.084,49.306 37.06,49.282 v1(37.06,48.59) ; v1(52.99,46.54) 53.34,46.89 54.6,46.89 55.2,46.29 55.538,45.952 J2.47@55.538,45.129
  Int2 (Sign) w0.1: v1(37.06,48.59) 37.3,48.83 44.53,48.83 45.08,48.28 51.59,48.28 52.99,46.88 v1(52.99,46.54)
NetJ2_48: J2.48 R70.2 | length 60.8
  Top Layer w0.1: v1(9.44,65.85) R70.2@9.44,66.46 ; J2.48@55.54,42.517 55.538,42.519 55.538,41.742 v1(55.83,41.45)
  Int2 (Sign) w0.1: v1(9.44,65.85) 9.8,66.21 10.605,66.21 10.765,66.05 11.223,66.05 12.038,66.05 12.57,66.05 17.23,61.39 17.23,59.498 17.23,59.042 17.23,58.526 22.766,52.99 26.925,52.99 27.215,52.99 27.845,52.99 31.58,49.255 31.58,48.814 38.904,41.49 52.943,41.49 53.128,41.305 53.324,41.109 53.779,41.109 53.91,41.24 55.557,41.24 55.767,41.45 v1(55.83,41.45)
NetJ2_50: J2.50 T11.2 | length 66.1
  Top Layer w0.1: T11.2@26.1,5.5 26.1,6.31 26.695,6.905 26.695,13.865 29.53,16.7 v1(42.05,16.7) ; v1(55.13,41.59) 55.13,41.57 v1@55.14,41.56
  Top Layer w0.2: v1@55.14,41.56 J2.50@55.14,42.23 J2.50@55.14,42.45
  Int2 (Sign) w0.1: v1(43.18,41.85) 43.222,41.85 43.372,41.7 43.557,41.7 53.016,41.7 53.406,41.309 53.696,41.309 53.827,41.44 54.958,41.44 55.108,41.59 v1(55.13,41.59)
  Bottom Layer w0.1: v1(42.05,16.7) 42.885,16.7 43.64,17.455 43.64,26.377 43.64,29.14 42.23,30.55 42.23,32.68 43.71,34.16 43.71,36.304 43.39,36.624 43.39,41.638 v1(43.18,41.85) v1(43.18,41.85)
NetJ2_52: J2.52 R23.2 R24.2 R29.2 | length 48.2
  Top Layer w0.1: J2.52@54.738,42.519 54.738,41.062 56.35,39.45 56.7,39.45 v1(57.21,38.94) ; v1(82.12,47.07) 82.68,47.07 R24.2@82.69,47.08 ; v1(82.49,36.96) 82.49,36.35 R29.2@82.5,36.34 ; R23.2@86.37,47.08 86.95,47.08 v1(86.96,47.07)
  Int2 (Sign) w0.1: v1(82.49,36.96) 82.49,36.962 82.33,37.122 82.33,43.905 81.8,44.435 81.8,46.75 v1(82.12,47.07) v1(86.96,47.07)
  Int3 (Sign) w0.1: v1(57.21,38.94) 57.54,38.94 57.69,39.09 78.733,39.09 80.864,36.96 v1@82.458,36.96
NetJ2_58: J2.58 R22.1 | length 1.6
  Top Layer w0.1: J2.58@53.538,42.519 53.546,42.511 53.546,41.665 v1(53.551,41.659)
  Bottom Layer w0.1: v1(53.551,41.659) R22.1@54.259,41.659
NetJ2_60: J2.60 R21.1 T1.3 | length 41.5
  Top Layer w0.1: J2.60@53.138,42.519 53.138,41.272 53.57,40.84 v1@53.57,38.41 ; R21.1@78.56,30.06 78.93,29.69 v1(79.22,29.69) T1.3@82.105,29.69
  Int3 (Sign) w0.1: v1@53.57,38.41 53.78,38.2 57.59,38.2 58.08,38.69 76.755,38.69 78.84,36.605 78.84,32.09 79.22,31.71 v1(79.22,29.69)
  other v1: 53.57,38.406
NetJ2_62: J2.62 J6.3 R24.1 U7.4 | length 55.4
  Top Layer w0.1: J2.62@52.738,42.519 52.738,40.917 v1(52.74,40.915) ; R24.1@83.79,47.08 83.8,47.07 U7.4@83.8,45.83 83.81,45.82 v1(83.81,44.94) 84.22,44.53 86.22,44.53 86.72,44.03 86.72,39.194 91.814,34.1 J6.3@94.3,34.1
  Int3 (Sign) w0.1: v1(52.74,40.915) 52.74,40.569 53.019,40.29 56.651,40.29 79.816,40.291 83.35,43.825 83.35,44.48 v1(83.81,44.94)
NetJ2_63: J2.63 J11.34 | length 60.8
  Top Layer w0.1: v1(51.43,43.4) 51.43,43.65 52.34,44.56 52.34,44.849 J2.63@52.34,45.19
  Int3 (Sign) w0.1: v1@51.45,43.43 50.04,42.02 50.04,40.19 51.43,38.8 52.3,38.8 52.81,38.29 52.81,37.034 54.323,35.521 60.923,35.521 62.593,33.85 66.527,33.85 74.9,25.477 74.9,25.469 74.921,25.448 74.921,12.179 71.4,8.658 70.28,7.539 J11.34@70.28,4.27
NetJ2_65: J2.65 J11.10 | length 56.5
  Top Layer w0.1: v1(51.33,46.57) 51.94,45.96 51.94,45.795 J2.65@51.94,45.41
  Int2 (Sign) w0.1: J11.10@39.8,4.27 41.21,5.68 45.442,5.68 46.84,7.078 46.84,10.827 51.6,15.587 51.6,25.71 50.72,26.59 v1(50.72,27)
  Int3 (Sign) w0.1: v1(50.72,27) 50.72,27.56 46.7,31.58 46.7,34.057 47.18,34.537 47.18,44.328 48.372,45.52 49.368,45.52 49.78,45.932 49.78,46.285 49.985,46.49 50.275,46.49 50.505,46.26 51.02,46.26 v1(51.33,46.57)
NetJ2_66: J2.66 J6.7 R23.1 U8.6 | length 65
  Top Layer w0.1: J2.66@51.938,42.519 51.938,40.915 v1@51.953,40.9 ; R23.1@85.27,47.08 85.28,47.07 U8.6@85.28,45.81 v1(85.28,44.89) ; J6.7@94.3,29.7 94.31,29.71 v1(96.11,29.71)
  Int3 (Sign) w0.1: v1(51.95,40.92) 51.95,40.269 52.329,39.89 56.817,39.89 79.982,39.89 80.182,40.09 83.611,43.52 83.91,43.52 v1(85.28,44.89) 85.7,45.31 90.2,45.31 96.11,39.4 v1(96.11,29.71)
NetJ2_67: J2.67 J11.12 | length 53.3
  Top Layer w0.1: v1(51.52,44.27) 51.54,44.29 J2.67@51.54,45.41
  Int2 (Sign) w0.1: J11.12@42.34,4.27 43.35,5.28 45.607,5.28 47.24,6.913 47.24,10.661 52,15.421 52,26.175 51.56,26.615 v1(51.56,27)
  Int3 (Sign) w0.1: v1(51.52,44.27) 51.52,44.28 50.68,45.12 48.538,45.12 47.58,44.162 47.58,34.36 47.1,33.88 47.1,31.78 51.56,27.32 v1(51.56,27)
NetJ2_68: J2.68 J6.8 U8.1 | length 57.6
  Top Layer w0.1: J2.68@51.55,42.507 51.55,40.603 v1(51.551,40.602) ; v1(85.29,43.91) 85.29,43.02 U8.1@85.28,43.01 85.28,40.02 92.47,32.83 92.47,29.36 93.23,28.6 93.979,28.6 J6.8@94.3,28.6
  Int3 (Sign) w0.1: v1(51.551,40.602) 51.562,40.591 51.562,40.374 52.246,39.69 56.899,39.69 80.064,39.69 83.694,43.32 84.7,43.32 v1(85.29,43.91)
NetJ2_69: J2.69 J11.14 | length 50.9
  Top Layer w0.1: v1(51.14,43.94) 51.14,44.848 ; J2.69@51.14,45.41 51.16,45.39 51.16,44.849
  Int2 (Sign) w0.1: J11.14@44.88,4.27 47.44,6.83 47.44,10.578 52.2,15.339 52.2,26.47 v1(51.98,26.69)
  Int3 (Sign) w0.1: v1@51.16,43.96 51.14,43.98 51.14,44.377 50.597,44.92 48.62,44.92 47.78,44.08 47.78,34.277 47.3,33.797 47.3,31.87 51.98,27.19 v1(51.98,26.69)
NetJ2_70: J2.70 J6.1 U8.4 | length 55.5
  Top Layer w0.1: J2.70@51.14,42.45 51.14,40.94 v1(51.15,40.93) ; U8.4@87.18,45.81 v1(87.18,44.96) 87.65,44.49 87.65,38.83 90.18,36.3 J6.1@94.3,36.3
  Int3 (Sign) w0.1: v1(51.15,40.93) 51.15,40.503 52.163,39.49 56.982,39.49 57.438,39.49 57.524,39.49 80.147,39.49 83.777,43.12 84.995,43.12 86.83,44.955 87.175,44.955 v1(87.18,44.96)
NetJ2_72: J2.72 J6.2 U8.3 | length 54.1
  Top Layer w0.1: J2.72@50.74,42.501 50.74,40.63 v1(50.75,40.62) ; v1(87.178,43.933) 87.18,43.931 U8.3@87.18,43.01 87.18,39.017 90.097,36.1 91.145,35.052 92.392,35.052 92.54,35.2 J6.2@93.9,35.2
  Int3 (Sign) w0.1: v1(50.75,40.62) 52.08,39.29 57.065,39.29 57.355,39.29 57.607,39.29 80.23,39.29 83.86,42.92 85.078,42.92 85.84,43.682 86.091,43.933 v1(87.178,43.933)
NetJ2_73: J2.73 J11.7 | length 60.4
  Top Layer w0.1: J2.73@50.34,45.41 50.34,45.79 50.65,46.1 v1(50.65,46.61)
  Int2 (Sign) w0.1: J11.7@37.26,1.73 37.43,1.73 38.64,2.94 38.64,4.88 39.65,5.89 45.369,5.89 46.64,7.161 46.64,10.91 51.4,15.67 51.4,25.59 v1(50.3,26.69)
  Int3 (Sign) w0.1: v1(50.3,26.69) 50.3,27.68 46.5,31.48 46.5,34.14 46.98,34.62 46.98,44.411 48.289,45.72 49.285,45.72 49.58,46.015 49.58,46.368 49.902,46.69 50.358,46.69 50.4,46.648 50.612,46.648 v1(50.65,46.61)
NetJ2_74: J2.74 J11.19 | length 58.1
  Top Layer w0.1: J2.74@50.338,42.519 v1(50.338,43.4)
  Int2 (Sign) w0.1: v1(49.39,33.58) 49.39,31.829 53,28.219 53,15.007 48.24,10.247 48.24,7.08 49.84,5.48 55.244,5.48 56.24,4.484 56.24,1.41 55.52,0.69 53.54,0.69 J11.19@52.5,1.73
  Int3 (Sign) w0.1: v1(49.39,33.58) 48.87,34.1 48.87,41.932 49.74,42.802 v1(50.338,43.4)
NetJ2_75: J2.75 J11.9 | length 56.4
  Top Layer w0.1: J2.75@49.94,45.41 49.94,46.065 49.957,46.083 50.115,46.083 v1@50.13,46.097
  Int2 (Sign) w0.1: J11.9@39.8,1.73 41.02,2.95 41.02,4.83 41.67,5.48 45.524,5.48 47.04,6.995 47.04,10.744 51.8,15.504 51.8,26.03 51.36,26.47 v1(51.14,26.69)
  Int3 (Sign) w0.1: v1(50.13,46.14) 50.13,46.086 49.98,45.936 49.98,45.849 49.451,45.32 48.455,45.32 47.38,44.245 47.38,34.45 46.9,33.97 46.9,31.68 51.14,27.44 v1(51.14,26.69)
NetJ2_76: J2.76 J11.20 | length 50.2
  Top Layer w0.1: J2.76@49.938,42.519 J2.76@49.938,42.562 ; v1(49.938,43.84) J2.76@49.938,42.562 ; J2.76@49.95,42.55 J2.76@49.938,42.562
  Int2 (Sign) w0.1: v1(48.68,33.27) 48.68,31.973 52.6,28.053 52.6,15.173 47.84,10.413 47.84,6.914 48.76,5.994 48.76,4.056 49.696,3.12 51.35,3.12 J11.20@52.5,4.27
  Int3 (Sign) w0.1: v1(48.68,33.27) 48.67,33.28 48.67,42.015 49.54,42.885 49.95,43.295 49.95,43.828 v1(49.938,43.84)
NetJ2_78: J2.78 J11.21 | length 52.3
  Top Layer w0.1: J2.78@49.538,42.519 v1(49.538,43.4)
  Int2 (Sign) w0.1: v1(48.26,33.58) 48.26,32.11 52.4,27.97 52.4,15.256 47.64,10.496 47.64,6.831 48.55,5.921 48.55,3.98 49.61,2.92 51.94,2.92 53.85,2.92 J11.21@55.04,1.73
  Int3 (Sign) w0.1: v1(48.26,33.58) 48.47,33.79 48.47,42.098 49.538,43.166 v1(49.538,43.4)
NetJ2_80: J2.80 J11.22 | length 52.6
  Top Layer w0.1: J2.80@49.138,42.519 v1(49.138,43.84)
  Int2 (Sign) w0.1: v1(47.85,33.27) 47.85,33.72 48.06,33.93 48.76,33.93 49.03,33.66 49.03,33.415 49.03,33.125 49.03,31.906 52.8,28.136 52.8,15.09 48.04,10.33 48.04,6.997 49.757,5.28 54.03,5.28 J11.22@55.04,4.27
  Int3 (Sign) w0.1: v1(47.85,33.27) 47.85,33.69 48.27,34.11 48.27,42.181 49.138,43.048 v1@49.138,43.839
NetJ2_84: J2.84 J11.35 | length 61.2
  Top Layer w0.1: J2.84@48.34,42.45 48.34,40.92 48.49,40.77 50.07,40.77 51.35,39.49 51.82,39.49 53.2,38.11 v1(53.16,38.11)
  Int3 (Sign) w0.1: v1(53.16,38.11) 53.16,36.966 54.406,35.721 61.006,35.721 62.156,34.57 64.53,34.57 65.04,34.06 66.6,34.06 75.1,25.56 75.1,25.551 75.121,25.531 75.121,12.096 71.6,8.576 71.6,4.076 72.82,2.856 J11.35@72.82,1.73
NetJ2_86: J2.86 J11.33 | length 61.8
  Top Layer w0.1: J2.86@47.94,42.45 47.94,41.027 48.397,40.57 49.987,40.57 51.267,39.29 51.701,39.29 52.455,38.536 v1@52.455,38.106
  Int3 (Sign) w0.1: v1@52.455,38.106 52.455,37.106 54.24,35.321 60.84,35.321 60.92,35.241 62.511,33.65 66.444,33.65 74.7,25.394 74.7,25.386 74.721,25.365 74.721,12.262 70.701,8.242 69.558,7.099 69.28,6.821 69.28,3.856 70.28,2.856 J11.33@70.28,1.73
  other v1: 52.455,38.11
NetJ2_88: J2.88 J11.32 | length 59.5
  Top Layer w0.1: J2.88@47.54,42.45 47.54,41.13 48.3,40.37 49.904,40.37 51.184,39.09 51.61,39.09 52.011,38.689 52.011,38.445 v1@52.049,38.406
  Int3 (Sign) w0.1: v1@52.049,38.406 52.057,38.399 52.057,37.221 54.157,35.12 60.757,35.12 60.837,35.04 62.968,32.91 66.901,32.91 74.5,25.311 74.5,25.303 74.52,25.282 74.52,12.345 70.501,8.325 69.475,7.299 67.74,5.564 J11.32@67.74,4.27
  other v1: 52.049,38.44
NetJ2_90: J2.90 J11.31 | length 63.7
  Top Layer w0.1: J2.90@47.14,42.45 47.14,41.215 48.185,40.17 49.821,40.17 51.101,38.89 51.44,38.89 51.658,38.672 51.658,38.116 v1@51.649,38.107
  Int3 (Sign) w0.1: v1@51.649,38.107 51.658,38.098 51.658,37.337 54.074,34.92 60.674,34.92 60.754,34.84 63.485,32.11 67.418,32.11 74.3,25.228 74.3,25.22 74.32,25.199 74.32,12.428 70.3,8.408 69.392,7.5 68.422,6.529 67.409,6.529 66.5,5.62 66.5,2.97 J11.31@67.74,1.73
  other v1: 51.649,38.11
NetJ2_92: J2.92 J11.30 | length 61.8
  Top Layer w0.1: J2.92@46.74,42.45 46.74,41.332 48.102,39.97 49.739,39.97 51.255,38.453 v1(51.255,38.44)
  Int3 (Sign) w0.1: v1(51.255,38.44) 51.257,38.438 51.257,37.455 53.991,34.72 60.591,34.72 60.671,34.64 63.942,31.37 67.875,31.37 74.1,25.146 74.1,25.137 74.12,25.117 74.12,12.511 70.1,8.491 69.309,7.7 68.339,6.73 65.83,6.73 65.2,6.1 J11.30@65.2,4.27
NetJ2_94: J2.94 J11.29 | length 65.6
  Top Layer w0.1: J2.94@46.34,42.45 46.34,41.449 48.019,39.77 49.656,39.77 50.847,38.578 v1@50.847,38.092
  Int3 (Sign) w0.1: v1@50.847,38.092 50.847,37.582 53.909,34.52 60.509,34.52 60.589,34.44 63.859,31.17 67.594,31.17 67.789,31.17 73.9,25.059 73.9,25.054 73.92,25.034 73.92,12.593 69.9,8.574 69.226,7.9 68.256,6.93 65.19,6.93 64.03,5.77 64.03,2.9 J11.29@65.2,1.73
  other v1: 50.847,38.11
NetJ2_96: J2.96 J11.28 | length 64.2
  Top Layer w0.1: J2.96@45.94,42.45 45.94,41.566 47.936,39.57 49.573,39.57 50.451,38.691 v1@50.451,38.428
  Int3 (Sign) w0.1: v1@50.451,38.428 50.451,37.695 53.826,34.32 60.426,34.32 60.506,34.24 63.776,30.97 67.511,30.97 67.706,30.97 73.7,24.976 73.7,24.971 73.72,24.951 73.72,12.676 69.7,8.656 69.144,8.1 68.174,7.13 63.35,7.13 62.66,6.44 J11.28@62.66,4.27
  other v1: 50.451,38.44
NetJ2_98: J2.98 J11.25 | length 67.8
  Top Layer w0.1: J2.98@45.54,42.45 45.54,41.683 47.853,39.369 49.49,39.369 50.05,38.809 v1@50.05,38.1
  Int3 (Sign) w0.1: v1@50.05,38.1 50.05,37.813 53.743,34.12 60.343,34.12 60.423,34.04 63.693,30.77 67.618,30.77 73.43,24.958 73.52,24.868 73.52,12.759 69.5,8.739 69.061,8.3 68.091,7.33 63.267,7.33 61.66,5.723 61.66,3.27 J11.25@60.12,1.73
  other v1: 50.05,38.11
NetJ2_100: J2.100 J11.23 | length 70.2
  Top Layer w0.1: J2.100@45.14,42.45 45.14,41.8 47.771,39.169 49.407,39.169 49.649,38.928 v1@49.649,38.428
  Int3 (Sign) w0.1: v1@49.649,38.428 49.649,37.931 53.66,33.92 60.26,33.92 63.61,30.57 67.535,30.57 73.32,24.785 73.32,12.842 69.3,8.822 68.978,8.5 68.008,7.53 63.184,7.53 61.46,5.806 61.46,3.353 60.937,2.83 58.68,2.83 J11.23@57.58,1.73
  other v1: 49.649,38.44
NetJ3_13: J3.13 R60.2 R95.2 | length 65.4
  Top Layer w0.1: v1(20.36,51.78) 20.81,51.78 21.09,51.5 24.25,51.5 24.965,50.785 24.965,47.913 24.625,47.573 24.625,46.905 26.24,45.29 v1(26.24,43.51) ; J3.13@46.209,17.876 46.926,17.876 47.4,18.35 47.4,24.959 46.69,25.669 v1(46.69,26.25)
  Int3 (Sign) w0.1: v1(26.24,43.51) 26.81,42.94 40.62,42.94 41.52,43.84 44.61,43.84 45.17,43.28 45.17,40.553 44.22,39.603 44.22,27.24 45.624,25.836 46.346,25.836 46.69,26.18 v1(46.69,26.25)
  Bottom Layer w0.1: R95.2@20.36,53.17 v1(20.36,51.78) 20.441,51.78 20.511,51.71 R60.2@22.16,51.71
NetJ3_15: J3.15 R98.1 R102.1 R103.1 U30.10 | length 44.3
  Top Layer w0.1: J3.15@45.743,18.276 J3.15@46.209,18.276 ; J3.15@46.205,18.28 J3.15@46.209,18.276 ; v1(46.34,26.61) 46.34,25.736 47.2,24.876 47.2,18.56 46.916,18.276 J3.15@46.209,18.276
  Bottom Layer w0.1: U30.10@33.83,53.56 33.83,52.82 R98.1@34.4,52.25 34.96,51.69 34.96,50.96 35.285,50.635 R103.1@35.51,50.41 R102.1@36.51,50.41 37.23,50.41 37.62,50.02 37.62,48.564 39.79,46.394 39.79,45.735 43.59,41.935 43.59,36.707 43.91,36.387 43.91,34.077 42.535,32.702 42.535,30.703 46.34,26.898 v1(46.34,26.61)
NetJ3_17: J3.17 R96.2 U26.12 | length 61.6
  Top Layer w0.1: U26.12@22.39,58.16 22.39,58.55 v1(22.39,58.68) ; v1(45.98,26.26) 45.98,25.813 47,24.793 47,18.79 46.886,18.676 J3.17@46.209,18.676
  Int2 (Sign) w0.1: v1(22.39,58.68) 22.554,58.516 22.554,56.714 22.34,56.5 22.34,55.425 22.02,55.105 22.02,54.019 22.849,53.19 27.928,53.19 31.78,49.338 31.78,48.897 35.177,45.5 35.438,45.5 35.588,45.35 v1(35.61,45.35)
  Int3 (Sign) w0.1: v1(35.61,45.35) 35.61,45.285 37.011,43.884 38.756,43.884 41.281,43.884 41.437,44.04 44.693,44.04 45.37,43.363 45.37,40.47 44.42,39.52 44.42,27.323 45.483,26.26 v1(45.98,26.26)
  Bottom Layer w0.1: v1(22.39,58.68) 22.52,58.68 22.59,58.61 R96.2@22.59,58.02
NetJ5_A5: J5.A5 U28.A1 | length 10.9
  Top Layer w0.1: J5.A5@24.02,65.115 24.02,64.57 24.17,64.42 24.17,61.98 23.79,61.6 23.79,60.86 24.06,60.59 24.06,58.64 24.71,57.99 24.71,55.31 24.9,55.12 U28.A1@24.9,54.92
NetJ5_A8: J5.A8 TP2.1 | length 1.9
  Top Layer w0.1: TP2.1@22.52,63.25 J5.A8@22.52,65.115
NetJ5_B5: J5.B5 U28.B1 | length 25.6
  Top Layer w0.1: J5.B5@22.77,66.415 v1(22.77,67.54) ; v1(24.26,56.6) 24.5,56.36 U28.B1@24.5,54.92
  Int3 (Sign) w0.1: v1(22.77,67.54) 22.25,68.06 18.69,68.06 17.67,67.04 17.67,57.54 18.74,56.47 20.162,56.47 20.792,57.1 23.545,57.1 24.045,56.6 v1(24.26,56.6)
NetJ5_B8: J5.B8 TP3.1 | length 13.3
  Top Layer w0.1: TP3.1@16.42,63.05 16.93,63.56 v1(16.93,63.89) ; J5.B8@24.27,66.415 24.27,67.17 v1(24.47,67.37)
  Int2 (Sign) w0.1: v1(16.93,63.89) 16.93,66.65 18.43,68.15 23.69,68.15 v1(24.47,67.37)
NetJ6_9: J6.9 J6.12 R25.2 | length 17
  Top Layer w0.3: R25.2@94.52,26.48 95.53,26.48 96.95,27.9 J6.12@97.2,27.9 97.45,27.9 98.2,28.65 J6.9@98.2,41.05
NetJ6_10: J6.10 J6.11 R20.1 T1.1 U7.1 | length 24.1
  Top Layer w0.1: T1.1@79.955,30.34 80.55,30.34 v1(80.79,30.58) ; R20.1@81.03,31.4 R20.1@81.03,31.35 81.03,30.82 ; v1(81.89,43.85) 81.89,43.04 U7.1@81.9,43.03 ; v1(80.79,30.58) 81.03,30.82 ; v1(80.79,30.58) 81.03,30.82
  Top Layer w0.2: v1(82.65,33.9) 82.95,33.9 83.07,34.02 84.05,35 J6.11@84.05,35.2
  Top Layer w0.4: v1(83.02,29.5) J6.10@84.05,29.5
  Int2 (Sign) w0.1: v1(80.79,30.58) 81.87,29.5 v1(83.02,29.5) 83.66,30.14 83.66,32.89 v1(82.65,33.9) 82.13,34.42 82.13,37.039 82.13,43.61 v1(81.89,43.85)
NetJ12_12: J12.12 Y1.3 | length 3.4
  Top Layer w0.2: Y1.3@90.65,19.07 90.65,19.17 91.93,20.45 J12.12@93.45,20.45
NetJ14_2: J14.2 R61.2 R68.2 | length 9.7
  Top Layer w0.1: J14.2@93.59,60.855 J14.2@93.595,60.85
  Top Layer w0.4: J14.2@93.595,60.85 v1(94.99,60.85)
  Int2 (Sign) w0.4: v1(94.49,55.61) 94.99,55.61 96.13,56.75 96.13,59.71 v1(94.99,60.85)
  Bottom Layer w0.4: R61.2@93.74,54.7 R68.2@93.74,55.61 v1(94.49,55.61)
NetJ14_3: J14.3 R101.2 R104.2 | length 8.7
  Top Layer w0.1: J14.3@93.59,59.605 93.595,59.6 v1(94.99,59.6) v1@95.05,59.6
  Int2 (Sign) w0.1: v1(93.74,53.83) 94.09,54.18 94.09,58.7 v1(94.99,59.6)
  Bottom Layer w0.12: R104.2@93.74,52.91 v1(93.74,53.83)
NetJ16_L13: J16.L13 R52.2 | length 1.7
  Top Layer w0.1: J16.L13@86.155,49.69 86.155,47.995 R52.2@86.16,47.99
NetJ16_R13: J16.R13 R53.2 | length 2.8
  Top Layer w0.1: J16.R13@72.185,49.69 72.185,49.655 73.88,47.96 74.216,47.96 R53.2@74.247,47.99
NetJ18_20: J18.20 R45.1 | length 67.2
  Top Layer w0.1: R45.1@11.65,9.81 11.66,9.8 12.045,9.8 12.495,10.25 v1(13.05,10.25)
  Int2 (Sign) w0.1: v1(13.05,10.25) 13.07,10.23 14.168,10.23 15.38,10.23 20.47,15.32 39.76,15.32 41.25,16.81 41.25,17.765 41.25,18.055 41.25,21.885 42.455,23.09 v1(42.71,23.09)
  Int3 (Sign) w0.1: v1(42.71,23.09) 57.89,23.09 62.91,28.11 v1(63.75,28.95)
  Bottom Layer w0.1: J18.20@62.85,26.16 64.01,26.16 64.15,26.3 64.15,28.55 v1(63.75,28.95)
NetJ18_30: J18.30 R55.1 | length 16.7
  Int3 (Sign) w0.1: v1(61.46,22.53) 61.46,23.07 63.79,25.4 63.792,25.4 64.042,25.65 70.21,25.65 70.89,24.97 v1(72.64,24.97)
  Bottom Layer w0.1: v1(61.46,22.53) 61.83,22.16 J18.30@62.85,22.16 ; v1(72.64,24.97) 72.64,25.29 73.46,26.11 R55.1@74.02,26.11
NetJ18_32: J18.32 R56.1 | length 17.7
  Int3 (Sign) w0.1: v1(61.04,22.15) 61.6,22.15 61.811,22.361 61.811,23.139 63.873,25.2 63.875,25.2 64.125,25.45 70.127,25.45 70.807,24.77 70.81,24.77 70.82,24.76 71.88,24.76 v1(72.54,24.1)
  Bottom Layer w0.1: v1(61.04,22.15) 61.04,21.87 61.55,21.36 J18.32@62.85,21.36 ; v1(72.54,24.1) 73.36,24.1 73.45,24.19 R56.1@74.02,24.19
NetJ18_42: J18.42 R57.1 | length 65.7
  Int2 (Sign) w0.1: v1(2.06,11.21) 8.91,11.21 10.81,9.31 12.685,9.31 13.405,10.03 14.25,10.03 15.463,10.03 20.553,15.12 37.303,15.12 37.453,14.97 v1(37.475,14.97)
  Bottom Layer w0.1: v1(2.06,11.21) R57.1@2.06,11.9 ; v1(37.475,14.97) 37.485,14.96 54.38,14.96 56.19,16.77 61.11,16.77 61.7,17.36 J18.42@62.85,17.36
NetJ18_44: J18.44 R58.1 | length 66.3
  Int2 (Sign) w0.1: v1(2.02,9.45) 3.58,11.01 8.827,11.01 10.727,9.11 13.613,9.11 14.334,9.83 15.546,9.83 20.636,14.92 36.867,14.92 37.177,14.61 v1(37.83,14.61)
  Bottom Layer w0.1: v1(2.02,9.45) 2.02,10.07 R58.1@2.05,10.1 ; v1(37.83,14.61) 38.14,14.61 38.345,14.61 38.39,14.61 38.54,14.76 54.463,14.76 56.263,16.56 J18.44@62.85,16.56
NetJ18_46: J18.46 R59.1 | length 67.3
  Int2 (Sign) w0.1: v1(2.09,7.68) 5.22,10.81 8.744,10.81 10.644,8.91 13.696,8.91 13.81,9.024 14.416,9.63 15.629,9.63 20.719,14.72 36.784,14.72 37.244,14.26 v1(38.2,14.26)
  Bottom Layer w0.1: R59.1@2.06,8.38 2.09,8.35 v1(2.09,7.68) ; v1(38.2,14.26) 38.8,14.26 39.1,14.56 54.546,14.56 56.336,16.35 61.14,16.35 61.73,15.76 J18.46@62.85,15.76
NetJ22_17: J22.17 TP11.1 | length 11.7
  Bottom Layer w0.1: TP11.1@6.95,3.41 6.968,3.428 7.478,3.428 8.94,4.89 14.923,4.89 16.26,6.227 J22.17@16.26,7.46
NetJ22_18: J22.18 TP12.1 | length 10.8
  Bottom Layer w0.1: TP12.1@6.95,4.67 8.4,4.67 8.82,5.09 14.84,5.09 15.76,6.01 J22.18@15.76,7.46
NetJ22_20: J22.20 Q7.2 R99.1 | length 31.1
  Top Layer w0.1: v1(38.82,13.13) 39.05,12.9 39.05,11.684 39.28,11.454 R99.1@39.28,11.03 39.28,10.64 39.18,10.54 Q7.2@39.18,9.995
  Int2 (Sign) w0.1: v1(14.76,8.63) 14.782,8.63 14.982,8.83 15.96,8.83 21.05,13.92 36.453,13.92 37.092,13.28 38.36,13.28 38.51,13.13 v1(38.82,13.13)
  Bottom Layer w0.1: J22.20@14.76,7.46 v1(14.76,8.63)
NetJ22_21: J22.21 Q8.2 R100.1 | length 30.6
  Top Layer w0.1: v1(39.18,13.66) Q8.2@39.18,14.365 39.18,14.95 39.28,15.05 R100.1@39.28,15.42
  Int2 (Sign) w0.1: v1(14.26,8.41) 14.26,8.376 14.278,8.358 14.278,8.41 14.278,8.643 14.41,8.775 14.665,9.03 15.878,9.03 20.967,14.12 36.536,14.12 37.175,13.48 39,13.48 v1(39.18,13.66)
  Bottom Layer w0.1: J22.21@14.26,7.46 v1(14.26,8.41)
NetJ22_23: J22.23 TP13.1 | length 8.1
  Bottom Layer w0.1: TP13.1@6.95,5.93 8.15,5.93 8.78,5.3 12.1,5.3 13.26,6.46 J22.23@13.26,7.46
NetJ22_24: J22.24 TP14.1 | length 8
  Bottom Layer w0.1: TP14.1@6.95,7.19 7.088,7.052 7.478,7.052 9.03,5.5 12.017,5.5 12.76,6.243 J22.24@12.76,7.46
NetL1_2: L1.2 U5.8 | length 2
  Bottom Layer w0.254: U5.8@30.575,50.36 30.682,50.253 30.682,50.165 32.41,50.165 L1.2@32.43,50.185
NetL2_2: L2.2 U5.5 | length 2
  Bottom Layer w0.254: L2.2@24.88,50.185 24.915,50.22 26.765,50.22 U5.5@26.765,50.36
NetL16_2: L16.2 T5.3 | length 6.8
  Bottom Layer w0.4: T5.3@74.4,38.29 74.4,37.34 75.1,36.64 75.1,33.55 75.5,33.15 L16.2@76.7,33.15
NetL24_1: L24.1 U21.4
NetL24_2: L24.2 U21.2
NetL25_1: L25.1 U22.5
NetLED1_1: LED1.1 R57.2 | length 1.5
  Top Layer w0.1: v1@0.89,12.58 v1(0.96,12.58) 0.96,11.895 LED1.1@0.955,11.89
  Bottom Layer w0.1: v1(0.96,12.58) 0.96,11.95 R57.2@1.01,11.9
NetLED2_1: LED2.1 R58.2 | length 1.7
  Top Layer w0.1: v1(0.95,10.9) 0.95,10.105 LED2.1@0.955,10.1
  Bottom Layer w0.1: v1@0.88,10.9 0.83,10.9 0.95,10.78 R58.2@0.95,10.1
NetLED3_1: LED3.1 R59.2 | length 1.4
  Top Layer w0.1: LED3.1@0.955,8.38 v1(0.955,9.1)
  Bottom Layer w0.1: v1(0.955,9.1) 0.96,9.095 R59.2@0.96,8.38
NetQ1_1: Q1.1 Q2.3 R3.1 | length 5.8
  Top Layer w0.1: Q2.3@13.37,23.435 13.37,24.13 13.01,24.49 11.92,24.49 v1(11.49,24.92) ; v1(11.49,24.92) 11.49,25.004 Q1.1@11.49,25.575 v1(11.49,24.92)
  Bottom Layer w0.1: R3.1@10.23,25.675 10.695,25.675 11.45,24.92 v1(11.49,24.92)
NetQ1_3: Q1.3 R4.1 R10.1 | length 47.7
  Top Layer w0.1: v1(10.19,27.41) 10.19,26.538 10.84,25.888 Q1.3@10.84,23.425 Q1.3@10.84,23.3 ; v1(10.83,22.61) Q1.3@10.83,23.3 ; v1(33.71,49.16) R10.1@34.26,49.16
  Int3 (Sign) w0.1: v1(10.19,27.41) 10.271,27.41 10.421,27.26 19.903,27.26 20.96,28.317 20.96,41.314 22.026,42.38 24,42.38 25.49,43.87 30.533,43.87 33.43,46.767 33.43,48.88 v1(33.71,49.16)
  Bottom Layer w0.1: R4.1@10.23,22.615 10.25,22.595 10.265,22.61 v1(10.83,22.61)
NetQ5_1: Q5.1 R79.2 | length 1.3
  Top Layer w0.2: R79.2@23.44,48.25 24.11,48.92 24.11,49.245 Q5.1@24.095,49.26
NetQ5_3: Q5.3 R73.2 U22.3 | length 3.7
  Top Layer w0.1: U22.3@20.12,48.04 20.69,48.04 20.89,48.24 R73.2@21.39,48.24 21.715,48.24 21.908,48.433 21.908,48.928 22.225,49.245 22.225,49.685 22,49.91 Q5.3@21.945,49.91
NetQ6_3: Q6.3 R89.1 | length 1.6
  Top Layer w0.1: R89.1@31.72,56.635 32.295,56.06 Q6.3@33.075,56.06
NetR10_2: R10.2 U6.26 | length 2
  Top Layer w0.1: R10.2@35.31,49.16 35.771,49.16 36.04,49.43 36.5,49.89 U6.26@37,49.89
NetR13_2: R13.2 U6.35 | length 2.3
  Top Layer w0.1: U6.35@41.5,48.39 41.5,47.879 41.71,47.67 R13.2@43.25,47.67
NetR14_2: R14.2 U6.11 | length 1.6
  Top Layer w0.1: U6.11@41.5,54.34 41.5,54.39 41.5,55.2 41.71,55.41 R14.2@42.2,55.41
NetR15_2: R15.2 U6.22 | length 2
  Top Layer w0.1: R15.2@35.325,52.675 35.735,52.675 36.13,52.28 36.52,51.89 U6.22@37,51.89
NetR16_2: R16.2 U6.24 | length 1.7
  Top Layer w0.1: R16.2@35.3,50.95 35.98,50.95 36.04,50.89 U6.24@37,50.89
NetR17_2: R17.2 U6.25 | length 1.8
  Top Layer w0.1: R17.2@35.3,50.05 35.8,50.05 36.14,50.39 U6.25@37,50.39
NetR18_2: R18.2 U6.28 | length 3.3
  Top Layer w0.1: R18.2@35.76,47.15 35.76,47.56 35.95,47.75 37.9,47.75 38,47.85 U6.28@38,48.39
NetR27_1: R27.1 T3.3 | length 1.9
  Bottom Layer w0.1: T3.3@78.33,34.95 78.33,36.13 R27.1@78.83,36.63
NetR28_1: R28.1 T3.1 T4.3 | length 6.2
  Bottom Layer w0.1: R28.1@77.64,30.56 77.64,31.411 77.699,31.47 78.205,31.976 78.205,32.315 T4.3@78.33,32.44 ; T4.3@78.205,32.44 78.205,33.575 80.005,35.375 T3.1@80.23,35.6
NetR34_2: R34.2 U11.11 | length 1.6
  Bottom Layer w0.254: R34.2@42.09,27.91 42.09,27.46 42.355,27.195 U11.11@42.355,26.44
NetR35_2: R35.2 U11.12 | length 1.5
  Bottom Layer w0.254: U11.12@43.005,26.44 R35.2@43.005,27.91
NetR36_2: R36.2 R43.1 U11.13 | length 49.6
  Top Layer w0.1: v1(6.245,9.81) R43.1@6.57,9.81
  Int2 (Sign) w0.1: v1(6.245,9.81) 7.05,9.81 8.35,8.51 13.862,8.51 14.21,8.858 14.582,9.23 15.795,9.23 20.884,14.32 36.619,14.32 37.253,13.686 38.706,13.686 41.66,16.64 41.66,17.52 42.72,18.58 v1(42.72,22.27)
  Bottom Layer w0.1: v1(42.72,22.27) 43.008,21.983 43.008,20.542 U11.13@43.005,20.54 ; U11.13@42.995,20.47 43.005,20.46 43.005,19.015 R36.2@43.01,19.01
NetR37_2: R37.2 R44.1 U11.14 | length 45.7
  Top Layer w0.1: v1(8.58,9.84) 8.61,9.81 R44.1@9.11,9.81
  Int2 (Sign) w0.1: v1(8.58,9.84) 9.431,9.84 10.561,8.71 13.779,8.71 14.01,8.941 14.499,9.43 15.712,9.43 20.802,14.52 36.701,14.52 37.336,13.886 38.623,13.886 41.46,16.723 41.46,17.603 42.34,18.483 v1(42.34,21.58)
  Bottom Layer w0.1: R37.2@42.12,19.01 42.12,19.48 42.355,19.715 U11.14@42.355,20.54 ; v1(42.34,21.58) 42.345,21.575 U11.14@42.345,20.47
NetR40_2: R40.2 R41.2 U11.8 | length 7.7
  Top Layer w0.127: R40.2@38.925,20.036 R41.2@39.815,20.036 40.71,20.931 40.71,25.06 40.41,25.36 v1(40.41,25.35)
  Bottom Layer w0.127: U11.8@40.395,26.37 40.395,25.365 v1(40.41,25.35)
NetR43_2: R43.2 SW1.1 | length 1.8
  Top Layer w0.1: R43.2@6.83,10.695 SW1.1@6.83,12.45
NetR44_2: R44.2 SW1.2 | length 1.5
  Top Layer w0.1: R44.2@9.37,10.91 SW1.2@9.37,12.45
NetR45_2: R45.2 SW1.3 | length 1.5
  Top Layer w0.1: R45.2@11.91,10.91 SW1.3@11.91,12.45
NetR46_1: R46.1 R47.1 T6.3 | length 3.1
  Bottom Layer w0.1: T6.3@78.305,38.3 78.305,39.565 78.48,39.74 R47.1@78.48,40.39
  Bottom Layer w0.127: R47.1@78.48,40.39 R46.1@78.48,41.36
NetR48_2: R48.2 T6.1 | length 0.9
  Bottom Layer w0.127: T6.1@80.455,38.95 80.455,39.815 R48.2@80.47,39.83
NetR50_1: R50.1 Y1.1 | length 1.4
  Top Layer w0.1: Y1.1@89.05,21.27 R50.1@89.05,22.67
NetR64_1: R64.1 R67.2 U21.10 | length 2.5
  Top Layer w0.254: U21.10@20.28,54.24 20.28,54.54 20.676,54.936 20.676,55.458 R64.1@20.674,55.46 20.676,55.462 20.676,56.538 R67.2@20.674,56.54
NetR65_2: R65.2 U21.6 | length 0.9
  Top Layer w0.25: U21.6@20.535,52.24 21.139,52.24 21.169,52.21 21.22,52.21 R65.2@21.37,52.06
NetR66_2: R66.2 U21.7 | length 1.7
  Top Layer w0.2: U21.7@20.28,52.74 20.708,52.74 21.42,52.74 21.665,52.985 R66.2@21.84,53.16
NetR69_1: R69.1 R70.1 T12.2 | length 6.2
  Top Layer w0.1: R69.1@10.38,67.56 R70.1@9.44,67.56 8.541,68.459 8.531,68.469 8.531,70.119 7.7,70.95 T12.2@7.2,70.95 ; T12.2@7.2,70.95 6.9,70.95 T12.2@7.2,70.95
NetR71_2: R71.2 U22.8 | length 1.7
  Top Layer w0.2: U22.8@17.34,46.74 17.665,46.74 17.69,46.715 17.69,46.42 R71.2@18.46,45.65
NetR72_1: R72.1 R77.2 U22.7 | length 2.5
  Top Layer w0.2: v1(16.49,47.39) U22.7@17.34,47.39
  Bottom Layer w0.2: R72.1@15.6,46.65 15.605,46.655 16.465,46.655 R77.2@16.47,46.66 16.48,46.67 16.48,47.37 v1@16.49,47.38
NetR74_2: R74.2 U22.6 | length 0.9
  Top Layer w0.12: v1(16.49,48.04) U22.6@17.34,48.04
NetR75_2: R75.2 U22.1 | length 1.5
  Top Layer w0.1: U22.1@20.12,46.74 20.59,46.74 21.13,46.2 R75.2@21.44,46.2
NetR83_2: R83.2 U23.3 | length 1.3
  Bottom Layer w0.305: R83.2@74.64,13.65 74.99,13.3 75.7,13.3 75.7,13.33 U23.3@75.73,13.36
NetR86_2: R86.2 U24.3 | length 1.4
  Top Layer w0.2: R86.2@10.77,26.72 U24.3@12.12,26.72
NetR89_2: R89.2 R90.2 U29.A3 | length 7.5
  Top Layer w0.1: v1(27.06,59.66) 27.06,59.579 27.16,59.479 27.16,59.255 27.26,59.155 27.26,58.65 U29.A3@27.59,58.32 ; v1(29.71,56.62) 29.75,56.62 29.77,56.64 29.775,56.635 R89.2@30.62,56.635 R90.2@30.62,55.715
  Int3 (Sign) w0.1: v1(27.06,59.66) 27.06,59.27 27.26,59.07 v1(29.71,56.62)
NetR93_1: R93.1 R94.1 U30.5 | length 2.5
  Bottom Layer w0.1: U30.5@34.23,55.96 34.435,55.96 34.865,55.96 35.93,55.96 R93.1@35.94,55.97 36.74,55.97 R94.1@36.75,55.98
NetR95_1: R95.1 U26.3 | length 4
  Top Layer w0.1: v1(21.43,55.17) 21.87,55.17 22.12,55.42 22.12,56.15 22.39,56.42 U26.3@22.39,56.76
  Bottom Layer w0.1: R95.1@20.36,54.27 20.36,54.72 20.81,55.17 v1(21.43,55.17)
NetR97_1: R97.1 U30.16 | length 1.2
  Bottom Layer w0.1: R97.1@31.16,55.45 31.46,55.45 31.75,55.16 U30.16@32.23,55.16
NetTP4_1: TP4.1 U29.B1 U29.B2 U29.C1 | length 3.4
  Top Layer w0.1: U29.C1@28.59,57.32 28.9,57.01 29.52,57.01 30.04,57.53 TP4.1@30.67,57.53
  Top Layer w0.25: U29.B2@28.09,57.82 U29.B1@28.09,57.32 U29.C1@28.59,57.32
NetTP5_1: TP5.1 U28.C3 | length 1.3
  Top Layer w0.1: TP5.1@23.95,52.85 24.1,53 U28.C3@24.1,54.12
NetTP6_1: TP6.1 U30.2 | length 4
  Top Layer w0.1: v1(33.03,56.68) 33.342,56.68 34.22,55.802 TP6.1@34.22,54.1
  Bottom Layer w0.1: U30.2@33.03,55.96 v1(33.03,56.68)
NetTP7_1: TP7.1 U30.9 | length 2.4
  Top Layer w0.1: v1(35.27,53.77) 35.68,54.18 TP7.1@36.29,54.18
  Bottom Layer w0.1: U30.9@34.23,53.56 34.23,53.53 34.3,53.46 34.96,53.46 v1(35.27,53.77)
POWERIN: J19.3 L23.1
RTS_B_RS232: J10.4 U11.7 | length 14.2
  Int2 (Sign) w0.1: J10.4@30.46,19.75 31.71,21 37.935,21 39.486,22.551 39.486,25.076 v1(39.76,25.35)
  Bottom Layer w0.1: U11.7@39.755,26.44 39.755,25.385 39.76,25.38 v1(39.76,25.35)
RXA: J9.3 U10.8 | length 24.7
  Int3 (Sign) w0.1: J9.3@30.44,12.77 31.93,14.26 33.988,14.26 35.68,15.952 35.68,18.693 35.41,18.964 35.41,32.464 35.26,32.614 v1(35.26,32.93) 35.36,32.93 v1@35.41,32.88
  Bottom Layer w0.1: v1(35.26,32.93) 35.26,32.95 35.28,32.93 U10.8@36.055,32.93
RXC: J8.3 U10.13 | length 13.2
  Int2 (Sign) w0.1: J8.3@30.54,31.77 32.37,33.6 36.313,33.6 36.955,33.6 38.65,35.295 38.65,35.925 38.65,36.215 v1(38.65,36.44)
  Bottom Layer w0.1: v1(38.65,36.44) 38.65,36.74 38.655,36.745 U10.13@38.655,38.88
RXD_B_RS232: J10.3 U11.16 | length 13
  Bottom Layer w0.1: J10.3@30.44,22.27 31.8,23.63 37.53,23.63 38.82,22.34 40.08,22.34 40.878,21.542 41.045,21.375 U11.16@41.045,20.47
S_TX1_N: C94.2 U26.7 | length 1.6
  Top Layer w0.149: U26.7@23.69,57.26 23.756,57.26 23.806,57.31 23.806,57.335 23.97,57.335 24.013,57.292 24.148,57.292 v1(24.23,57.21)
  Bottom Layer w0.149: v1(24.23,57.21) 24.298,57.21 24.423,57.335 24.659,57.335 24.96,57.034 C94.2@24.98,57.034
S_TX1_P: C93.2 U26.8 | length 1.6
  Top Layer w0.149: U26.8@23.69,57.66 23.756,57.66 23.806,57.61 23.806,57.585 23.97,57.585 24.018,57.633 24.153,57.633 v1(24.23,57.71)
  Bottom Layer w0.149: v1(24.23,57.71) 24.298,57.71 24.423,57.585 24.68,57.585 24.96,57.864 C93.2@24.98,57.864
S_TX2_N: C96.2 U26.6 | length 4
  Top Layer w0.149: v1(22.88,55.455) 22.948,55.455 23.079,55.586 23.211,55.586 23.515,55.89 23.515,56.418 23.557,56.46 23.557,56.727 U26.6@23.59,56.76
  Bottom Layer w0.149: v1(22.88,55.455) 22.948,55.455 23.073,55.58 23.936,55.58 24.645,55.58 24.96,55.265 C96.2@24.98,55.265
S_TX2_P: C95.2 U26.5 | length 3.6
  Top Layer w0.149: v1(22.88,55.955) 22.948,55.955 23.068,55.835 23.107,55.835 23.265,55.993 23.265,56.418 23.223,56.46 23.223,56.727 U26.5@23.19,56.76
  Bottom Layer w0.149: v1(22.88,55.955) 22.948,55.955 23.073,55.829 24.039,55.829 24.645,55.829 24.96,56.145 C95.2@24.98,56.145
SD_A_VSEL: J2.54 TP26.1 | length 2.6
  Top Layer w0.1: J2.54@54.34,42.23 54.34,40.933 v1(54.59,40.683)
  Bottom Layer w0.1: TP26.1@54.26,39.87 54.305,39.915 54.305,40.398 v1(54.59,40.683)
SPI_C_MISO: J2.85 TP20.1 | length 2.4
  Top Layer w0.1: TP20.1@47.93,47.77 47.94,47.76 J2.85@47.94,45.41
SPI_C_MOSI: J2.87 TP21.1 | length 2.7
  Top Layer w0.1: TP21.1@46.67,47.77 47.54,46.9 J2.87@47.54,45.41
SPI_C_SCLK: J2.89 TP22.1 | length 3.1
  Top Layer w0.1: TP22.1@45.41,47.79 47.14,46.06 J2.89@47.14,45.41
SPI_C_SS0: J2.83 TP19.1 | length 2.7
  Top Layer w0.1: J2.83@48.34,45.41 48.34,46.92 TP19.1@49.19,47.77
SS_RX1_N: U26.1 U27.C2 | length 7.3
  Top Layer w0.149: U27.C2@19.602,59.737 19.602,59.722 19.577,59.696 19.577,59.649 19.527,59.599 19.527,59.283 19.652,59.158 v1(19.652,59.09) ; v1(21.21,55.92) 21.21,55.94 21.519,56.249 21.519,56.437 21.575,56.494 21.575,56.745 U26.1@21.59,56.76
  Int2 (Sign) w0.1: v1(19.652,59.09) 19.652,59.17 19.523,59.299 19.523,59.456 19.582,59.515 20.829,59.515 21.342,59.002 21.342,56.934 21.344,56.933 21.344,56.129 21.21,55.995 v1(21.21,55.92)
SS_RX1_P: U26.2 U27.C1 | length 8.1
  Top Layer w0.149: v1(19.152,59.09) 19.152,59.158 19.278,59.283 19.278,59.599 19.228,59.649 19.228,59.696 19.202,59.722 U27.C1@19.202,59.737 ; v1(21.72,55.92) 21.768,55.968 21.768,56.334 21.94,56.506 21.94,56.71 U26.2@21.99,56.76
  Int2 (Sign) w0.1: v1(19.152,59.09) 19.152,59.17 19.281,59.299 19.281,59.556 19.482,59.757 20.929,59.757 21.585,59.102 21.585,57.034 21.586,57.033 21.586,56.129 21.72,55.995 v1(21.72,55.92)
SS_RX2_N: U26.16 U27.C4 | length 8.2
  Top Layer w0.149: v1(19.23,57.43) 19.298,57.43 19.423,57.555 20.213,57.555 20.433,57.335 21.148,57.335 21.173,57.31 21.44,57.31 U26.16@21.49,57.26 ; U27.C4@20.402,59.737 20.402,59.722 20.377,59.696 20.377,59.649 20.327,59.599 20.327,59.388 20.415,59.3 20.488,59.3 20.721,59.067 20.721,58.733 20.847,58.608 v1(20.847,58.54)
  Int2 (Sign) w0.1: v1(19.23,57.43) 19.283,57.43 19.412,57.559 19.52,57.559 19.67,57.409 19.67,56.827 19.869,56.629 20.017,56.48 20.42,56.48 20.718,56.778 20.718,58.358 20.847,58.487 v1(20.847,58.54)
SS_RX2_P: U26.15 U27.C3 | length 7.8
  Top Layer w0.149: v1(19.23,57.93) 19.298,57.93 19.423,57.805 20.316,57.805 20.536,57.585 21.148,57.585 21.173,57.61 21.44,57.61 U26.15@21.49,57.66 ; U27.C3@20.002,59.737 20.002,59.722 20.028,59.696 20.028,59.649 20.078,59.599 20.078,59.285 20.311,59.051 20.385,59.051 20.472,58.964 20.472,58.733 20.347,58.608 v1(20.347,58.54)
  Int2 (Sign) w0.1: v1(19.23,57.93) 19.283,57.93 19.412,57.801 19.62,57.801 19.912,57.509 19.912,56.928 20.118,56.722 20.32,56.722 20.476,56.878 20.476,58.358 20.347,58.487 v1(20.347,58.54)
SS_TX1_N: C94.1 U25.C3 | length 4.9
  Top Layer w0.149: U25.C3@25.19,59.77 25.19,59.743 25.265,59.667 25.265,59.229 25.728,58.766 26.082,58.766 26.33,58.518 26.33,58.371 26.107,58.148 25.961,58.002 25.961,57.654 26.137,57.478 26.283,57.332 26.617,57.332 26.742,57.207 v1(26.81,57.207)
  Bottom Layer w0.149: C94.1@26.06,57.034 26.08,57.034 26.315,57.27 26.315,57.277 26.363,57.325 26.624,57.325 26.742,57.207 v1(26.81,57.207)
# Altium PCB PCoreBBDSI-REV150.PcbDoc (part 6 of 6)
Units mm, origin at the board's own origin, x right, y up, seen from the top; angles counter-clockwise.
Board outline 100 x 72 mm, 6 copper layers (Top Layer, Int1 (GND), Int2 (Sign), Int3 (Sign), Int4 (GND), Bottom Layer), stack 1.538 mm thick; 358 components, 405 nets, 1521 pads, 834 vias.
Unrouted connection lines stored in the file: 10.

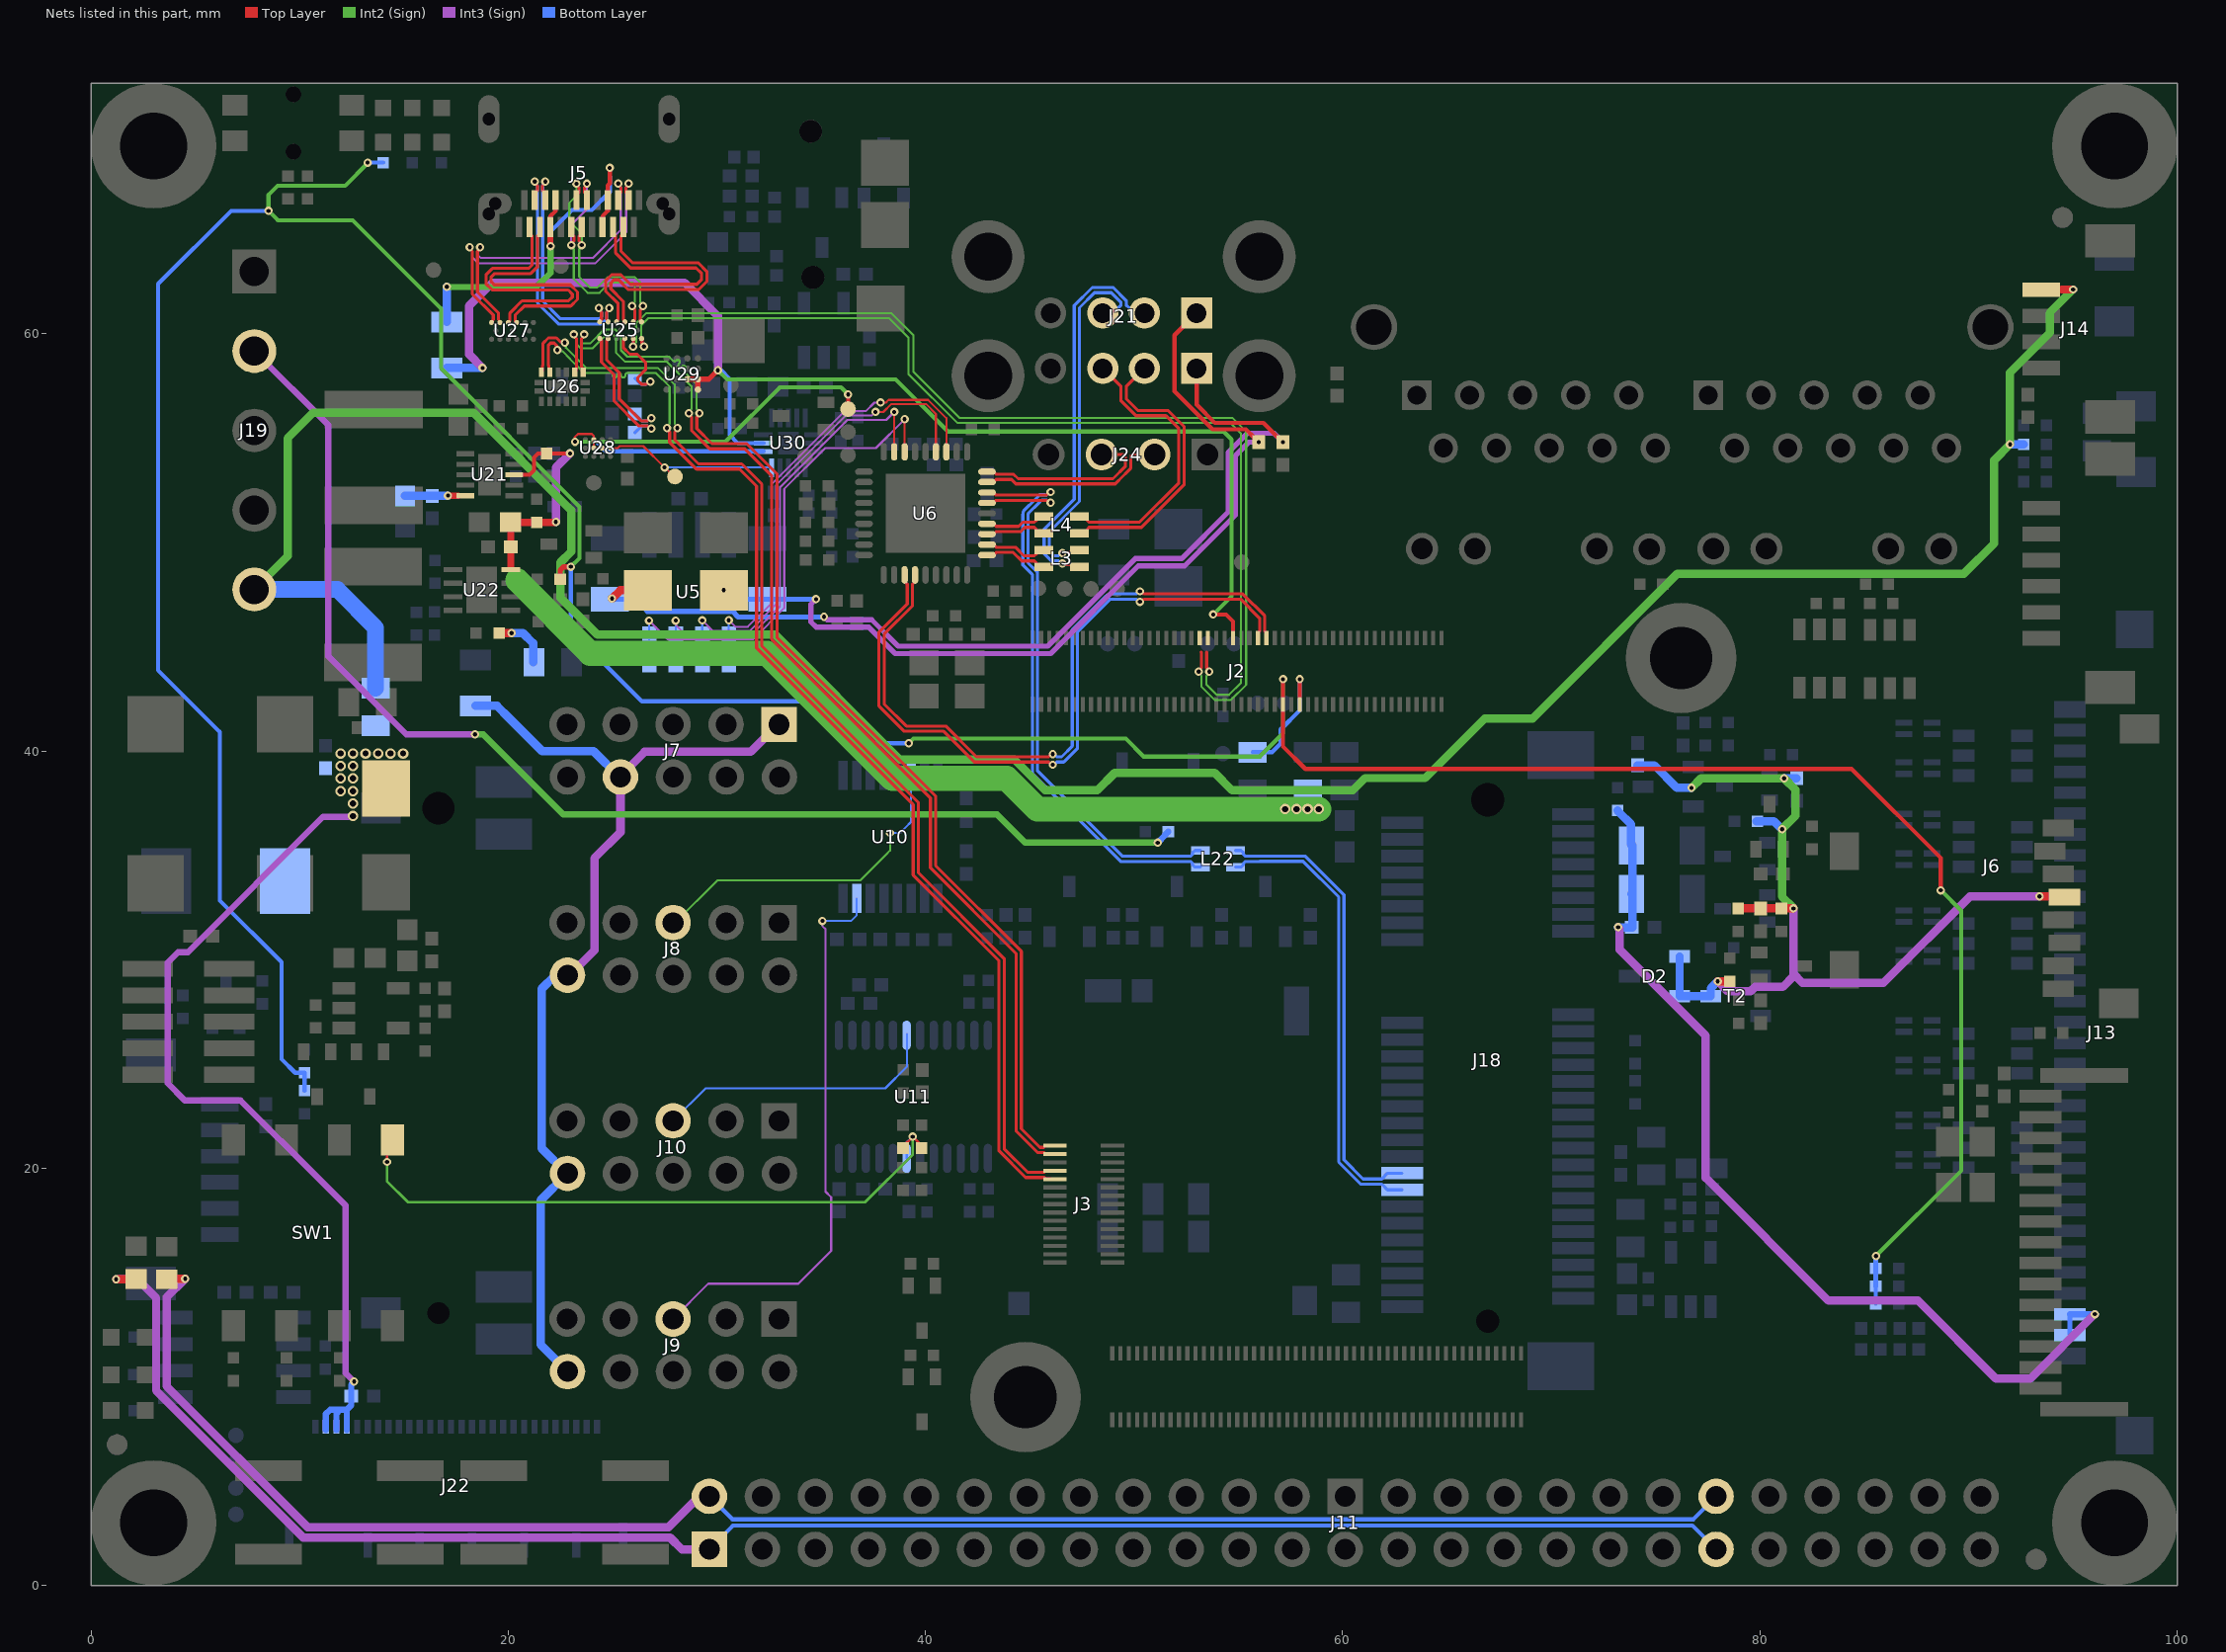
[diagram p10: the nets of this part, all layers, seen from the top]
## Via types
v1: diameter 0.4, hole 0.2, Top Layer to Bottom Layer, tented both sides, 706 vias
v2: diameter 0.5, hole 0.3, Top Layer to Bottom Layer, tented both sides, 102 vias
v3: diameter 0.4, hole 0.2, Top Layer to Bottom Layer, tented bottom, 16 vias
v4: diameter 0.9, hole 0.9, Top Layer to Bottom Layer, tented both sides, 6 vias
v5: diameter 0.5, hole 0.5, Top Layer to Bottom Layer, 2 vias
v6: diameter 3.2, hole 3.2, Top Layer to Bottom Layer, 2 vias

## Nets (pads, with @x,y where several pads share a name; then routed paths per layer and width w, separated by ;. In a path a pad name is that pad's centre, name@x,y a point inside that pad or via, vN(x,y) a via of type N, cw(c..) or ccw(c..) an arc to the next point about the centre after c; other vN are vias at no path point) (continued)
SS_TX1_P: C93.1 U25.C4 | length 4.5
  Top Layer w0.149: U25.C4@25.59,59.77 25.59,59.743 25.515,59.667 25.515,59.332 25.832,59.015 26.185,59.015 26.579,58.622 26.579,58.268 26.21,57.898 26.21,57.758 26.386,57.581 26.617,57.581 26.742,57.707 v1(26.81,57.707)
  Bottom Layer w0.149: C93.1@26.06,57.864 26.08,57.864 26.315,57.629 26.315,57.622 26.363,57.574 26.609,57.574 26.742,57.707 v1(26.81,57.707)
SS_TX2_N: C96.1 U25.C1 | length 6.6
  Top Layer w0.149: U25.C1@24.39,59.77 24.39,59.743 24.465,59.667 24.465,58.638 25.069,58.035 25.069,56.774 26.262,55.58 26.667,55.58 26.792,55.455 v1(26.86,55.455)
  Bottom Layer w0.149: C96.1@26.06,55.265 26.08,55.265 26.395,55.58 26.667,55.58 26.792,55.455 v1(26.86,55.455)
SS_TX2_P: C95.1 U25.C2 | length 6.2
  Top Layer w0.149: U25.C2@24.79,59.77 24.79,59.743 24.715,59.667 24.715,58.741 25.318,58.138 25.318,56.877 26.366,55.829 26.667,55.829 26.792,55.955 v1(26.86,55.955)
  Bottom Layer w0.149: C95.1@26.06,56.145 26.08,56.145 26.395,55.829 26.667,55.829 26.792,55.955 v1(26.86,55.955)
SSRX1_N: J5.B10 U27.A2 | length 15.2
  Top Layer w0.149: v1(18.65,64.14) 18.65,64.072 18.525,63.947 18.525,62.004 19.527,61.002 19.527,60.675 19.577,60.625 19.577,60.578 19.602,60.552 U27.A2@19.602,60.537 ; J5.B10@25.27,66.415 25.27,66.701 25.345,66.776 25.395,66.776 25.395,67.007 25.27,67.132 v1(25.27,67.2)
  Int3 (Sign) w0.1: v1(18.65,64.14) 18.65,64.077 18.531,63.958 18.531,63.79 18.691,63.63 24.05,63.63 25.389,64.969 25.389,67.018 25.27,67.137 v1(25.27,67.2)
SSRX1_P: J5.B11 U27.A1 | length 16
  Top Layer w0.149: v1(18.15,64.14) 18.15,64.072 18.275,63.947 18.275,61.901 19.278,60.899 19.278,60.675 19.228,60.625 19.228,60.578 19.202,60.552 U27.A1@19.202,60.537 ; J5.B11@25.77,66.415 25.77,66.701 25.695,66.776 25.645,66.776 25.645,67.007 25.77,67.132 v1(25.77,67.2)
  Int3 (Sign) w0.1: v1(18.15,64.14) 18.15,64.077 18.269,63.958 18.269,63.682 18.582,63.368 24.158,63.368 25.651,64.861 25.651,67.018 25.77,67.137 v1(25.77,67.2)
SSRX2_N: J5.A10 U27.A4 | length 13
  Top Layer w0.149: U27.A4@20.402,60.537 20.402,60.564 20.327,60.64 20.327,60.886 20.765,61.324 22.992,61.324 23.318,61.649 23.318,62.001 22.976,62.343 19.331,62.343 19.181,62.492 19.181,62.721 19.344,62.884 21.077,62.884 21.395,63.201 21.395,63.988 21.395,64.665 21.52,64.79 J5.A10@21.52,65.115
SSRX2_P: J5.A11 U27.A3 | length 13
  Top Layer w0.149: U27.A3@20.002,60.537 20.002,60.564 20.078,60.64 20.078,60.989 20.661,61.573 22.889,61.573 23.069,61.752 23.069,61.897 22.873,62.094 19.228,62.094 18.932,62.389 18.932,62.824 19.241,63.133 20.974,63.133 21.145,63.304 21.145,63.885 21.145,64.665 21.02,64.79 J5.A11@21.02,65.115
SSTX1_N: J5.A3 U25.A3 | length 13.4
  Top Layer w0.149: J5.A3@25.02,65.115 25.02,64.79 25.145,64.665 25.145,63.866 25.859,63.152 29.004,63.152 29.269,62.887 29.269,62.602 29.038,62.371 25.852,62.371 25.396,62.828 24.964,62.828 24.665,62.529 24.665,62.051 25.265,61.451 25.265,60.673 25.19,60.597 U25.A3@25.19,60.57
SSTX1_P: J5.A2 U25.A4 | length 13.4
  Top Layer w0.149: J5.A2@25.52,65.115 25.52,64.79 25.395,64.665 25.395,63.969 25.962,63.401 29.107,63.401 29.518,62.991 29.518,62.499 29.141,62.122 25.749,62.122 25.293,62.579 25.067,62.579 24.915,62.426 24.915,62.154 25.515,61.554 25.515,60.673 25.59,60.597 U25.A4@25.59,60.57
SSTX2_N: J5.B3 U25.A1 | length 11.2
  Top Layer w0.149: J5.B3@21.77,66.415 21.77,66.74 21.695,66.815 21.693,66.815 21.645,66.863 21.645,67.093 21.773,67.222 v1(21.773,67.29) ; v1(24.34,61.23) 24.34,61.162 24.465,61.037 24.465,60.673 24.39,60.597 U25.A1@24.39,60.57
  Bottom Layer w0.149: v1(21.773,67.29) 21.773,67.222 21.648,67.097 21.648,61.576 22.505,60.719 24.378,60.719 24.465,60.806 24.465,61.037 24.34,61.162 v1(24.34,61.23)
SSTX2_P: J5.B2 U25.A2 | length 12
  Top Layer w0.149: J5.B2@21.27,66.415 21.27,66.74 21.345,66.815 21.347,66.815 21.395,66.863 21.395,67.1 21.273,67.222 v1(21.273,67.29) ; U25.A2@24.79,60.57 24.79,60.597 24.715,60.673 24.715,61.037 24.84,61.162 v1(24.84,61.23)
  Bottom Layer w0.149: v1(21.273,67.29) 21.273,67.222 21.399,67.097 21.399,61.473 22.402,60.47 24.481,60.47 24.715,60.703 24.715,61.037 24.84,61.162 v1(24.84,61.23)
T2IN_DE: R39.2 R42.2 SW1.5 U11.19 | length 32.1
  Top Layer w0.127: v1(14.188,20.3) 14.188,21.088 SW1.5@14.45,21.35 ; R42.2@38.925,20.964 38.925,21.045 v1(39.39,21.51) 39.815,21.085 R39.2@39.815,20.964
  Int2 (Sign) w0.127: v1(14.188,20.3) 14.188,19.387 15.205,18.37 37.11,18.37 39.39,20.65 v1(39.39,21.51)
  Bottom Layer w0.127: U11.19@39.095,20.47 39.095,21.215 v1(39.39,21.51)
TXA: J9.5 U10.7 | length 27.5
  Int3 (Sign) w0.1: J9.5@27.9,12.77 29.59,14.46 33.905,14.46 35.48,16.035 35.48,18.61 35.21,18.881 35.21,31.46 35.06,31.61 v1(35.06,31.85)
  Bottom Layer w0.1: v1(35.06,31.85) 36.42,31.85 36.705,32.135 U10.7@36.705,32.93
TXC: J8.5 U10.14 | length 16.1
  Int2 (Sign) w0.1: J8.5@28,31.77 30.03,33.8 36.519,33.8 36.872,33.8 38.1,35.028 38.3,35.228 v1(38.3,36.07)
  Bottom Layer w0.1: v1(38.3,36.07) 38.78,36.07 39.05,36.34 39.305,36.595 U10.14@39.305,38.88
TXD_B_RS232: J10.5 U11.6 | length 13.9
  Bottom Layer w0.1: J10.5@27.9,22.27 29.46,23.83 38.07,23.83 39.105,24.865 U11.6@39.105,26.44
U\S\B\_\H\U\B\_\A\_\O\C\: U5.2 U6.13 | length 22.6
  Top Layer w0.1: v1(37.6,56.25) 37.98,56.25 38.36,56.63 40.02,56.63 40.5,56.15 U6.13@40.5,54.39
  Int3 (Sign) w0.1: v1(29.3,46.26) 29.81,45.75 31.564,45.75 32.83,47.016 32.83,52.727 36.193,56.09 37.44,56.09 v1(37.6,56.25)
  Bottom Layer w0.1: v1(29.3,46.26) 29.3,44.865 U5.2@29.305,44.86
U\S\B\_\H\U\B\_\B\_\O\C\: U5.3 U6.17 | length 21.9
  Top Layer w0.1: U6.17@38.5,54.39 v1(38.5,56.25)
  Int3 (Sign) w0.1: v1(28.03,46.25) 28.048,46.232 28.048,46.022 28.52,45.55 31.647,45.55 33.03,46.933 33.03,52.644 36.256,55.87 38.12,55.87 v1@38.5,56.25
  Bottom Layer w0.1: v1(28.03,46.25) 28.03,44.865 U5.3@28.035,44.86
USB1_CC1: TP9.1 U28.A2 U30.13 | length 8.9
  Top Layer w0.1: U28.A2@24.9,54.52 25.25,54.52 25.25,54.522 25.338,54.61 26.47,54.61 v1(27.49,53.59) 27.52,53.59 27.96,53.15 TP9.1@27.99,53.15
  Bottom Layer w0.1: v1(27.49,53.59) 32.6,53.59 U30.13@32.63,53.56
USB1_CC2: TP10.1 U28.B2 U28.C1 U28.C2 U30.14 | length 26.5
  Top Layer w0.1: v1(23.2,54.82) 23.2,54.99 23.17,55.02 23.345,55.195 24.005,55.195 24.1,55.1 U28.C1@24.1,54.92 U28.C2@24.1,54.52 ; U28.C2@24.1,54.52 U28.B2@24.5,54.52
  Top Layer w0.2: TP10.1@36.29,56.39 v1(36.29,57.09)
  Int2 (Sign) w0.2: v1(23.2,54.82) 30.41,54.82 33.02,57.43 34.054,57.43 34.386,57.43 35.95,57.43 v1(36.29,57.09)
  Bottom Layer w0.2: v1(23.2,54.82) 24.21,54.82 24.67,54.36 U30.14@32.23,54.36
USB1_CN_D_N: J5.A7 J5.B7 U25.A5 | length 12.2
  Top Layer w0.149: v1(23.02,64.25) 23.02,64.318 23.145,64.443 23.145,64.665 23.02,64.79 J5.A7@23.02,65.115 ; J5.B7@23.77,66.415 23.77,66.691 23.695,66.766 23.645,66.766 23.645,66.997 23.77,67.122 v1(23.77,67.19) ; v1(25.94,61.33) 25.94,61.262 26.072,61.13 26.072,60.679 25.99,60.597 U25.A5@25.99,60.57
  Int2 (Sign) w0.1: v1(23.02,64.25) 23.02,64.187 23.139,64.068 23.139,63.9 23.139,62.623 23.802,61.96 24.38,61.96 24.878,62.458 25.952,62.458 26.07,62.34 26.07,61.512 25.94,61.383 v1(25.94,61.33)
  Int3 (Sign) w0.1: v1(23.02,64.25) 23.02,65.22 23.77,65.97 v1(23.77,67.19)
USB1_CN_D_P: J5.A6 J5.B6 U25.A6 | length 12.2
  Top Layer w0.149: J5.B6@23.27,66.415 23.27,66.691 23.345,66.766 23.395,66.766 23.395,66.997 23.27,67.122 v1(23.27,67.19) ; v1(23.52,64.25) 23.52,64.318 23.395,64.443 23.395,64.665 23.52,64.79 J5.A6@23.52,65.115 ; U25.A6@26.39,60.57 26.39,60.597 26.321,60.666 26.321,61.117 26.461,61.257 v1(26.461,61.325)
  Int2 (Sign) w0.1: v1(23.27,67.19) 23.27,66.61 22.93,66.27 22.93,65.401 23.52,64.811 v1(23.52,64.25) 23.52,64.187 23.401,64.068 23.401,63.792 23.401,62.731 23.91,62.222 24.272,62.222 24.77,62.72 26.06,62.72 26.331,62.449 26.331,61.507 26.461,61.377 v1(26.461,61.325)
USB1_OTG_VBUS: F2.1 J5.A4 J5.A9 J5.B4 J5.B9 | length 19
  Top Layer w0.2: J5.A9@22.02,65.115 22.02,65.638 22.27,65.888 J5.B4@22.27,66.415 ; J5.A4@24.52,65.115 24.52,65.64 24.77,65.89 J5.B9@24.77,66.415 24.77,67.104 24.87,67.204 24.87,67.94 v1(24.86,67.95)
  Top Layer w0.3: J5.A9@22.02,65.115 22.02,64.21 v1(22.03,64.2)
  Int2 (Sign) w0.3: v1(17.06,62.25) 17.068,62.242 21.352,62.242 22.03,62.92 v1(22.03,64.2)
  Bottom Layer w0.2: v1(22.03,64.2) 22.064,64.234 22.064,64.934 23.06,65.93 24,65.93 24.87,66.8 24.87,67.536 24.86,67.546 v1(24.86,67.95)
  Bottom Layer w0.4: F2.1@17.06,60.56 v1(17.06,62.25)
USB1_OTG_VBUS_F: F2.2 J2.51 U29.C2 U29.D1 U29.D2 U30.15 | length 64.6
  Top Layer w0.2: v1(53.79,46.54) 54.41,46.54 54.74,46.21 J2.51@54.74,45.41
  Top Layer w0.25: U29.C2@28.59,57.82 U29.D2@29.09,57.82 ; U29.D1@29.09,57.32 U29.D2@29.09,57.82 ; v1(30.05,58.25) 29.62,57.82 U29.D2@29.09,57.82
  Int2 (Sign) w0.2: v1(30.05,58.25) 30.49,57.81 38.574,57.81 41.074,55.31 54.29,55.31 54.67,54.93 54.67,47.42 v1(53.79,46.54)
  Int3 (Sign) w0.4: v1(18.77,58.36) 18.12,59.01 18.12,61.33 19.24,62.45 28.45,62.45 30.05,60.85 v1(30.05,58.25)
  Bottom Layer w0.2: v1(30.05,58.25) 30.2,58.25 30.61,57.84 30.61,55.15 31,54.76 U30.15@32.23,54.76
  Bottom Layer w0.4: F2.2@17.06,58.36 v1(18.77,58.36)
USB1_RX_N: J3.23 U26.14 | length 55.9
  Top Layer w0.149: U26.14@21.59,58.16 21.64,58.21 21.64,58.477 21.665,58.502 21.665,59.544 21.919,59.798 22.307,59.798 22.489,59.615 v1@22.52,59.615 ; v1@28.107,55.424 28.107,55.412 27.981,55.287 27.981,54.902 29.122,53.761 31.188,53.761 32.151,52.798 32.151,45.038 39.658,37.532 39.658,34.156 43.771,30.042 43.771,20.927 44.898,19.801 45.691,19.801 45.719,19.829 45.719,19.851 45.969,19.851 J3.23@45.994,19.876
  Int2 (Sign) w0.1: v1@22.748,59.613 22.762,59.599 22.762,59.337 23.195,58.904 23.195,58.899 23.734,58.36 27.175,58.36 27.975,57.56 27.975,56.591 27.978,56.588 27.978,55.689 28.107,55.56 v1(28.107,55.48)
  other v1: 22.706,59.576
USB1_RX_P: J3.21 U26.13 | length 56
  Top Layer w0.149: U26.13@21.99,58.16 21.94,58.21 21.94,58.477 21.915,58.502 21.915,59.441 22.022,59.549 22.203,59.549 22.313,59.439 v1@22.313,59.408 ; v1(27.607,55.48) 27.607,55.412 27.732,55.287 27.732,54.798 29.019,53.512 31.085,53.512 31.902,52.695 31.902,44.935 39.409,37.428 39.409,34.053 43.522,29.939 43.522,20.824 44.795,19.551 45.691,19.551 45.719,19.523 45.719,19.501 45.969,19.501 J3.21@45.994,19.476
  Int2 (Sign) w0.1: v1(22.352,59.222) 22.409,59.166 22.591,59.166 22.953,58.804 22.953,58.799 23.634,58.118 24.66,58.118 24.91,58.118 cw(c24.91,58.018) 25.01,58.018 25.01,58 ccw(c25.11,58) 25.21,58 25.21,58.018 cw(c25.31,58.018) 25.41,58.018 25.41,58 ccw(c25.51,58) 25.61,58 25.61,58.018 cw(c25.71,58.018) 25.71,58.118 25.953,58.118 27.074,58.118 27.733,57.459 27.733,56.49 27.736,56.488 27.736,55.689 27.607,55.56 v1(27.607,55.48)
USB1_TX_N: J3.29 U26.9 | length 55.2
  Top Layer w0.149: U26.9@23.59,58.16 23.54,58.21 23.54,58.373 23.515,58.398 23.515,59.777 23.64,59.902 v1(23.64,59.97) ; v1(29.163,56.19) 29.163,56.122 29.038,55.997 29.038,55.456 29.762,54.731 31.437,54.731 32.881,53.287 32.881,45.451 40.488,37.844 40.488,34.501 44.598,30.391 44.598,21.886 45.483,21.001 45.668,21.001 45.743,21.076 J3.29@45.994,21.076
  Int2 (Sign) w0.1: v1(23.64,59.97) 23.64,59.89 23.511,59.761 23.511,59.604 23.57,59.545 23.94,59.545 24.596,60.202 25.125,60.202 25.4,59.927 25.4,59.21 25.71,58.9 27.699,58.9 27.705,58.9 27.737,58.868 27.9,58.705 ccw(c27.971,58.776) 28.041,58.705 28.054,58.718 cw(c28.125,58.647) 28.196,58.718 cw(c28.125,58.647) 28.196,58.576 28.183,58.563 ccw(c28.254,58.493) 28.183,58.422 ccw(c28.254,58.493) 28.324,58.422 28.337,58.435 cw(c28.408,58.364) 28.478,58.435 cw(c28.408,58.364) 28.478,58.293 28.466,58.281 ccw(c28.536,58.21) 28.466,58.139 28.607,57.998 28.642,57.962 29.031,57.574 29.031,57.301 29.034,57.298 29.034,56.399 29.163,56.27 v1(29.163,56.19)
USB1_TX_P: J3.27 U26.10 | length 55.1
  Top Layer w0.149: v1(23.14,59.97) 23.14,59.902 23.265,59.777 23.265,58.335 23.24,58.31 23.24,58.21 U26.10@23.19,58.16 ; v1(28.663,56.19) 28.663,56.122 28.789,55.997 28.789,55.353 29.659,54.482 31.334,54.482 32.632,53.184 32.632,45.348 40.239,37.741 40.239,34.398 44.349,30.288 44.349,21.782 45.38,20.751 45.691,20.751 45.719,20.723 45.719,20.701 45.969,20.701 J3.27@45.994,20.676
  Int2 (Sign) w0.1: v1(23.14,59.97) 23.14,59.89 23.269,59.761 23.269,59.504 23.469,59.303 24.04,59.303 24.697,59.96 25.025,59.96 25.158,59.827 25.158,59.109 25.609,58.658 27.604,58.658 28.789,57.474 28.789,57.201 28.792,57.198 28.792,56.399 28.663,56.27 v1(28.663,56.19)
USB_HUB_A_EN: U5.1 U6.12 | length 21.8
  Top Layer w0.1: v1(37.85,56.7) 38.1,56.7 38.23,56.83 40.12,56.83 41,55.95 U6.12@41,54.39
  Int3 (Sign) w0.1: v1(30.57,46.27) 30.89,45.95 31.481,45.95 32.63,47.099 32.63,52.81 36.11,56.29 37.14,56.29 37.55,56.7 v1(37.85,56.7)
  Bottom Layer w0.1: v1(30.57,46.27) 30.57,44.865 U5.1@30.575,44.86
USB_HUB_A_N: J21.A2 L3.3 | length 18.8
  Top Layer w0.149: v1(46.57,48.98) 46.618,48.932 47.278,48.932 L3.3@47.38,48.83
  Bottom Layer w0.149: v1(46.57,48.98) 46.502,48.98 46.377,49.105 46.043,49.105 45.683,49.466 45.683,50.616 47.128,52.061 47.128,61.347 47.993,62.213 49.007,62.213 49.625,61.595 49.625,61.368 49.744,61.248 50.242,61.248 J21.A2@50.5,60.99
USB_HUB_A_P: J21.A3 L3.2 | length 17.6
  Top Layer w0.149: v1(46.57,49.48) 46.618,49.528 47.278,49.528 L3.2@47.38,49.63
  Bottom Layer w0.149: v1(46.57,49.48) 46.502,49.48 46.377,49.355 46.146,49.355 45.932,49.569 45.932,50.513 47.377,51.958 47.377,61.244 48.097,61.964 48.903,61.964 49.375,61.492 49.375,61.368 49.256,61.248 48.758,61.248 J21.A3@48.5,60.99
USB_HUB_A_PWR: C4.1 C6.2 J21.A1 L1.1 | length 43
  Top Layer w0.1: C4.1@30.32,47.715 C4.1@30.33,47.705
  Top Layer w0.2: J21.A1@53,60.99 51.94,59.93 51.94,57.24 53.758,55.422 55.358,55.422 55.75,55.03 55.77,55.03 55.98,54.82 v1(55.98,54.8)
  Int3 (Sign) w0.25: v1(34.752,47.275) 34.51,47.033 34.51,46.19 34.76,45.94 37.276,45.94 38.546,44.67 46,44.67 50.2,48.87 52.42,48.87 54.858,51.308 54.858,54.163 55.495,54.8 v1(55.98,54.8)
  Bottom Layer w0.25: v1(30.325,47.71) 30.76,47.275 L1.1@32.43,47.275 v1(34.752,47.275)
USB_HUB_B_EN: U5.4 U6.16 | length 23.2
  Top Layer w0.1: U6.16@39,54.39 v1(39,55.9)
  Int3 (Sign) w0.1: v1(26.75,46.25) 27.65,45.35 31.73,45.35 33.23,46.85 33.23,52.561 35.189,54.52 37.294,54.52 37.62,54.52 v1(39,55.9)
  Bottom Layer w0.1: v1@26.75,46.25 26.75,44.875 U5.4@26.765,44.86
USB_HUB_B_N: J21.B2 L4.3 | length 14
  Top Layer w0.149: L4.3@47.38,50.44 47.63,50.44 47.755,50.565 47.755,50.628 47.843,50.715 50.359,50.715 52.391,52.748 52.391,55.562 51.632,56.321 50.187,56.321 49.625,56.884 49.625,57.465 J21.B2@50.5,58.34
USB_HUB_B_P: J21.B3 L4.2 | length 13.5
  Top Layer w0.149: L4.2@47.38,51.24 47.63,51.24 47.755,51.115 47.755,51.052 47.843,50.965 50.256,50.965 52.142,52.851 52.142,55.459 51.529,56.072 50.084,56.072 49.375,56.781 49.375,57.465 J21.B3@48.5,58.34
USB_HUB_B_PWR: C5.1 C7.2 J21.B1 L2.1 | length 47.8
  Top Layer w0.2: J21.B1@53,58.34 53,56.604 53.874,55.73 56.2,55.73 56.9,55.03 56.92,55.03 57.13,54.82 v1(57.13,54.8)
  Top Layer w0.4: v1(24.975,47.31) 25.37,47.705 C5.1@26.7,47.705
  Int3 (Sign) w0.25: v1(35.135,46.435) 35.146,46.435 35.291,46.29 37.421,46.29 38.691,45.02 45.855,45.02 50.055,49.22 52.275,49.22 54.508,51.453 54.508,54.308 55.43,55.23 56.71,55.23 57.13,54.81 v1(57.13,54.8)
  Bottom Layer w0.25: L2.1@24.88,47.275 26.095,47.275 26.675,46.695 30.746,46.695 31.021,46.42 35.12,46.42 v1(35.135,46.435)
USB_OTG_D_N: J2.59 U25.C5 | length 51.1
  Top Layer w0.149: v1(25.987,59.39) 25.988,59.392 U25.C5@25.99,59.77 U25.C5@25.99,59.77 ; v1(53.103,43.8) 53.103,43.868 53.228,43.993 53.228,44.72 53.215,44.733 ; J2.59@53.14,45.41 53.14,45.326 J2.59@53.165,45.301
  Int2 (Sign) w0.1: v1(25.987,59.39) 25.987,59.459 26.126,59.599 26.126,60.493 26.623,60.99 38.356,60.99 39.43,59.916 39.43,58.165 41.623,55.972 54.704,55.972 55.372,55.304 55.372,43.17 54.65,42.448 53.86,42.448 53.231,43.077 53.231,43.591 53.103,43.72 v1(53.103,43.8)
USB_OTG_D_P: J2.57 U25.C6 | length 49.6
  Top Layer w0.149: U25.C6@26.39,59.77 26.409,59.751 26.409,59.547 26.508,59.448 v1(26.508,59.381) ; 53.477,44.74 53.477,43.993 53.603,43.868 v1(53.603,43.8) ; J2.57@53.515,45.301 53.54,45.326 J2.57@53.54,45.41
  Int2 (Sign) w0.1: v1(26.508,59.381) 26.508,59.45 26.368,59.589 26.368,60.393 26.723,60.748 38.256,60.748 39.188,59.816 39.188,58.065 41.523,55.73 54.604,55.73 55.13,55.204 55.13,43.271 54.549,42.69 53.961,42.69 53.474,43.177 53.474,43.591 53.603,43.72 v1(53.603,43.8)
USBD_N: J2.45 U6.30 | length 34.3
  Top Layer w0.149: U6.30@39,48.39 39,48.128 39.125,48.002 39.125,47.051 37.772,45.697 37.772,42.149 38.979,40.942 40.874,40.942 42.346,39.47 44.807,39.47 45.902,39.47 46.032,39.34 v1(46.1,39.34) ; v1(50.28,47.15) 50.348,47.15 50.473,47.275 55.109,47.275 56.015,46.369 56.015,45.735 55.94,45.66 J2.45@55.94,45.41
  Bottom Layer w0.149: v1(46.1,39.34) 46.168,39.34 46.298,39.47 46.627,39.47 47.288,40.131 47.288,45.709 48.757,47.178 ; 48.758,47.179 48.83,47.251 cw(c48.888,47.193) 48.888,47.275 50.087,47.275 50.212,47.15 v1(50.28,47.15)
USBD_P: J2.43 U6.31 | length 34.3
  Top Layer w0.149: U6.31@39.5,48.39 39.5,48.128 39.375,48.002 39.375,46.948 38.021,45.594 38.021,42.252 39.082,41.191 40.977,41.191 42.449,39.72 44.91,39.72 45.902,39.719 46.032,39.85 v1(46.1,39.85) ; v1(50.28,47.65) 50.348,47.65 50.473,47.525 55.212,47.525 56.265,46.472 56.265,45.735 56.34,45.66 J2.43@56.34,45.41
  Bottom Layer w0.149: v1(46.1,39.85) 46.168,39.85 46.298,39.72 46.524,39.72 47.039,40.234 47.039,45.812 48.581,47.355 48.654,47.428 cw(c48.888,47.193) 48.888,47.525 50.087,47.525 50.212,47.65 v1(50.28,47.65)
USBDM1_N: L3.4 U6.1 | length 3.1
  Top Layer w0.149: U6.1@42.95,49.39 43.262,49.39 43.388,49.515 44.206,49.515 44.616,49.105 45.217,49.105 45.305,49.018 45.305,48.955 45.43,48.83 L3.4@45.68,48.83
USBDM1_P: L3.1 U6.2 | length 3.1
  Top Layer w0.149: U6.2@42.95,49.89 43.262,49.89 43.388,49.765 44.309,49.765 44.719,49.355 45.217,49.355 45.305,49.442 45.305,49.505 45.43,49.63 L3.1@45.68,49.63
USBDM2_N: L4.4 U6.3 | length 3
  Top Layer w0.149: U6.3@42.95,50.39 43.262,50.39 43.388,50.515 44.569,50.515 44.769,50.715 45.217,50.715 45.305,50.628 45.305,50.565 45.43,50.44 L4.4@45.68,50.44
USBDM2_P: L4.1 U6.4 | length 3
  Top Layer w0.149: U6.4@42.95,50.89 43.262,50.89 43.388,50.765 44.466,50.765 44.666,50.965 45.217,50.965 45.305,51.052 45.305,51.115 45.43,51.24 L4.1@45.68,51.24
USBDM3_N: L22.2 U6.6 | length 26.7
  Top Layer w0.149: U6.6@42.95,51.89 43.262,51.89 43.388,52.015 45.817,52.015 45.932,51.9 v1(46,51.9)
  Bottom Layer w0.149: 45.427,51.881 44.942,51.396 ccw(c45,51.338) 44.918,51.338 44.918,49.021 45.371,48.568 45.371,39.036 49.453,34.955 52.707,34.955 52.795,35.042 52.795,35.105 52.92,35.23 L22.2@53.17,35.23 ; 45.428,51.882 45.576,52.031 45.802,52.031 45.932,51.9 v1(46,51.9)
USBDM3_P: L22.3 U6.7 | length 27.5
  Top Layer w0.149: U6.7@42.95,52.39 43.262,52.39 43.388,52.265 45.787,52.265 45.932,52.41 v1(46,52.41)
  Bottom Layer w0.149: v1(46,52.41) 45.932,52.41 45.802,52.28 45.473,52.28 45.251,52.058 44.765,51.572 ccw(c45,51.338) 44.669,51.338 44.669,48.918 45.122,48.464 45.122,38.933 49.349,34.705 52.707,34.705 52.795,34.618 52.795,34.555 52.92,34.43 L22.3@53.17,34.43
USBDM4_N: J24.2 U6.8 | length 9.1
  Top Layer w0.149: U6.8@42.95,52.89 43.262,52.89 43.388,53.015 44.122,53.015 44.191,52.947 44.337,52.801 49.093,52.801 49.166,52.874 49.412,53.12 49.689,53.396 49.835,53.542 49.835,54.123 49.922,54.21 J24.2@50.98,54.21
USBDM4_P: J24.3 U6.9 | length 8.7
  Top Layer w0.149: U6.9@42.95,53.39 43.262,53.39 43.388,53.265 44.225,53.265 44.44,53.05 48.99,53.05 49.585,53.645 49.585,54.123 49.498,54.21 J24.3@48.44,54.21
USBHUB_C_N: J18.36 L22.1 | length 22.1
  Bottom Layer w0.149: L22.1@54.87,35.23 55.12,35.23 55.245,35.105 55.245,35.042 55.333,34.955 55.92,34.955 55.926,34.961 58.197,34.961 60.058,33.101 60.058,20.398 60.971,19.485 61.875,19.485 62.15,19.76 J18.36@62.85,19.76
USBHUB_C_P: J18.38 L22.4 | length 22.1
  Bottom Layer w0.149: L22.4@54.87,34.43 55.12,34.43 55.245,34.555 55.245,34.618 55.333,34.705 56.023,34.705 56.03,34.712 58.094,34.712 59.809,32.998 59.809,20.294 60.868,19.235 61.875,19.235 62.15,18.96 J18.38@62.85,18.96
V5OUT: J11.2 J11.40 L9.2 | length 85
  Top Layer w0.4: L9.2@3.62,14.675 3.645,14.7 v1(4.51,14.7)
  Int3 (Sign) w0.4: v1(4.51,14.7) 3.62,13.81 3.62,9.55 10.38,2.79 27.681,2.79 28.912,4.021 29.391,4.021 J11.2@29.64,4.27
  Bottom Layer w0.2: J11.2@29.64,4.27 30.74,3.17 76.82,3.17 77.9,4.25 J11.40@77.9,4.27
V33OUT: J11.1 J11.39 L8.1 | length 86.6
  Top Layer w0.4: v1(1.2,14.68) 1.205,14.685 L8.1@2.165,14.685
  Int3 (Sign) w0.4: v1(1.2,14.68) 2.22,14.68 3.12,13.78 3.12,10.653 3.12,9.343 10.173,2.29 27.76,2.29 28.32,1.73 J11.1@29.64,1.73
  Bottom Layer w0.2: J11.1@29.64,1.73 29.64,1.74 30.77,2.87 76.76,2.87 J11.39@77.9,1.73
V_BL: J14.1 J19.5 R61.1 R62.2 | length 130.9
  Top Layer w0.4: 94.46,62.12 v1(95.01,62.12)
  Int2 (Sign) w0.4: J19.5@7.825,47.74 9.42,49.335 9.42,54.99 10.65,56.22 18.334,56.22 23.014,51.541 23.014,49.551 22.5,49.037 22.5,47.347 24.267,45.58 32.783,45.58 38.783,39.58 44.271,39.58 45.742,38.11 48.23,38.11 49.07,38.95 53.86,38.95 54.7,38.11 60.481,38.11 61.071,38.7 63.951,38.7 66.801,41.55 69.101,41.55 76.041,48.49 89.773,48.49 91.23,49.947 91.23,53.94 v1(91.99,54.7) 91.99,58.14 93.89,60.04 93.89,61 v1(95.01,62.12)
  Bottom Layer w0.4: v1(91.99,54.7) R61.1@92.64,54.7
  Bottom Layer w0.8: J19.5@7.825,47.74 11.81,47.74 13.64,45.91 R62.2@13.64,43.01
VBAT_IN: J19.2 R78.2 | length 60.3
  Int2 (Sign) w0.3: 45.8,35.61 51.12,35.61 v1(51.13,35.6)
  Int2 (Sign) w0.305: v1(18.41,40.8) 18.8,40.8 22.65,36.95 43.433,36.95 44.773,35.61 45.8,35.61
  Int3 (Sign) w0.305: J19.2@7.825,59.17 11.38,55.615 11.38,44.539 15.119,40.8 v1(18.41,40.8)
  Bottom Layer w0.3: v1(51.13,35.6) 51.515,35.985 51.515,36.005 R78.2@51.64,36.13
VCC_COM: F1.2 J7.1 J7.8 J8.10 J9.10 J10.10 | length 49
  Int3 (Sign) w0.406: J8.10@22.94,29.25 24.13,30.44 24.13,34.86 25.38,36.11 J7.8@25.38,38.75 ; J7.8@25.33,38.75 26.54,39.96 31.62,39.96 J7.1@32.93,41.27
  Bottom Layer w0.406: F1.2@18.43,42.16 19.46,42.16 20.04,41.58 21.63,39.99 24.09,39.99 J7.8@25.33,38.75 ; J9.10@22.84,10.25 21.55,11.54 21.55,18.46 22.82,19.73 21.6,20.95 21.6,28.6 22.23,29.23 J8.10@22.92,29.23
VDD_3V3: J2.40 R3.2 R4.2 R5.1 R8.1 R9.1 R73.1 R82.2 | length 185.3
  Top Layer w0.2: J2.40@57.138,42.519 v1(57.138,43.44) ; J2.40@57.14,42.45 57.14,40.21 58.21,39.14 84.39,39.14 88.67,34.86 v1(88.67,33.32)
  Top Layer w0.254: R73.1@22.49,48.24 22.49,48.66 22.66,48.83 v1(23,48.83)
  Int2 (Sign) w0.2: v1(13.26,68.2) 13.26,68.17 12.18,67.09 8.94,67.09 8.51,66.66 v1(8.51,65.89) 8.96,65.44 12.544,65.44 16.78,61.204 16.78,58.34 23.414,51.707 23.414,49.243 v1(23,48.83) ; v1(39.2,40.37) 39.42,40.59 49.6,40.59 50.46,39.73 56.03,39.73 57.14,40.84 57.14,43.438 v1(57.138,43.44) ; v1(85.56,15.79) 89.65,19.88 89.65,32.34 v1(88.67,33.32)
  Bottom Layer w0.2: v1(8.51,65.89) 6.72,65.89 3.22,62.39 3.22,43.87 6.18,40.91 6.18,32.83 9.13,29.88 9.13,25.23 9.785,24.575 R3.2@10.23,24.575 R4.2@10.23,23.715 ; v1@13.26,68.2 R82.2@14,68.2 ; v1(23,48.83) 23,45.79 26.405,42.385 34.475,42.385 36.49,40.37 v1(39.2,40.37) ; R8.1@85.55,13.5 R5.1@85.55,14.35
  Bottom Layer w0.254: R5.1@85.55,14.35 R9.1@85.55,15.2 85.55,15.78 v1(85.56,15.79)
VDD_SDCARD: C19.2 C22.2 C23.2 D2.1 D2.2 J6.4 R19.2 R20.2 R21.2 R27.2 T2.3 | length 46.4
  Top Layer w0.1: J6.4@94.57,33.03 J6.4@94.6,33
  Top Layer w0.4: v1(77.98,28.96) R21.2@78.56,28.96 ; R19.2@78.96,32.45 R20.2@81.03,32.45 v1(81.61,32.45) ; v1(93.4,33.03) J6.4@94.57,33.03
  Int2 (Sign) w0.4: v1@76.724,38.23 v1(76.72,38.23) 77.18,38.69 v1(81.16,38.69) 81.71,38.14 81.71,36.9 v1(81.06,36.25) 81.06,33.02 81.61,32.47 v1(81.61,32.45)
  Int3 (Sign) w0.4: v1(77.98,28.96) 78.46,28.48 79.55,28.48 79.76,28.69 81.097,28.69 81.61,29.203 81.61,29.309 ; v1(81.61,32.45) 81.61,29.309 ; v1(93.4,33.03) 90.07,33.03 85.93,28.89 82.028,28.89 81.61,29.309
  Bottom Layer w0.4: C23.2@74.13,39.31 74.94,39.31 76.02,38.23 v1(76.72,38.23) ; D2.1@76.15,30.15 D2.2@76.15,28.25 T2.3@77.64,28.25 77.643,28.253 77.643,28.623 v1(77.98,28.96) ; R27.2@79.83,36.63 R27.2@79.88,36.63 80.67,36.63 81.05,36.25 v1(81.06,36.25) ; v1(81.16,38.69) C22.2@81.76,38.69
VDD_VBAT: J2.36 R76.2 | length 5.9
  Top Layer w0.2: J2.36@57.938,42.519 57.938,42.791 ; 57.94,42.791 v1(57.94,43.44)
  Bottom Layer w0.2: R76.2@55.69,39.94 56.62,39.94 57.03,40.35 57.03,41.03 57.94,41.94 v1(57.94,43.44)
VIN: C71.2 C72.1 C77.2 C78.2 C79.2 C80.2 C106.2 D9.1 J22.25 J22.26 J22.27 R2.2 R62.1 R63.1 R65.1 R66.1 R71.1 U21.5 U21.8 U22.4 | length 102.6
  Top Layer w0.2: U21.8@20.28,53.24 20.703,53.24 21.02,53.24 21.24,53.46 21.24,54.07 21.43,54.26 R66.1@21.84,54.26 v1(22.96,54.26)
  Top Layer w0.3: v1(17.11,52.24) 17.25,52.24 U21.5@17.615,52.24
  Top Layer w0.35: U22.4@20.12,48.75 C80.2@20.12,49.78 20.12,50.95 C79.2@20.11,50.96 22.246,50.96 22.266,50.98 v1(22.28,50.98)
  Top Layer w0.406: R71.1@19.51,45.65 R71.1@19.56,45.65 v1(20.16,45.65)
  Int2 (Sign) w0.45: v2(58.86,37.21) 58.86,37.224 58.885,37.249 v2@58.885,37.379
  Int2 (Sign) w1.15: 20.428,48.182 23.93,44.68
  Int2 (Sign) w1.2: 23.93,44.68 32.41,44.68 38.41,38.68 43.899,38.68 45.369,37.21 v2(57.24,37.21) v2(57.78,37.21) v2(58.32,37.21) v2(58.86,37.21)
  Int3 (Sign) w0.3: v2@12.56,36.84 11.12,36.84 4.64,30.36 4.17,30.36 3.67,29.86 3.67,24.07 4.49,23.25 7.165,23.25 10.96,19.455 12.2,18.215 12.2,10.18 v1(12.61,9.77)
  Int3 (Sign) w0.406: v1(22.28,50.98) 22.28,53.58 v1(22.96,54.26)
  Bottom Layer w0.3: J22.27@11.26,7.46 J22.27@11.26,7.61 11.26,8.22 11.46,8.42 11.94,8.42 ; J22.26@11.76,7.46 J22.26@11.76,7.61 11.76,8.24 11.94,8.42 ; J22.25@12.26,7.46 J22.25@12.26,7.61 12.26,8.42 ; v1(12.61,9.77) 12.61,9.763 12.47,9.623 C106.2@12.47,9.07 12.47,8.63 12.26,8.42 ; 11.94,8.42 12.26,8.42
  Bottom Layer w0.35: R2.2@58.145,38.14 R2.2@58.32,38.14
  Bottom Layer w0.4: C77.2@15.05,52.24 C78.2@16.35,52.24 ; C78.2@16.36,52.24 v1(17.11,52.24)
  Bottom Layer w0.406: v1(20.16,45.65) 20.705,45.65 21.19,45.165 R63.1@21.19,44.26
  other v2: 12.56,36.88 12.56,37.48 11.96,38.08 12.56,38.08 11.96,38.68 12.56,38.68 11.96,39.28 12.56,39.28 11.96,39.88 12.56,39.88 13.16,39.88 13.76,39.88 14.36,39.88 14.96,39.88
VLCD: C45.2 J13.29 J13.30 L11.1 L16.1 R49.2 | length 46.5
  Int3 (Sign) w0.4: v1(73.2,31.55) 73.281,31.469 73.281,30.469 77.4,26.35 77.4,19.535 83.285,13.65 87.58,13.65 91.32,9.91 92.96,9.91 v1(96.05,13)
  Bottom Layer w0.254: J13.30@94.86,12 J13.29@94.86,13
  Bottom Layer w0.3: J13.29@94.86,13 v1(96.05,13)
  Bottom Layer w0.4: R49.2@73.17,37.14 73.245,37.065 73.819,36.491 73.819,35.551 L11.1@73.862,35.508 ; v1(73.2,31.55) 73.21,31.54 C45.2@73.86,31.54 73.9,31.54 L16.1@73.9,33.15 ; L16.1@73.845,33.15 L16.1@73.9,33.15 ; L11.1@73.845,35.47 73.9,35.47 L16.1@73.9,33.15
pads on no net: A-REF1.1 A-REF2.1 A-REF3.1 A-REF4.1 A-REF5.1 A-REF6.1 D1.2 D3.1 D6.1 D12.2 J3.1 J3.3 J3.7 J3.9 J4.None J7.6 J7.7 J7.9 J7.10 J8.1 J8.2 J8.4 J8.6 J8.7 J8.8 J9.1 J9.2 J9.4 J9.6 J9.7 J9.8 J10.1 J10.2 J10.7 J10.8 J11.43 J12.16 J12.17 J13.31 J13.32 J13.33 J13.34 J14.9 J14.10 J15.9 J15.10 J16.L11 J16.L12 J16.R11 J16.R12 J17.DSW2 J18.3 J18.5 J18.7 J18.17 J18.19 J18.45 J18.47 J18.49 J18.51 J18.53 J18.54 J18.55 J18.56 J20.7 J22.40 J22.41 J23.9 J23.10 M1. SP1.1 SP2.1 T10.1 T10.4 T11.1 T11.4 T12.1 T12.4 T12.M1 T12.M2 U1.1 U2.1 U3.1 U6.18 U6.19 U6.20 U6.21 U7.5 U7.6 U8.5 U11.10 U12.5 U13.5 U14.5 U15.5 U16.5 U27.A5 U27.A6 U27.C5 U27.C6 U28.D1 U28.D2
copper on no net: | length 26.8
  Top Layer w0.1: 6.2,23.22 6.65,23.67 7.1,23.22 6.2,23.22 ; 91.725,8.675 92.175,9.125 92.625,8.675 91.725,8.675 ; 93.15,52.8 93.6,52.35 94.05,52.8 93.15,52.8 ; 93.15,63.3 93.6,62.85 94.05,63.3 93.15,63.3
  Top Layer w0.188: 87.12,8.72 ccw(c86.42,8.72) 87.12,8.72
  Top Layer w0.254: 6.41,23.3 6.82,23.3 ; 6.55,23.42 6.6,23.47 6.65,23.47 6.82,23.3 ; 6.87,23.3 6.82,23.3 ; 91.935,8.755 92.345,8.755 ; 92.075,8.875 92.125,8.925 92.175,8.925 92.345,8.755 ; 92.395,8.755 92.345,8.755 ; 93.38,52.72 93.43,52.72 ; 93.38,63.22 93.43,63.22 ; 93.7,52.6 93.65,52.55 93.6,52.55 93.43,52.72 ; 93.7,63.1 93.65,63.05 93.6,63.05 93.43,63.22 ; 93.84,52.72 93.43,52.72 ; 93.84,63.22 93.43,63.22
  Bottom Layer w0.1: 25.05,7.45 25.5,7.9 25.5,7 25.05,7.45 ; 94.05,43.3 94.5,42.85 94.95,43.3 94.05,43.3
  Bottom Layer w0.188: 72.31,62.36 ccw(c71.61,62.36) 72.31,62.36
  Bottom Layer w0.254: 25.3,7.55 25.25,7.5 25.25,7.45 25.42,7.28 ; 25.42,7.23 25.42,7.28 ; 25.42,7.69 25.42,7.28 ; 94.28,43.22 94.33,43.22 ; 94.6,43.1 94.55,43.05 94.5,43.05 94.33,43.22 ; 94.74,43.22 94.33,43.22
  other v4: 4.77,15.775 4.77,24.125 94.89,44.345 94.89,52.695 94.89,57.305 94.89,63.155
  other v5: 19.99,67.09 26.79,67.09
  other v6: 63.55,63.41 88.95,63.41

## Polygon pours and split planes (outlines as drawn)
GND_SHIELD on Top Layer "Polygon_1_Net_GND_SHIELD" (solid, remove dead copper, pour order 29): 20.25,64.29 20,64.04 18.07,64.04 17.8,64.311 17.8,71.371 18.479,72.05 92.571,72.05 93.15,71.471 93.15,64.379 92.25,63.479 92.25,61.071 92.35,60.971 92.35,59.429 91.721,58.8 86.829,58.8 86.45,59.179 86.45,65.479 85.529,66.4 66.921,66.4 66.15,65.629 66.15,59.629 65.521,59 58.421,59 58.05,58.629 58.05,56.579 57.621,56.15 54.729,56.15 54.15,56.729 54.15,63.029 53.629,63.55 45.371,63.55 44.9,63.079 44.9,56.679 44.421,56.2 41.779,56.2 41.25,56.729 41.25,69.279 40.579,69.95 29.621,69.95 29.15,69.479 29.113,64.324 28.83,64.04 27.02,64.04 26.75,64.311 26.75,65.4 26.22,65.93 20.82,65.93 20.25,65.36
GND on Top Layer "Top Layer-GND" (solid, pour order 55): 11.49,27.37 11.56,27.3 13.53,27.3 13.9,27.67 13.9,29.11 14.25,29.46 14.25,30.49 14.47,30.71 15.75,30.71 15.89,30.57 16.71,30.57 16.83,30.69 16.83,34.75 16.27,35.31 7.679,35.3 7.45,35.071 7.45,31.81 7.92,31.34 12.68,31.34 13,31.02 13,29.45 13,28.21 12.83,28.04 11.56,28.04 11.49,27.97
+5VS on Top Layer "NONET_L-01_P-001" (solid, pour order 52): 19.94,55.05 19.33,54.44 18.58,54.44 18.45,54.31 18.45,54.18 18.34,54.07 17.51,54.07 16.57,55.01 16.57,56.05 16.82,56.3 18.11,56.3 18.47,55.94 19.81,55.94 19.95,55.8
NetJ2_24 on Top Layer "Polygon_2_Net_N$3" (solid, remove dead copper, pour order 0): 60.44,40.9 60.44,41.6 58.029,41.6 57.84,41.411 57.84,40.89 58.03,40.7 60.24,40.7
NetL24_2 on Top Layer "Polygon_1_Net_N$65" (solid, remove dead copper, pour order 6): 11.26,57.6 15.88,57.6 16.34,57.14 16.34,54.95 17.34,53.95 18.34,53.95 18.39,53.9 18.39,53.55 18.34,53.5 11.22,53.5 10.87,53.85 10.87,57.21
NetL25_1 on Top Layer "Polygon_1_Net_N$90" (solid, remove dead copper, pour order 5): 17.77,48.45 16.871,48.45 15.941,47.52 11.109,47.52 10.87,47.759 10.87,49.63 11.19,49.95 16.171,49.95 16.385,49.735 16.971,49.15 17.66,49.15 17.86,48.95 17.86,48.54
NetL24_1 on Top Layer "Polygon_1_Net_N$65" (solid, remove dead copper, pour order 23): 11.14,50.5 16.29,50.5 16.8,51.01 16.8,52.36 16.97,52.53 18.32,52.53 18.4,52.61 18.4,52.89 18.31,52.98 11.22,52.98 10.87,52.63 10.87,50.77
POWERIN on Top Layer "Polygon_1_Net_POWERIN" (solid, remove dead copper, pour order 15): 1.279,39.55 5.521,39.55 5.9,39.929 5.9,52.929 6.521,53.55 9.171,53.55 9.55,53.929 9.55,56.721 9.171,57.1 0.979,57.1 0.05,56.171 0.05,40.779
VIN on Top Layer "VIN_L01_P026" (solid, pour order 26): 15.69,39.75 15.22,40.22 11.93,40.22 11.59,39.88 11.59,36.79 11.9,36.48 15.25,36.48 15.69,36.92
+3V3 on Top Layer "Polygon_1_Net_+3V3" (solid, remove dead copper, pour order 10): 15.9,45.47 11.23,45.47 10.96,45.2 10.96,43.42 11.17,43.21 13.028,43.21 13.39,42.848 13.39,40.87 13.65,40.61 16.58,40.61 16.855,40.885 16.855,44.515
NetC70_2 on Top Layer "Polygon_1_Net_N$36" (solid, remove dead copper, pour order 12): 2.16,35.28 4.981,35.28 5.16,35.101 5.16,30.76 5.02,30.62 1.34,30.62 0.89,31.07 0.89,34.84 1.33,35.28
GNDIN on Top Layer "Polygon_1_Net_GNDIN" (solid, remove dead copper, pour order 9): 10.66,42.92 10.88,42.7 10.88,38.779 10.551,38.45 7.209,38.45 6.83,38.829 6.83,42.59 7.16,42.92
GND_SHIELD on Bottom Layer "Bottom Layer-GND_SHIELD" (solid, remove dead copper, pour order 50): 87.4,58.8 95.06,58.8 95.43,58.43 95.43,55.699 95.629,55.5 96.929,55.5 97.128,55.699 98.966,55.699 99.168,55.901 99.2,60.571 98.15,61.621 97.921,61.85 94.44,61.85 93.15,63.14 93.15,71.471 92.571,72.05 18.479,72.05 17.8,71.371 17.8,64.311 18.07,64.04 20,64.04 20.25,64.29 20.25,65.36 20.82,65.93 26.093,65.93 26.75,65.273 26.75,64.311 27.02,64.04 28.83,64.04 29.113,64.324 29.15,69.479 29.621,69.95 40.579,69.95 40.786,69.743 40.786,56.874 41.759,55.901 44.271,55.901 45.05,56.68 45.05,62.59 45.79,63.33 53.199,63.33 54.15,62.379 54.15,56.729 54.729,56.15 57.88,56.15 58.42,56.69 58.42,58.42 58.85,58.85 65.521,58.85 66.15,59.479 66.15,65.629 66.921,66.4 85.529,66.4 86.45,65.479 86.45,59.75 86.45,59.179 86.829,58.8
VIN on Bottom Layer "Bottom Layer-VIN" (solid, pour order 57): 7.64,32.36 7.85,32.15 10.64,32.15 10.89,32.4 10.89,35.73 11.59,36.43 12.56,36.43 12.81,36.68 12.81,38.22 13.15,38.56 15.04,38.56 15.21,38.73 15.21,40.01 15.03,40.19 14.81,40.19 14.44,40.56 14.44,41.75 14.32,41.87 13.03,41.87 12.87,41.71 12.87,40.48 12.58,40.19 11.93,40.19 11.71,39.97 11.71,39.63 11.64,39.56 10.96,39.56 10.89,39.49 10.89,38.34 10.62,38.07 7.99,38.07 7.64,37.72
GND on Bottom Layer "GND_L06_P035" (solid, pour order 35): 27.62,58.36 27.85,58.13 30.32,58.13 30.58,57.87 30.58,57.17 30.92,56.83 31.94,56.83 32.03,56.92 32.03,58.53 33.26,59.76 33.26,60.65 33.06,60.85 32.48,60.85 32.31,60.68 32.31,60.08 32.15,59.92 30.25,59.92 30.02,60.15 30.02,60.76 29.86,60.92 29.34,60.92 28.66,61.61 27.97,61.61 27.62,61.26
GNDIN on Bottom Layer "Bottom Layer-GNDIN" (solid, remove dead copper, pour order 54): 10.58,38.77 10.58,45.341 9.671,46.25 7.321,46.25 6.7,46.871 6.7,49.479 7.221,50 8.89,50 9.55,50.66 9.55,52.41 8.91,53.05 6.975,53.05 6.32,53.705 6.32,60.64 6.89,61.21 9.24,61.21 9.55,61.52 9.55,64.24 9.07,64.72 6.34,64.72 3.85,62.23 3.85,44.18 6.87,41.16 6.87,38.77 7.06,38.58 10.39,38.58
GND on Bottom Layer "GND_L06_P041" (solid, pour order 41): 73.07,18.73 72.9,18.56 72.9,17.54 73.09,17.35 74.74,17.35 75.17,17.78 75.93,17.78 76.09,17.94 76.09,18.42 76.23,18.56 76.95,18.56 77.08,18.69 77.08,21.14 75.93,22.29 75.93,24.19 75.61,24.51 75.26,24.51 74.95,24.2 74.95,22.65 74.5,22.2 74.11,22.2 73.97,22.06 73.97,21.568 73.722,21.32 73.28,21.32 73.03,21.32 72.8,21.09 72.21,20.5 70,20.5 69.91,20.41 69.91,19.11 70.05,18.97 72.21,18.97 72.84,19.6 72.84,20.03 73.22,20.41 75.52,20.41 75.71,20.22 75.71,19.23 75.21,18.73
VIN on Bottom Layer "VIN_L06_P037" (solid, pour order 37): 59.01,38.78 59.17,38.62 59.17,37.08 58.96,36.87 57.11,36.87 56.92,37.06 56.92,37.89 57.11,38.08 57.36,38.08 57.53,38.25 57.53,38.67 57.64,38.78
GND on Bottom Layer "Polygon_4_Net_GND" (solid, remove dead copper, pour order 3): 95.39,52.97 96.511,51.85 98.971,51.85 99.2,52.079 99.2,54.16 99.06,54.3 97.821,54.3 97.121,55 95.49,55 95.39,54.9
NetJ2_24 on Bottom Layer "Polygon_1_Net_N$3" (solid, remove dead copper, pour order 1): 57.55,39.48 57.68,39.35 59.036,39.35 59.1,39.414 59.1,40.479 59.47,40.849 59.47,41.24 59.35,41.36 57.789,41.36 57.55,41.121
NetC70_2 on Bottom Layer "Polygon_1_Net_N$36" (solid, remove dead copper, pour order 24): 4.91,35.46 5.16,35.21 5.16,30.89 4.43,30.16 1.72,30.16 1.51,30.37 1.51,31.11 0.89,31.73 0.89,34.84 1.51,35.46
GND on Int2 (Sign) "Polygon_1_Net_GND" (solid, remove dead copper, pour order 46): 0,72.127 100.127,72.127 100.127,0 0,0
GND_SHIELD on Int2 (Sign) "Polygon_1_Net_GND_SHIELD" (solid, remove dead copper, pour order 16): 20.25,64.29 20,64.04 18.07,64.04 17.8,64.311 17.8,71.371 18.479,72.05 92.571,72.05 93.15,71.471 93.15,64.379 92.25,63.479 92.25,61.071 92.35,60.971 92.35,59.429 91.721,58.8 86.829,58.8 86.45,59.179 86.45,65.479 85.529,66.4 66.921,66.4 66.15,65.629 66.15,59.629 65.521,59 58.421,59 58.05,58.629 58.05,56.579 57.621,56.15 54.729,56.15 54.15,56.729 54.15,63.029 53.629,63.55 45.371,63.55 44.9,63.079 44.9,56.679 44.421,56.2 41.779,56.2 41.25,56.729 41.25,69.279 40.579,69.95 29.621,69.95 29.15,69.479 29.113,64.324 28.83,64.04 27.02,64.04 26.75,64.311 26.75,65.273 26.093,65.93 20.82,65.93 20.25,65.36
VIN on Int2 (Sign) "Polygon_1_Net_VIN" (solid, remove dead copper, pour order 21): 13.77,36.05 17.55,39.83 17.55,43.57 19.33,45.35 22.26,45.35 23.33,46.42 23.33,51.949 20.13,55.15 18.52,56.76 11.54,56.76 9.75,54.97 9.75,46.971 6.45,43.671 6.45,37.72 8.12,36.05
GND on Int3 (Sign) "Polygon_2_Net_GND" (solid, remove dead copper, pour order 30): 0,72.127 100.127,72.127 100.127,0 0,0
GND_SHIELD on Int3 (Sign) "Polygon_1_Net_GND_SHIELD" (solid, remove dead copper, pour order 22): 20.25,64.29 20,64.04 18.07,64.04 17.8,64.311 17.8,71.371 18.479,72.05 92.571,72.05 93.15,71.471 93.15,64.379 92.25,63.479 92.25,61.071 92.35,60.971 92.35,59.429 91.721,58.8 86.829,58.8 86.45,59.179 86.45,65.479 85.529,66.4 66.921,66.4 66.15,65.629 66.15,59.629 65.521,59 58.421,59 58.05,58.629 58.05,56.579 57.621,56.15 54.729,56.15 54.15,56.729 54.15,63.029 53.629,63.55 45.371,63.55 44.9,63.079 44.9,56.679 44.421,56.2 41.779,56.2 41.25,56.729 41.25,69.279 40.579,69.95 29.621,69.95 29.15,69.479 29.113,64.324 28.83,64.04 27.02,64.04 26.75,64.311 26.75,65.273 26.093,65.93 20.82,65.93 20.25,65.36
+3V3 on Int3 (Sign) "Polygon_2_Net_+3V3" (solid, remove dead copper, pour order 47): 14.45,43.829 14.45,44.071 14.829,44.45 16.671,44.45 16.735,44.385 17.1,44.021 17.1,41.079 16.721,40.7 15.529,40.7 14.8,41.429 14.8,43.479
GND on Int4 (GND) "Polygon_6_Net_GND" (solid, remove dead copper, pour order 48): -0.1,-0.1 100.1,-0.1 100.1,72.1 -0.1,72.1
GND_SHIELD on Int4 (GND) "Polygon_1_Net_GND_SHIELD" (solid, remove dead copper, pour order 34): 20.25,64.29 20,64.04 18.07,64.04 17.8,64.311 17.8,71.371 18.479,72.05 92.571,72.05 93.15,71.471 93.15,64.379 92.25,63.479 92.25,61.071 92.35,60.971 92.35,59.429 91.721,58.8 86.829,58.8 86.45,59.179 86.45,65.479 85.529,66.4 66.921,66.4 66.15,65.629 66.15,59.629 65.521,59 58.421,59 58.05,58.629 58.05,56.579 57.621,56.15 54.729,56.15 54.15,56.729 54.15,63.029 53.629,63.55 45.371,63.55 44.9,63.079 44.9,56.679 44.421,56.2 41.779,56.2 41.25,56.729 41.25,69.279 40.579,69.95 29.621,69.95 29.15,69.479 29.113,64.324 28.83,64.04 27.02,64.04 26.75,64.311 26.75,65.273 26.093,65.93 20.82,65.93 20.25,65.36
GND on Int1 (GND) "Polygon_5_Net_GND" (solid, remove dead copper, pour order 45): -0.1,72.1 100.1,72.1 100.1,-0.1 -0.1,-0.1
GND_SHIELD on Int1 (GND) "Polygon_1_Net_GND_SHIELD" (solid, remove dead copper, pour order 31): 20.25,64.29 20,64.04 18.07,64.04 17.8,64.311 17.8,71.371 18.479,72.05 92.571,72.05 93.15,71.471 93.15,64.379 92.25,63.479 92.25,61.071 92.35,60.971 92.35,59.429 91.721,58.8 86.829,58.8 86.45,59.179 86.45,65.479 85.529,66.4 66.921,66.4 66.15,65.629 66.15,59.629 65.521,59 58.421,59 58.05,58.629 58.05,56.579 57.621,56.15 54.729,56.15 54.15,56.729 54.15,63.029 53.629,63.55 45.371,63.55 44.9,63.079 44.9,56.679 44.421,56.2 41.779,56.2 41.25,56.729 41.25,69.279 40.579,69.95 29.621,69.95 29.15,69.479 29.113,64.324 28.83,64.04 27.02,64.04 26.75,64.311 26.75,65.273 26.093,65.93 20.82,65.93 20.25,65.36

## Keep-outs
Keep-Out Layer:
  the board outline again, w0

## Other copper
Top Layer:
  text "+5V" at 17.089,66.82 h0.6 r90
  text "+3V3" at 15.709,66.26 h0.6 r90
  text "+3V3_CPU" at 14.286,63.87 h0.6 r90
  text "WWAN" at 3.23,11.541 h0.7
  text "PCoreBBDSI" at 79.05,10 h0.85
  text "WLAN" at 3.23,9.751 h0.7
  text "c 2025" at 86.097,8.431 h0.85
  text "Rev1.50" at 79.05,8.331 h0.85
  text "WPAN4" at 3.23,8.08 h0.7
  text "RESET" at 9.633,6.78 h1
  text "fs-net.de" at 79.05,6.59 h0.85
Int1 (GND):
  text "Int1" at 92.04,5.648 h1.2
Int2 (Sign):
  text "Int2" at 92.04,5.648 h1.2
Int3 (Sign):
  text "Int3" at 92.04,5.659 h1.2
Int4 (GND):
  text "Int4" at 92.05,5.668 h1.2
Bottom Layer:
  text "PCoreBBDSI" at 79.716,63.64 h0.85
  text "c 2025" at 71.929,62.07 h0.85
  text "Rev1.50" at 79.716,61.97 h0.85
  text "fs-net.de" at 79.716,60.23 h0.85

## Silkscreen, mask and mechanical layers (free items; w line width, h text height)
Top Solder:
  circle w0.188: c86.42,8.72 r0.7
  lines w0.1: 6.2,23.22 7.1,23.22 6.65,23.67 6.2,23.22 ; 91.725,8.675 92.175,9.125 92.625,8.675 91.725,8.675 ; 93.15,52.8 93.6,52.35 94.05,52.8 93.15,52.8 ; 93.15,63.3 93.6,62.85 94.05,63.3 93.15,63.3
  lines w0.254: 6.41,23.3 6.82,23.3 ; 6.55,23.42 6.6,23.47 6.65,23.47 6.82,23.3 ; 6.87,23.3 6.82,23.3 ; 91.935,8.755 92.345,8.755 ; 92.075,8.875 92.125,8.925 92.175,8.925 92.345,8.755 ; 92.395,8.755 92.345,8.755 ; 93.38,52.72 93.43,52.72 ; 93.38,63.22 93.43,63.22 ; 93.7,52.6 93.65,52.55 93.6,52.55 93.43,52.72 ; 93.7,63.1 93.65,63.05 93.6,63.05 93.43,63.22 ; 93.84,52.72 93.43,52.72 ; 93.84,63.22 93.43,63.22
  text "+5V" at 17.089,66.82 h0.6 r90
  text "+3V3" at 15.709,66.26 h0.6 r90
  text "+3V3_CPU" at 14.286,63.87 h0.6 r90
  text "WWAN" at 3.23,11.541 h0.7
  text "PCoreBBDSI" at 79.05,10 h0.85
  text "WLAN" at 3.23,9.751 h0.7
  text "c 2025" at 86.097,8.431 h0.85
  text "Rev1.50" at 79.05,8.331 h0.85
  text "WPAN4" at 3.23,8.08 h0.7
  text "RESET" at 9.633,6.78 h1
  text "fs-net.de" at 79.05,6.59 h0.85
Bottom Solder:
  circle w0.188: c71.61,62.36 r0.7
  lines w0.1: 25.05,7.45 25.5,7 25.5,7.9 25.05,7.45 ; 94.05,43.3 94.5,42.85 94.95,43.3 94.05,43.3
  lines w0.254: 25.3,7.55 25.25,7.5 25.25,7.45 25.42,7.28 ; 25.42,7.23 25.42,7.28 ; 25.42,7.69 25.42,7.28 ; 94.28,43.22 94.33,43.22 ; 94.6,43.1 94.55,43.05 94.5,43.05 94.33,43.22 ; 94.74,43.22 94.33,43.22
  text "PCoreBBDSI" at 79.716,63.64 h0.85
  text "c 2025" at 71.929,62.07 h0.85
  text "Rev1.50" at 79.716,61.97 h0.85
  text "fs-net.de" at 79.716,60.23 h0.85
  text "+" at 4.61,54.649 h3
  text "-" at 4.804,50.839 h3.5
Dimension:
  the board outline again, w0
Top Assembly (Mech10):
  lines w0.12: 82.84,31.05 ccw(c82.71,31.05) 82.71,31.18 82.58,31.18 cw(c82.58,31.661) 82.099,31.661 82.099,31.74 cw(c82.58,31.74) 82.58,32.221 82.59,32.221 ccw(c82.59,32.611) 82.98,32.611 82.98,33.243 cw(c83.649,33.243) 83.649,33.912 83.951,33.912 ccw(c83.951,34.241) 84.28,34.241 84.28,36.691 cw(c85.245,36.691) 85.245,37.656 86.063,37.656 ccw(c86.063,37.896) 86.303,37.896 ccw(c86.049,37.896) 86.049,38.15 85.001,38.15 cw(c85.001,38.711) 85.011,39.271 86.711,39.271 ccw(c86.711,39.455) 86.895,39.455 ; 82.84,31.55 cw(c82.71,31.55) 82.71,31.421 82.58,31.421 cw(c82.58,31.661) 82.34,31.661 82.34,31.74 cw(c82.58,31.74) 82.58,31.98 82.59,31.98 ccw(c82.59,32.611) 83.221,32.611 83.221,33.243 cw(c83.649,33.243) 83.649,33.671 83.951,33.671 ccw(c83.951,34.241) 84.521,34.241 84.521,36.691 cw(c85.245,36.691) 85.245,37.415 86.063,37.415 ccw(c86.063,37.896) 86.544,37.896 ccw(c86.049,37.896) 86.049,38.391 85,38.391 cw(c85.001,38.711) 84.994,39.03 85.01,39.03 ccw(c85.011,39.271) 85.013,39.03 86.77,39.03 cw(c86.77,38.905) 86.895,38.905
Top Name:
  text "PCBBDSI-F4S-240225" at 22.044,76.154 h8
Bottom Name (Mech15):
  text "PCBBDSI-F4S-240225" at 77.956,76.154 h8
Outline:
  the board outline again, w0.1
